# Copyright 2020 The SkyWater PDK Authors
#
# Licensed under the Apache License, Version 2.0 (the "License");
# you may not use this file except in compliance with the License.
# You may obtain a copy of the License at
#
#     https://www.apache.org/licenses/LICENSE-2.0
#
# Unless required by applicable law or agreed to in writing, software
# distributed under the License is distributed on an "AS IS" BASIS,
# WITHOUT WARRANTIES OR CONDITIONS OF ANY KIND, either express or implied.
# See the License for the specific language governing permissions and
# limitations under the License.
#
# SPDX-License-Identifier: Apache-2.0

VERSION 5.7 ;

BUSBITCHARS "[]" ;
DIVIDERCHAR "/" ;

UNITS
  TIME NANOSECONDS 1 ;
  CAPACITANCE PICOFARADS 1 ;
  RESISTANCE OHMS 1 ;
  DATABASE MICRONS 1000 ;
END UNITS

MANUFACTURINGGRID 0.005 ;

PROPERTYDEFINITIONS
  LAYER LEF58_TYPE STRING ;
END PROPERTYDEFINITIONS

# High density, single height
SITE unithd
  SYMMETRY Y ;
  CLASS CORE ;
  SIZE 0.46 BY 2.72 ;
END unithd

# High density, double height
SITE unithddbl
  SYMMETRY Y ;
  CLASS CORE ;
  SIZE 0.46 BY 5.44 ;
END unithddbl

LAYER nwell
  TYPE MASTERSLICE ;
  PROPERTY LEF58_TYPE "TYPE NWELL ;" ;
END nwell

LAYER pwell
  TYPE MASTERSLICE ;
  PROPERTY LEF58_TYPE "TYPE PWELL ;" ;
END pwell

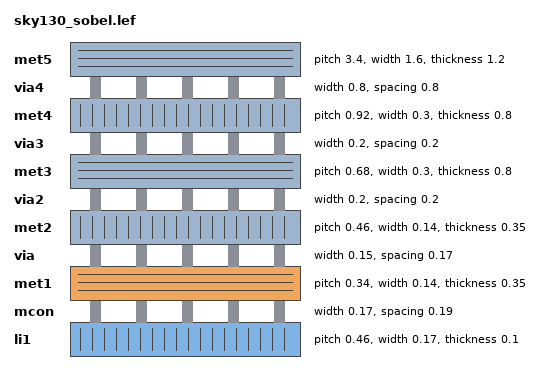
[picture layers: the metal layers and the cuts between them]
LAYER li1
  TYPE ROUTING ;
  DIRECTION VERTICAL ;

  PITCH 0.46 0.34 ;
  OFFSET 0.23 0.17 ;

  WIDTH 0.17 ;          # LI 1
  # SPACING  0.17 ;     # LI 2
  SPACINGTABLE
     PARALLELRUNLENGTH 0
     WIDTH 0 0.17 ;
  AREA 0.0561 ;         # LI 6
  THICKNESS 0.1 ;
  EDGECAPACITANCE 40.697E-6 ;
  CAPACITANCE CPERSQDIST 36.9866E-6 ;
  RESISTANCE RPERSQ 12.2 ;

  ANTENNAMODEL OXIDE1 ;
  ANTENNADIFFSIDEAREARATIO PWL ( ( 0 75 ) ( 0.0125 75 ) ( 0.0225 85.125 ) ( 22.5 10200 ) ) ;
END li1

LAYER mcon
  TYPE CUT ;

  WIDTH 0.17 ;                # Mcon 1
  SPACING 0.19 ;              # Mcon 2
  ENCLOSURE BELOW 0 0 ;       # Mcon 4
  ENCLOSURE ABOVE 0.03 0.06 ; # Met1 4 / Met1 5

  ANTENNADIFFAREARATIO PWL ( ( 0 3 ) ( 0.0125 3 ) ( 0.0225 3.405 ) ( 22.5 408 ) ) ;
  DCCURRENTDENSITY AVERAGE 0.36 ; # mA per via Iavg_max at Tj = 90oC

END mcon

LAYER met1
  TYPE ROUTING ;
  DIRECTION HORIZONTAL ;

  PITCH 0.34 ;
  OFFSET 0.17 ;

  WIDTH 0.14 ;                     # Met1 1
  # SPACING 0.14 ;                 # Met1 2
  # SPACING 0.28 RANGE 3.001 100 ; # Met1 3b
  SPACINGTABLE
     PARALLELRUNLENGTH 0
     WIDTH 0 0.14
     WIDTH 3 0.28 ;
  AREA 0.083 ;                     # Met1 6
  THICKNESS 0.35 ;

  ANTENNAMODEL OXIDE1 ;
  ANTENNADIFFSIDEAREARATIO PWL ( ( 0 400 ) ( 0.0125 400 ) ( 0.0225 2609 ) ( 22.5 11600 ) ) ;

  EDGECAPACITANCE 40.567E-6 ;
  CAPACITANCE CPERSQDIST 25.7784E-6 ;
  DCCURRENTDENSITY AVERAGE 2.8 ; # mA/um Iavg_max at Tj = 90oC
  ACCURRENTDENSITY RMS 6.1 ; # mA/um Irms_max at Tj = 90oC
  MAXIMUMDENSITY 70 ;
  DENSITYCHECKWINDOW 700 700 ;
  DENSITYCHECKSTEP 70 ;

  RESISTANCE RPERSQ 0.125 ;
END met1

LAYER via
  TYPE CUT ;
  WIDTH 0.15 ;                  # Via 1a
  SPACING 0.17 ;                # Via 2
  ENCLOSURE BELOW 0.055 0.085 ; # Via 4a / Via 5a
  ENCLOSURE ABOVE 0.055 0.085 ; # Met2 4 / Met2 5

  ANTENNADIFFAREARATIO PWL ( ( 0 6 ) ( 0.0125 6 ) ( 0.0225 6.81 ) ( 22.5 816 ) ) ;
  DCCURRENTDENSITY AVERAGE 0.29 ; # mA per via Iavg_max at Tj = 90oC
END via

LAYER met2
  TYPE ROUTING ;
  DIRECTION VERTICAL ;

  PITCH 0.46 ;
  OFFSET 0.23 ;

  WIDTH 0.14 ;                        # Met2 1
  # SPACING  0.14 ;                   # Met2 2
  # SPACING  0.28 RANGE 3.001 100 ;   # Met2 3b
  SPACINGTABLE
     PARALLELRUNLENGTH 0
     WIDTH 0 0.14
     WIDTH 3 0.28 ;
  AREA 0.0676 ;                       # Met2 6
  THICKNESS 0.35 ;

  EDGECAPACITANCE 37.759E-6 ;
  CAPACITANCE CPERSQDIST 16.9423E-6 ;
  RESISTANCE RPERSQ 0.125 ;
  DCCURRENTDENSITY AVERAGE 2.8 ; # mA/um Iavg_max at Tj = 90oC
  ACCURRENTDENSITY RMS 6.1 ; # mA/um Irms_max at Tj = 90oC

  ANTENNAMODEL OXIDE1 ;
  ANTENNADIFFSIDEAREARATIO PWL ( ( 0 400 ) ( 0.0125 400 ) ( 0.0225 2609 ) ( 22.5 11600 ) ) ;

  MAXIMUMDENSITY 70 ;
  DENSITYCHECKWINDOW 700 700 ;
  DENSITYCHECKSTEP 70 ;
END met2

# ******** Layer via2, type routing, number 44 **************
LAYER via2
  TYPE CUT ;
  WIDTH 0.2 ;                   # Via2 1
  SPACING 0.2 ;                 # Via2 2
  ENCLOSURE BELOW 0.04 0.085 ;  # Via2 4
  ENCLOSURE ABOVE 0.065 0.065 ; # Met3 4
  ANTENNADIFFAREARATIO PWL ( ( 0 6 ) ( 0.0125 6 ) ( 0.0225 6.81 ) ( 22.5 816 ) ) ;
  DCCURRENTDENSITY AVERAGE 0.48 ; # mA per via Iavg_max at Tj = 90oC
END via2

LAYER met3
  TYPE ROUTING ;
  DIRECTION HORIZONTAL ;

  PITCH 0.68 ;
  OFFSET 0.34 ;

  WIDTH 0.3 ;              # Met3 1
  # SPACING 0.3 ;          # Met3 2
  SPACINGTABLE
     PARALLELRUNLENGTH 0
     WIDTH 0 0.3
     WIDTH 3 0.4 ;
  AREA 0.24 ;              # Met3 6
  THICKNESS 0.8 ;

  EDGECAPACITANCE 40.989E-6 ;
  CAPACITANCE CPERSQDIST 12.3729E-6 ;
  RESISTANCE RPERSQ 0.047 ;
  DCCURRENTDENSITY AVERAGE 6.8 ; # mA/um Iavg_max at Tj = 90oC
  ACCURRENTDENSITY RMS 14.9 ; # mA/um Irms_max at Tj = 90oC

  ANTENNAMODEL OXIDE1 ;
  ANTENNADIFFSIDEAREARATIO PWL ( ( 0 400 ) ( 0.0125 400 ) ( 0.0225 2609 ) ( 22.5 11600 ) ) ;

  MAXIMUMDENSITY 70 ;
  DENSITYCHECKWINDOW 700 700 ;
  DENSITYCHECKSTEP 70 ;
END met3

LAYER via3
  TYPE CUT ;
  WIDTH 0.2 ;                   # Via3 1
  SPACING 0.2 ;                 # Via3 2
  ENCLOSURE BELOW 0.06 0.09 ;   # Via3 4 / Via3 5
  ENCLOSURE ABOVE 0.065 0.065 ; # Met4 3
  ANTENNADIFFAREARATIO PWL ( ( 0 6 ) ( 0.0125 6 ) ( 0.0225 6.81 ) ( 22.5 816 ) ) ;
  DCCURRENTDENSITY AVERAGE 0.48 ; # mA per via Iavg_max at Tj = 90oC
END via3

LAYER met4
  TYPE ROUTING ;
  DIRECTION VERTICAL ;

  PITCH 0.92 ;
  OFFSET 0.46 ;

  WIDTH 0.3 ;             # Met4 1
  # SPACING  0.3 ;             # Met4 2
  SPACINGTABLE
     PARALLELRUNLENGTH 0
     WIDTH 0 0.3
     WIDTH 3 0.4 ;
  AREA 0.24 ;            # Met4 4a

  THICKNESS 0.8 ;

  EDGECAPACITANCE 36.676E-6 ;
  CAPACITANCE CPERSQDIST 8.41537E-6 ;
  RESISTANCE RPERSQ 0.047 ;
  DCCURRENTDENSITY AVERAGE 6.8 ; # mA/um Iavg_max at Tj = 90oC
  ACCURRENTDENSITY RMS 14.9 ; # mA/um Irms_max at Tj = 90oC

  ANTENNAMODEL OXIDE1 ;
  ANTENNADIFFSIDEAREARATIO PWL ( ( 0 400 ) ( 0.0125 400 ) ( 0.0225 2609 ) ( 22.5 11600 ) ) ;

  MAXIMUMDENSITY 70 ;
  DENSITYCHECKWINDOW 700 700 ;
  DENSITYCHECKSTEP 70 ;
END met4

LAYER via4
  TYPE CUT ;

  WIDTH 0.8 ;                 # Via4 1
  SPACING 0.8 ;               # Via4 2
  ENCLOSURE BELOW 0.19 0.19 ; # Via4 4
  ENCLOSURE ABOVE 0.31 0.31 ; # Met5 3
  ANTENNADIFFAREARATIO PWL ( ( 0 6 ) ( 0.0125 6 ) ( 0.0225 6.81 ) ( 22.5 816 ) ) ;
  DCCURRENTDENSITY AVERAGE 2.49 ; # mA per via Iavg_max at Tj = 90oC
END via4

LAYER met5
  TYPE ROUTING ;
  DIRECTION HORIZONTAL ;

  PITCH 3.4 ;
  OFFSET 1.7 ;

  WIDTH 1.6 ;            # Met5 1
  #SPACING  1.6 ;        # Met5 2
  SPACINGTABLE
     PARALLELRUNLENGTH 0
     WIDTH 0 1.6 ;
  AREA 4 ;               # Met5 4

  THICKNESS 1.2 ;

  EDGECAPACITANCE 38.851E-6 ;
  CAPACITANCE CPERSQDIST 6.32063E-6 ;
  RESISTANCE RPERSQ 0.0285 ;
  DCCURRENTDENSITY AVERAGE 10.17 ; # mA/um Iavg_max at Tj = 90oC
  ACCURRENTDENSITY RMS 22.34 ; # mA/um Irms_max at Tj = 90oC

  ANTENNAMODEL OXIDE1 ;
  ANTENNADIFFSIDEAREARATIO PWL ( ( 0 400 ) ( 0.0125 400 ) ( 0.0225 2609 ) ( 22.5 11600 ) ) ;
END met5


### Routing via cells section   ###
# Plus via rule, metals are along the prefered direction
VIA L1M1_PR DEFAULT
  LAYER mcon ;
  RECT -0.085 -0.085 0.085 0.085 ;
  LAYER li1 ;
  RECT -0.085 -0.085 0.085 0.085 ;
  LAYER met1 ;
  RECT -0.145 -0.115 0.145 0.115 ;
END L1M1_PR

VIARULE L1M1_PR GENERATE
  LAYER li1 ;
  ENCLOSURE 0 0 ;
  LAYER met1 ;
  ENCLOSURE 0.06 0.03 ;
  LAYER mcon ;
  RECT -0.085 -0.085 0.085 0.085 ;
  SPACING 0.36 BY 0.36 ;
END L1M1_PR

# Plus via rule, metals are along the non prefered direction
VIA L1M1_PR_R DEFAULT
  LAYER mcon ;
  RECT -0.085 -0.085 0.085 0.085 ;
  LAYER li1 ;
  RECT -0.085 -0.085 0.085 0.085 ;
  LAYER met1 ;
  RECT -0.115 -0.145 0.115 0.145 ;
END L1M1_PR_R

VIARULE L1M1_PR_R GENERATE
  LAYER li1 ;
  ENCLOSURE 0 0 ;
  LAYER met1 ;
  ENCLOSURE 0.03 0.06 ;
  LAYER mcon ;
  RECT -0.085 -0.085 0.085 0.085 ;
  SPACING 0.36 BY 0.36 ;
END L1M1_PR_R

# Minus via rule, lower layer metal is along prefered direction
VIA L1M1_PR_M DEFAULT
  LAYER mcon ;
  RECT -0.085 -0.085 0.085 0.085 ;
  LAYER li1 ;
  RECT -0.085 -0.085 0.085 0.085 ;
  LAYER met1 ;
  RECT -0.115 -0.145 0.115 0.145 ;
END L1M1_PR_M

VIARULE L1M1_PR_M GENERATE
  LAYER li1 ;
  ENCLOSURE 0 0 ;
  LAYER met1 ;
  ENCLOSURE 0.03 0.06 ;
  LAYER mcon ;
  RECT -0.085 -0.085 0.085 0.085 ;
  SPACING 0.36 BY 0.36 ;
END L1M1_PR_M

# Minus via rule, upper layer metal is along prefered direction
VIA L1M1_PR_MR DEFAULT
  LAYER mcon ;
  RECT -0.085 -0.085 0.085 0.085 ;
  LAYER li1 ;
  RECT -0.085 -0.085 0.085 0.085 ;
  LAYER met1 ;
  RECT -0.145 -0.115 0.145 0.115 ;
END L1M1_PR_MR

VIARULE L1M1_PR_MR GENERATE
  LAYER li1 ;
  ENCLOSURE 0 0 ;
  LAYER met1 ;
  ENCLOSURE 0.06 0.03 ;
  LAYER mcon ;
  RECT -0.085 -0.085 0.085 0.085 ;
  SPACING 0.36 BY 0.36 ;
END L1M1_PR_MR

# Centered via rule, we really do not want to use it
VIA L1M1_PR_C DEFAULT
  LAYER mcon ;
  RECT -0.085 -0.085 0.085 0.085 ;
  LAYER li1 ;
  RECT -0.085 -0.085 0.085 0.085 ;
  LAYER met1 ;
  RECT -0.145 -0.145 0.145 0.145 ;
END L1M1_PR_C

VIARULE L1M1_PR_C GENERATE
  LAYER li1 ;
  ENCLOSURE 0 0 ;
  LAYER met1 ;
  ENCLOSURE 0.06 0.06 ;
  LAYER mcon ;
  RECT -0.085 -0.085 0.085 0.085 ;
  SPACING 0.36 BY 0.36 ;
END L1M1_PR_C

# Plus via rule, metals are along the prefered direction
VIA M1M2_PR DEFAULT
  LAYER via ;
  RECT -0.075 -0.075 0.075 0.075 ;
  LAYER met1 ;
  RECT -0.16 -0.13 0.16 0.13 ;
  LAYER met2 ;
  RECT -0.13 -0.16 0.13 0.16 ;
END M1M2_PR

VIARULE M1M2_PR GENERATE
  LAYER met1 ;
  ENCLOSURE 0.085 0.055 ;
  LAYER met2 ;
  ENCLOSURE 0.055 0.085 ;
  LAYER via ;
  RECT -0.075 -0.075 0.075 0.075 ;
  SPACING 0.32 BY 0.32 ;
END M1M2_PR

# Plus via rule, metals are along the non prefered direction
VIA M1M2_PR_R DEFAULT
  LAYER via ;
  RECT -0.075 -0.075 0.075 0.075 ;
  LAYER met1 ;
  RECT -0.13 -0.16 0.13 0.16 ;
  LAYER met2 ;
  RECT -0.16 -0.13 0.16 0.13 ;
END M1M2_PR_R

VIARULE M1M2_PR_R GENERATE
  LAYER met1 ;
  ENCLOSURE 0.055 0.085 ;
  LAYER met2 ;
  ENCLOSURE 0.085 0.055 ;
  LAYER via ;
  RECT -0.075 -0.075 0.075 0.075 ;
  SPACING 0.32 BY 0.32 ;
END M1M2_PR_R

# Minus via rule, lower layer metal is along prefered direction
VIA M1M2_PR_M DEFAULT
  LAYER via ;
  RECT -0.075 -0.075 0.075 0.075 ;
  LAYER met1 ;
  RECT -0.16 -0.13 0.16 0.13 ;
  LAYER met2 ;
  RECT -0.16 -0.13 0.16 0.13 ;
END M1M2_PR_M

VIARULE M1M2_PR_M GENERATE
  LAYER met1 ;
  ENCLOSURE 0.085 0.055 ;
  LAYER met2 ;
  ENCLOSURE 0.085 0.055 ;
  LAYER via ;
  RECT -0.075 -0.075 0.075 0.075 ;
  SPACING 0.32 BY 0.32 ;
END M1M2_PR_M

# Minus via rule, upper layer metal is along prefered direction
VIA M1M2_PR_MR DEFAULT
  LAYER via ;
  RECT -0.075 -0.075 0.075 0.075 ;
  LAYER met1 ;
  RECT -0.13 -0.16 0.13 0.16 ;
  LAYER met2 ;
  RECT -0.13 -0.16 0.13 0.16 ;
END M1M2_PR_MR

VIARULE M1M2_PR_MR GENERATE
  LAYER met1 ;
  ENCLOSURE 0.055 0.085 ;
  LAYER met2 ;
  ENCLOSURE 0.055 0.085 ;
  LAYER via ;
  RECT -0.075 -0.075 0.075 0.075 ;
  SPACING 0.32 BY 0.32 ;
END M1M2_PR_MR

# Centered via rule, we really do not want to use it
VIA M1M2_PR_C DEFAULT
  LAYER via ;
  RECT -0.075 -0.075 0.075 0.075 ;
  LAYER met1 ;
  RECT -0.16 -0.16 0.16 0.16 ;
  LAYER met2 ;
  RECT -0.16 -0.16 0.16 0.16 ;
END M1M2_PR_C

VIARULE M1M2_PR_C GENERATE
  LAYER met1 ;
  ENCLOSURE 0.085 0.085 ;
  LAYER met2 ;
  ENCLOSURE 0.085 0.085 ;
  LAYER via ;
  RECT -0.075 -0.075 0.075 0.075 ;
  SPACING 0.32 BY 0.32 ;
END M1M2_PR_C

# Plus via rule, metals are along the prefered direction
VIA M2M3_PR DEFAULT
  LAYER via2 ;
  RECT -0.1 -0.1 0.1 0.1 ;
  LAYER met2 ;
  RECT -0.14 -0.185 0.14 0.185 ;
  LAYER met3 ;
  RECT -0.165 -0.165 0.165 0.165 ;
END M2M3_PR

VIARULE M2M3_PR GENERATE
  LAYER met2 ;
  ENCLOSURE 0.04 0.085 ;
  LAYER met3 ;
  ENCLOSURE 0.065 0.065 ;
  LAYER via2 ;
  RECT -0.1 -0.1 0.1 0.1 ;
  SPACING 0.4 BY 0.4 ;
END M2M3_PR

# Plus via rule, metals are along the non prefered direction
VIA M2M3_PR_R DEFAULT
  LAYER via2 ;
  RECT -0.1 -0.1 0.1 0.1 ;
  LAYER met2 ;
  RECT -0.185 -0.14 0.185 0.14 ;
  LAYER met3 ;
  RECT -0.165 -0.165 0.165 0.165 ;
END M2M3_PR_R

VIARULE M2M3_PR_R GENERATE
  LAYER met2 ;
  ENCLOSURE 0.085 0.04 ;
  LAYER met3 ;
  ENCLOSURE 0.065 0.065 ;
  LAYER via2 ;
  RECT -0.1 -0.1 0.1 0.1 ;
  SPACING 0.4 BY 0.4 ;
END M2M3_PR_R

# Minus via rule, lower layer metal is along prefered direction
VIA M2M3_PR_M DEFAULT
  LAYER via2 ;
  RECT -0.1 -0.1 0.1 0.1 ;
  LAYER met2 ;
  RECT -0.14 -0.185 0.14 0.185 ;
  LAYER met3 ;
  RECT -0.165 -0.165 0.165 0.165 ;
END M2M3_PR_M

VIARULE M2M3_PR_M GENERATE
  LAYER met2 ;
  ENCLOSURE 0.04 0.085 ;
  LAYER met3 ;
  ENCLOSURE 0.065 0.065 ;
  LAYER via2 ;
  RECT -0.1 -0.1 0.1 0.1 ;
  SPACING 0.4 BY 0.4 ;
END M2M3_PR_M

# Minus via rule, upper layer metal is along prefered direction
VIA M2M3_PR_MR DEFAULT
  LAYER via2 ;
  RECT -0.1 -0.1 0.1 0.1 ;
  LAYER met2 ;
  RECT -0.185 -0.14 0.185 0.14 ;
  LAYER met3 ;
  RECT -0.165 -0.165 0.165 0.165 ;
END M2M3_PR_MR

VIARULE M2M3_PR_MR GENERATE
  LAYER met2 ;
  ENCLOSURE 0.085 0.04 ;
  LAYER met3 ;
  ENCLOSURE 0.065 0.065 ;
  LAYER via2 ;
  RECT -0.1 -0.1 0.1 0.1 ;
  SPACING 0.4 BY 0.4 ;
END M2M3_PR_MR

# Centered via rule, we really do not want to use it
VIA M2M3_PR_C DEFAULT
  LAYER via2 ;
  RECT -0.1 -0.1 0.1 0.1 ;
  LAYER met2 ;
  RECT -0.185 -0.185 0.185 0.185 ;
  LAYER met3 ;
  RECT -0.165 -0.165 0.165 0.165 ;
END M2M3_PR_C

VIARULE M2M3_PR_C GENERATE
  LAYER met2 ;
  ENCLOSURE 0.085 0.085 ;
  LAYER met3 ;
  ENCLOSURE 0.065 0.065 ;
  LAYER via2 ;
  RECT -0.1 -0.1 0.1 0.1 ;
  SPACING 0.4 BY 0.4 ;
END M2M3_PR_C

# Plus via rule, metals are along the prefered direction
VIA M3M4_PR DEFAULT
  LAYER via3 ;
  RECT -0.1 -0.1 0.1 0.1 ;
  LAYER met3 ;
  RECT -0.19 -0.16 0.19 0.16 ;
  LAYER met4 ;
  RECT -0.165 -0.165 0.165 0.165 ;
END M3M4_PR

VIARULE M3M4_PR GENERATE
  LAYER met3 ;
  ENCLOSURE 0.09 0.06 ;
  LAYER met4 ;
  ENCLOSURE 0.065 0.065 ;
  LAYER via3 ;
  RECT -0.1 -0.1 0.1 0.1 ;
  SPACING 0.4 BY 0.4 ;
END M3M4_PR

# Plus via rule, metals are along the non prefered direction
VIA M3M4_PR_R DEFAULT
  LAYER via3 ;
  RECT -0.1 -0.1 0.1 0.1 ;
  LAYER met3 ;
  RECT -0.16 -0.19 0.16 0.19 ;
  LAYER met4 ;
  RECT -0.165 -0.165 0.165 0.165 ;
END M3M4_PR_R

VIARULE M3M4_PR_R GENERATE
  LAYER met3 ;
  ENCLOSURE 0.06 0.09 ;
  LAYER met4 ;
  ENCLOSURE 0.065 0.065 ;
  LAYER via3 ;
  RECT -0.1 -0.1 0.1 0.1 ;
  SPACING 0.4 BY 0.4 ;
END M3M4_PR_R

# Minus via rule, lower layer metal is along prefered direction
VIA M3M4_PR_M DEFAULT
  LAYER via3 ;
  RECT -0.1 -0.1 0.1 0.1 ;
  LAYER met3 ;
  RECT -0.19 -0.16 0.19 0.16 ;
  LAYER met4 ;
  RECT -0.165 -0.165 0.165 0.165 ;
END M3M4_PR_M

VIARULE M3M4_PR_M GENERATE
  LAYER met3 ;
  ENCLOSURE 0.09 0.06 ;
  LAYER met4 ;
  ENCLOSURE 0.065 0.065 ;
  LAYER via3 ;
  RECT -0.1 -0.1 0.1 0.1 ;
  SPACING 0.4 BY 0.4 ;
END M3M4_PR_M

# Minus via rule, upper layer metal is along prefered direction
VIA M3M4_PR_MR DEFAULT
  LAYER via3 ;
  RECT -0.1 -0.1 0.1 0.1 ;
  LAYER met3 ;
  RECT -0.16 -0.19 0.16 0.19 ;
  LAYER met4 ;
  RECT -0.165 -0.165 0.165 0.165 ;
END M3M4_PR_MR

VIARULE M3M4_PR_MR GENERATE
  LAYER met3 ;
  ENCLOSURE 0.06 0.09 ;
  LAYER met4 ;
  ENCLOSURE 0.065 0.065 ;
  LAYER via3 ;
  RECT -0.1 -0.1 0.1 0.1 ;
  SPACING 0.4 BY 0.4 ;
END M3M4_PR_MR

# Centered via rule, we really do not want to use it
VIA M3M4_PR_C DEFAULT
  LAYER via3 ;
  RECT -0.1 -0.1 0.1 0.1 ;
  LAYER met3 ;
  RECT -0.19 -0.19 0.19 0.19 ;
  LAYER met4 ;
  RECT -0.165 -0.165 0.165 0.165 ;
END M3M4_PR_C

VIARULE M3M4_PR_C GENERATE
  LAYER met3 ;
  ENCLOSURE 0.09 0.09 ;
  LAYER met4 ;
  ENCLOSURE 0.065 0.065 ;
  LAYER via3 ;
  RECT -0.1 -0.1 0.1 0.1 ;
  SPACING 0.4 BY 0.4 ;
END M3M4_PR_C

# Plus via rule, metals are along the prefered direction
VIA M4M5_PR DEFAULT
  LAYER via4 ;
  RECT -0.4 -0.4 0.4 0.4 ;
  LAYER met4 ;
  RECT -0.59 -0.59 0.59 0.59 ;
  LAYER met5 ;
  RECT -0.71 -0.71 0.71 0.71 ;
END M4M5_PR

VIARULE M4M5_PR GENERATE
  LAYER met4 ;
  ENCLOSURE 0.19 0.19 ;
  LAYER met5 ;
  ENCLOSURE 0.31 0.31 ;
  LAYER via4 ;
  RECT -0.4 -0.4 0.4 0.4 ;
  SPACING 1.6 BY 1.6 ;
END M4M5_PR

# Plus via rule, metals are along the non prefered direction
VIA M4M5_PR_R DEFAULT
  LAYER via4 ;
  RECT -0.4 -0.4 0.4 0.4 ;
  LAYER met4 ;
  RECT -0.59 -0.59 0.59 0.59 ;
  LAYER met5 ;
  RECT -0.71 -0.71 0.71 0.71 ;
END M4M5_PR_R

VIARULE M4M5_PR_R GENERATE
  LAYER met4 ;
  ENCLOSURE 0.19 0.19 ;
  LAYER met5 ;
  ENCLOSURE 0.31 0.31 ;
  LAYER via4 ;
  RECT -0.4 -0.4 0.4 0.4 ;
  SPACING 1.6 BY 1.6 ;
END M4M5_PR_R

# Minus via rule, lower layer metal is along prefered direction
VIA M4M5_PR_M DEFAULT
  LAYER via4 ;
  RECT -0.4 -0.4 0.4 0.4 ;
  LAYER met4 ;
  RECT -0.59 -0.59 0.59 0.59 ;
  LAYER met5 ;
  RECT -0.71 -0.71 0.71 0.71 ;
END M4M5_PR_M

VIARULE M4M5_PR_M GENERATE
  LAYER met4 ;
  ENCLOSURE 0.19 0.19 ;
  LAYER met5 ;
  ENCLOSURE 0.31 0.31 ;
  LAYER via4 ;
  RECT -0.4 -0.4 0.4 0.4 ;
  SPACING 1.6 BY 1.6 ;
END M4M5_PR_M

# Minus via rule, upper layer metal is along prefered direction
VIA M4M5_PR_MR DEFAULT
  LAYER via4 ;
  RECT -0.4 -0.4 0.4 0.4 ;
  LAYER met4 ;
  RECT -0.59 -0.59 0.59 0.59 ;
  LAYER met5 ;
  RECT -0.71 -0.71 0.71 0.71 ;
END M4M5_PR_MR

VIARULE M4M5_PR_MR GENERATE
  LAYER met4 ;
  ENCLOSURE 0.19 0.19 ;
  LAYER met5 ;
  ENCLOSURE 0.31 0.31 ;
  LAYER via4 ;
  RECT -0.4 -0.4 0.4 0.4 ;
  SPACING 1.6 BY 1.6 ;
END M4M5_PR_MR

# Centered via rule, we really do not want to use it
VIA M4M5_PR_C DEFAULT
  LAYER via4 ;
  RECT -0.4 -0.4 0.4 0.4 ;
  LAYER met4 ;
  RECT -0.59 -0.59 0.59 0.59 ;
  LAYER met5 ;
  RECT -0.71 -0.71 0.71 0.71 ;
END M4M5_PR_C

VIARULE M4M5_PR_C GENERATE
  LAYER met4 ;
  ENCLOSURE 0.19 0.19 ;
  LAYER met5 ;
  ENCLOSURE 0.31 0.31 ;
  LAYER via4 ;
  RECT -0.4 -0.4 0.4 0.4 ;
  SPACING 1.6 BY 1.6 ;
END M4M5_PR_C
###  end of single via cells   ###

END LIBRARY
# Copyright 2020 The SkyWater PDK Authors
#
# Licensed under the Apache License, Version 2.0 (the "License");
# you may not use this file except in compliance with the License.
# You may obtain a copy of the License at
#
#     https://www.apache.org/licenses/LICENSE-2.0
#
# Unless required by applicable law or agreed to in writing, software
# distributed under the License is distributed on an "AS IS" BASIS,
# WITHOUT WARRANTIES OR CONDITIONS OF ANY KIND, either express or implied.
# See the License for the specific language governing permissions and
# limitations under the License.
#
# SPDX-License-Identifier: Apache-2.0

VERSION 5.5 ;
NAMESCASESENSITIVE ON ;
BUSBITCHARS "[]" ;
DIVIDERCHAR "/" ;
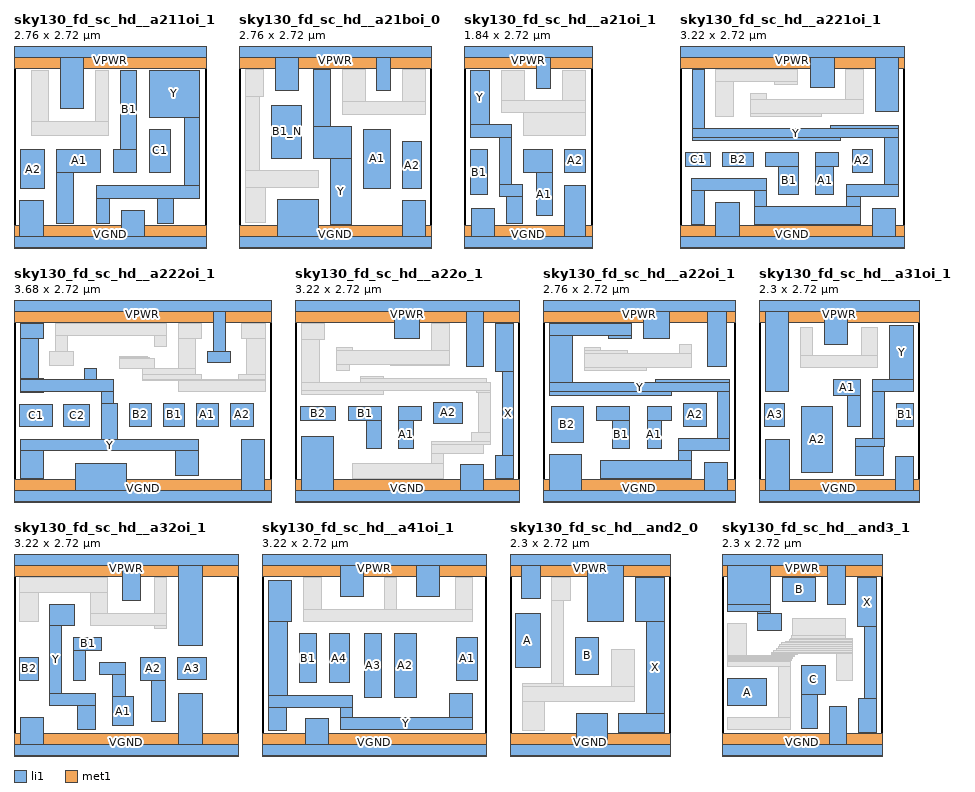
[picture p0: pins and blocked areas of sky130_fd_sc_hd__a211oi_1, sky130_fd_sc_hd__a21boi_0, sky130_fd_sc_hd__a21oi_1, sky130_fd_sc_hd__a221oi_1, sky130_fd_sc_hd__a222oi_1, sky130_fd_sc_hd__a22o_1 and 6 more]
MACRO sky130_fd_sc_hd__a211oi_1
  CLASS CORE ;
  SOURCE USER ;
  ORIGIN  0.000000  0.000000 ;
  SIZE  2.760000 BY  2.720000 ;
  SYMMETRY X Y R90 ;
  SITE unithd ;
  PIN A1
    ANTENNAGATEAREA  0.247500 ;
    DIRECTION INPUT ;
    USE SIGNAL ;
    PORT
      LAYER li1 ;
        RECT 0.605000 0.265000 0.855000 0.995000 ;
        RECT 0.605000 0.995000 1.245000 1.325000 ;
    END
  END A1
  PIN A2
    ANTENNAGATEAREA  0.247500 ;
    DIRECTION INPUT ;
    USE SIGNAL ;
    PORT
      LAYER li1 ;
        RECT 0.095000 0.765000 0.435000 1.325000 ;
    END
  END A2
  PIN B1
    ANTENNAGATEAREA  0.247500 ;
    DIRECTION INPUT ;
    USE SIGNAL ;
    PORT
      LAYER li1 ;
        RECT 1.425000 0.995000 1.755000 1.325000 ;
        RECT 1.525000 1.325000 1.755000 2.455000 ;
    END
  END B1
  PIN C1
    ANTENNAGATEAREA  0.247500 ;
    DIRECTION INPUT ;
    USE SIGNAL ;
    PORT
      LAYER li1 ;
        RECT 1.935000 0.995000 2.235000 1.615000 ;
    END
  END C1
  PIN Y
    ANTENNADIFFAREA  0.619250 ;
    DIRECTION OUTPUT ;
    USE SIGNAL ;
    PORT
      LAYER li1 ;
        RECT 1.180000 0.265000 1.365000 0.625000 ;
        RECT 1.180000 0.625000 2.660000 0.815000 ;
        RECT 1.935000 1.785000 2.660000 2.455000 ;
        RECT 2.055000 0.265000 2.280000 0.625000 ;
        RECT 2.445000 0.815000 2.660000 1.785000 ;
    END
  END Y
  PIN VGND
    DIRECTION INOUT ;
    SHAPE ABUTMENT ;
    USE GROUND ;
    PORT
      LAYER li1 ;
        RECT 0.000000 -0.085000 2.760000 0.085000 ;
        RECT 0.085000  0.085000 0.425000 0.595000 ;
        RECT 1.545000  0.085000 1.875000 0.455000 ;
    END
    PORT
      LAYER met1 ;
        RECT 0.000000 -0.240000 2.760000 0.240000 ;
    END
  END VGND
  PIN VPWR
    DIRECTION INOUT ;
    SHAPE ABUTMENT ;
    USE POWER ;
    PORT
      LAYER li1 ;
        RECT 0.000000 2.635000 2.760000 2.805000 ;
        RECT 0.670000 1.905000 1.000000 2.635000 ;
    END
    PORT
      LAYER met1 ;
        RECT 0.000000 2.480000 2.760000 2.960000 ;
    END
  END VPWR
  OBS
    LAYER li1 ;
      RECT 0.250000 1.525000 1.355000 1.725000 ;
      RECT 0.250000 1.725000 0.500000 2.455000 ;
      RECT 1.170000 1.725000 1.355000 2.455000 ;
  END
END sky130_fd_sc_hd__a211oi_1
END LIBRARY
# Copyright 2020 The SkyWater PDK Authors
#
# Licensed under the Apache License, Version 2.0 (the "License");
# you may not use this file except in compliance with the License.
# You may obtain a copy of the License at
#
#     https://www.apache.org/licenses/LICENSE-2.0
#
# Unless required by applicable law or agreed to in writing, software
# distributed under the License is distributed on an "AS IS" BASIS,
# WITHOUT WARRANTIES OR CONDITIONS OF ANY KIND, either express or implied.
# See the License for the specific language governing permissions and
# limitations under the License.
#
# SPDX-License-Identifier: Apache-2.0

VERSION 5.5 ;
NAMESCASESENSITIVE ON ;
BUSBITCHARS "[]" ;
DIVIDERCHAR "/" ;
MACRO sky130_fd_sc_hd__a21boi_0
  CLASS CORE ;
  SOURCE USER ;
  ORIGIN  0.000000  0.000000 ;
  SIZE  2.760000 BY  2.720000 ;
  SYMMETRY X Y R90 ;
  SITE unithd ;
  PIN A1
    ANTENNAGATEAREA  0.159000 ;
    DIRECTION INPUT ;
    USE SIGNAL ;
    PORT
      LAYER li1 ;
        RECT 1.780000 0.765000 2.170000 1.615000 ;
    END
  END A1
  PIN A2
    ANTENNAGATEAREA  0.159000 ;
    DIRECTION INPUT ;
    USE SIGNAL ;
    PORT
      LAYER li1 ;
        RECT 2.340000 0.765000 2.615000 1.435000 ;
    END
  END A2
  PIN B1_N
    ANTENNAGATEAREA  0.126000 ;
    DIRECTION INPUT ;
    USE SIGNAL ;
    PORT
      LAYER li1 ;
        RECT 0.470000 1.200000 0.895000 1.955000 ;
    END
  END B1_N
  PIN Y
    ANTENNADIFFAREA  0.392200 ;
    DIRECTION OUTPUT ;
    USE SIGNAL ;
    PORT
      LAYER li1 ;
        RECT 1.065000 1.200000 1.610000 1.655000 ;
        RECT 1.065000 1.655000 1.305000 2.465000 ;
        RECT 1.315000 0.255000 1.610000 1.200000 ;
    END
  END Y
  PIN VGND
    DIRECTION INOUT ;
    SHAPE ABUTMENT ;
    USE GROUND ;
    PORT
      LAYER li1 ;
        RECT 0.000000 -0.085000 2.760000 0.085000 ;
        RECT 0.550000  0.085000 1.145000 0.610000 ;
        RECT 2.335000  0.085000 2.665000 0.595000 ;
    END
    PORT
      LAYER met1 ;
        RECT 0.000000 -0.240000 2.760000 0.240000 ;
    END
  END VGND
  PIN VPWR
    DIRECTION INOUT ;
    SHAPE ABUTMENT ;
    USE POWER ;
    PORT
      LAYER li1 ;
        RECT 0.000000 2.635000 2.760000 2.805000 ;
        RECT 0.525000 2.175000 0.855000 2.635000 ;
        RECT 1.975000 2.175000 2.165000 2.635000 ;
    END
    PORT
      LAYER met1 ;
        RECT 0.000000 2.480000 2.760000 2.960000 ;
    END
  END VPWR
  OBS
    LAYER li1 ;
      RECT 0.095000 0.280000 0.380000 0.780000 ;
      RECT 0.095000 0.780000 1.145000 1.030000 ;
      RECT 0.095000 1.030000 0.300000 2.085000 ;
      RECT 0.095000 2.085000 0.355000 2.465000 ;
      RECT 1.475000 1.825000 2.665000 2.005000 ;
      RECT 1.475000 2.005000 1.805000 2.465000 ;
      RECT 2.335000 2.005000 2.665000 2.465000 ;
  END
END sky130_fd_sc_hd__a21boi_0
END LIBRARY
# Copyright 2020 The SkyWater PDK Authors
#
# Licensed under the Apache License, Version 2.0 (the "License");
# you may not use this file except in compliance with the License.
# You may obtain a copy of the License at
#
#     https://www.apache.org/licenses/LICENSE-2.0
#
# Unless required by applicable law or agreed to in writing, software
# distributed under the License is distributed on an "AS IS" BASIS,
# WITHOUT WARRANTIES OR CONDITIONS OF ANY KIND, either express or implied.
# See the License for the specific language governing permissions and
# limitations under the License.
#
# SPDX-License-Identifier: Apache-2.0

VERSION 5.5 ;
NAMESCASESENSITIVE ON ;
BUSBITCHARS "[]" ;
DIVIDERCHAR "/" ;
MACRO sky130_fd_sc_hd__a21oi_1
  CLASS CORE ;
  SOURCE USER ;
  ORIGIN  0.000000  0.000000 ;
  SIZE  1.840000 BY  2.720000 ;
  SYMMETRY X Y R90 ;
  SITE unithd ;
  PIN A1
    ANTENNAGATEAREA  0.247500 ;
    DIRECTION INPUT ;
    USE SIGNAL ;
    PORT
      LAYER li1 ;
        RECT 0.850000 0.995000 1.265000 1.325000 ;
        RECT 1.035000 0.375000 1.265000 0.995000 ;
    END
  END A1
  PIN A2
    ANTENNAGATEAREA  0.247500 ;
    DIRECTION INPUT ;
    USE SIGNAL ;
    PORT
      LAYER li1 ;
        RECT 1.445000 0.995000 1.740000 1.325000 ;
    END
  END A2
  PIN B1
    ANTENNAGATEAREA  0.247500 ;
    DIRECTION INPUT ;
    USE SIGNAL ;
    PORT
      LAYER li1 ;
        RECT 0.095000 0.675000 0.335000 1.325000 ;
    END
  END B1
  PIN Y
    ANTENNADIFFAREA  0.447000 ;
    DIRECTION OUTPUT ;
    USE SIGNAL ;
    PORT
      LAYER li1 ;
        RECT 0.095000 1.495000 0.680000 1.685000 ;
        RECT 0.095000 1.685000 0.370000 2.455000 ;
        RECT 0.505000 0.645000 0.835000 0.825000 ;
        RECT 0.505000 0.825000 0.680000 1.495000 ;
        RECT 0.610000 0.265000 0.835000 0.645000 ;
    END
  END Y
  PIN VGND
    DIRECTION INOUT ;
    SHAPE ABUTMENT ;
    USE GROUND ;
    PORT
      LAYER li1 ;
        RECT 0.000000 -0.085000 1.840000 0.085000 ;
        RECT 0.110000  0.085000 0.440000 0.475000 ;
        RECT 1.445000  0.085000 1.745000 0.815000 ;
    END
    PORT
      LAYER met1 ;
        RECT 0.000000 -0.240000 1.840000 0.240000 ;
    END
  END VGND
  PIN VPWR
    DIRECTION INOUT ;
    SHAPE ABUTMENT ;
    USE POWER ;
    PORT
      LAYER li1 ;
        RECT 0.000000 2.635000 1.840000 2.805000 ;
        RECT 1.040000 2.195000 1.235000 2.635000 ;
    END
    PORT
      LAYER met1 ;
        RECT 0.000000 2.480000 1.840000 2.960000 ;
    END
  END VPWR
  OBS
    LAYER li1 ;
      RECT 0.540000 1.855000 1.745000 2.025000 ;
      RECT 0.540000 2.025000 0.870000 2.455000 ;
      RECT 0.850000 1.525000 1.745000 1.855000 ;
      RECT 1.415000 2.025000 1.745000 2.455000 ;
  END
END sky130_fd_sc_hd__a21oi_1
END LIBRARY
# Copyright 2020 The SkyWater PDK Authors
#
# Licensed under the Apache License, Version 2.0 (the "License");
# you may not use this file except in compliance with the License.
# You may obtain a copy of the License at
#
#     https://www.apache.org/licenses/LICENSE-2.0
#
# Unless required by applicable law or agreed to in writing, software
# distributed under the License is distributed on an "AS IS" BASIS,
# WITHOUT WARRANTIES OR CONDITIONS OF ANY KIND, either express or implied.
# See the License for the specific language governing permissions and
# limitations under the License.
#
# SPDX-License-Identifier: Apache-2.0

VERSION 5.5 ;
NAMESCASESENSITIVE ON ;
BUSBITCHARS "[]" ;
DIVIDERCHAR "/" ;
MACRO sky130_fd_sc_hd__a221oi_1
  CLASS CORE ;
  SOURCE USER ;
  ORIGIN  0.000000  0.000000 ;
  SIZE  3.220000 BY  2.720000 ;
  SYMMETRY X Y R90 ;
  SITE unithd ;
  PIN A1
    ANTENNAGATEAREA  0.247500 ;
    DIRECTION INPUT ;
    USE SIGNAL ;
    PORT
      LAYER li1 ;
        RECT 1.945000 0.675000 2.200000 1.075000 ;
        RECT 1.945000 1.075000 2.275000 1.285000 ;
    END
  END A1
  PIN A2
    ANTENNAGATEAREA  0.247500 ;
    DIRECTION INPUT ;
    USE SIGNAL ;
    PORT
      LAYER li1 ;
        RECT 2.470000 0.995000 2.755000 1.325000 ;
    END
  END A2
  PIN B1
    ANTENNAGATEAREA  0.247500 ;
    DIRECTION INPUT ;
    USE SIGNAL ;
    PORT
      LAYER li1 ;
        RECT 1.225000 1.075000 1.695000 1.285000 ;
        RECT 1.415000 0.675000 1.695000 1.075000 ;
    END
  END B1
  PIN B2
    ANTENNAGATEAREA  0.247500 ;
    DIRECTION INPUT ;
    USE SIGNAL ;
    PORT
      LAYER li1 ;
        RECT 0.615000 1.075000 1.055000 1.285000 ;
    END
  END B2
  PIN C1
    ANTENNAGATEAREA  0.247500 ;
    DIRECTION INPUT ;
    USE SIGNAL ;
    PORT
      LAYER li1 ;
        RECT 0.085000 1.075000 0.435000 1.285000 ;
    END
  END C1
  PIN Y
    ANTENNADIFFAREA  0.767000 ;
    DIRECTION OUTPUT ;
    USE SIGNAL ;
    PORT
      LAYER li1 ;
        RECT 0.170000 0.255000 0.345000 0.735000 ;
        RECT 0.170000 0.735000 1.235000 0.905000 ;
        RECT 0.175000 1.455000 2.300000 1.495000 ;
        RECT 0.175000 1.495000 3.135000 1.625000 ;
        RECT 0.175000 1.625000 0.345000 2.465000 ;
        RECT 1.065000 0.255000 2.580000 0.505000 ;
        RECT 1.065000 0.505000 1.235000 0.735000 ;
        RECT 2.150000 1.625000 3.135000 1.665000 ;
        RECT 2.380000 0.505000 2.580000 0.655000 ;
        RECT 2.380000 0.655000 3.135000 0.825000 ;
        RECT 2.925000 0.825000 3.135000 1.495000 ;
    END
  END Y
  PIN VGND
    DIRECTION INOUT ;
    SHAPE ABUTMENT ;
    USE GROUND ;
    PORT
      LAYER li1 ;
        RECT 0.000000 -0.085000 3.220000 0.085000 ;
        RECT 0.515000  0.085000 0.845000 0.565000 ;
        RECT 2.750000  0.085000 3.080000 0.485000 ;
    END
    PORT
      LAYER met1 ;
        RECT 0.000000 -0.240000 3.220000 0.240000 ;
    END
  END VGND
  PIN VPWR
    DIRECTION INOUT ;
    SHAPE ABUTMENT ;
    USE POWER ;
    PORT
      LAYER li1 ;
        RECT 0.000000 2.635000 3.220000 2.805000 ;
        RECT 1.875000 2.215000 2.205000 2.635000 ;
        RECT 2.795000 1.875000 3.125000 2.635000 ;
    END
    PORT
      LAYER met1 ;
        RECT 0.000000 2.480000 3.220000 2.960000 ;
    END
  END VPWR
  OBS
    LAYER li1 ;
      RECT 0.515000 1.795000 0.765000 2.295000 ;
      RECT 0.515000 2.295000 1.685000 2.465000 ;
      RECT 1.015000 1.795000 2.025000 1.835000 ;
      RECT 1.015000 1.835000 2.625000 2.045000 ;
      RECT 1.015000 2.045000 1.240000 2.125000 ;
      RECT 1.355000 2.255000 1.685000 2.295000 ;
      RECT 2.375000 2.045000 2.625000 2.465000 ;
  END
END sky130_fd_sc_hd__a221oi_1
END LIBRARY
# Copyright 2020 The SkyWater PDK Authors
#
# Licensed under the Apache License, Version 2.0 (the "License");
# you may not use this file except in compliance with the License.
# You may obtain a copy of the License at
#
#     https://www.apache.org/licenses/LICENSE-2.0
#
# Unless required by applicable law or agreed to in writing, software
# distributed under the License is distributed on an "AS IS" BASIS,
# WITHOUT WARRANTIES OR CONDITIONS OF ANY KIND, either express or implied.
# See the License for the specific language governing permissions and
# limitations under the License.
#
# SPDX-License-Identifier: Apache-2.0

VERSION 5.5 ;
NAMESCASESENSITIVE ON ;
BUSBITCHARS "[]" ;
DIVIDERCHAR "/" ;
MACRO sky130_fd_sc_hd__a222oi_1
  CLASS CORE ;
  SOURCE USER ;
  ORIGIN  0.000000  0.000000 ;
  SIZE  3.680000 BY  2.720000 ;
  SYMMETRY X Y R90 ;
  SITE unithd ;
  PIN A1
    ANTENNAGATEAREA  0.246000 ;
    DIRECTION INPUT ;
    USE SIGNAL ;
    PORT
      LAYER li1 ;
        RECT 2.615000 1.000000 2.925000 1.330000 ;
    END
  END A1
  PIN A2
    ANTENNAGATEAREA  0.246000 ;
    DIRECTION INPUT ;
    USE SIGNAL ;
    PORT
      LAYER li1 ;
        RECT 3.095000 1.000000 3.435000 1.330000 ;
    END
  END A2
  PIN B1
    ANTENNAGATEAREA  0.246000 ;
    DIRECTION INPUT ;
    USE SIGNAL ;
    PORT
      LAYER li1 ;
        RECT 2.135000 1.000000 2.445000 1.330000 ;
    END
  END B1
  PIN B2
    ANTENNAGATEAREA  0.246000 ;
    DIRECTION INPUT ;
    USE SIGNAL ;
    PORT
      LAYER li1 ;
        RECT 1.655000 1.000000 1.965000 1.330000 ;
    END
  END B2
  PIN C1
    ANTENNAGATEAREA  0.246000 ;
    DIRECTION INPUT ;
    USE SIGNAL ;
    PORT
      LAYER li1 ;
        RECT 0.085000 1.000000 0.545000 1.315000 ;
    END
  END C1
  PIN C2
    ANTENNAGATEAREA  0.246000 ;
    DIRECTION INPUT ;
    USE SIGNAL ;
    PORT
      LAYER li1 ;
        RECT 0.715000 1.000000 1.085000 1.315000 ;
    END
  END C2
  PIN Y
    ANTENNADIFFAREA  0.897600 ;
    DIRECTION OUTPUT ;
    USE SIGNAL ;
    PORT
      LAYER li1 ;
        RECT 0.095000 0.255000 0.425000 0.645000 ;
        RECT 0.095000 0.645000 2.645000 0.815000 ;
        RECT 0.095000 1.485000 0.425000 1.500000 ;
        RECT 0.095000 1.500000 1.425000 1.670000 ;
        RECT 0.095000 1.670000 0.425000 1.680000 ;
        RECT 0.095000 1.680000 0.345000 2.255000 ;
        RECT 0.095000 2.255000 0.425000 2.465000 ;
        RECT 1.015000 1.670000 1.185000 1.830000 ;
        RECT 1.255000 0.815000 1.480000 1.330000 ;
        RECT 1.255000 1.330000 1.425000 1.500000 ;
        RECT 2.315000 0.295000 2.645000 0.645000 ;
    END
  END Y
  PIN VGND
    DIRECTION INOUT ;
    SHAPE ABUTMENT ;
    USE GROUND ;
    PORT
      LAYER li1 ;
        RECT 0.000000 -0.085000 3.680000 0.085000 ;
        RECT 0.875000  0.085000 1.605000 0.465000 ;
        RECT 3.255000  0.085000 3.585000 0.815000 ;
    END
    PORT
      LAYER met1 ;
        RECT 0.000000 -0.240000 3.680000 0.240000 ;
    END
  END VGND
  PIN VPWR
    DIRECTION INOUT ;
    SHAPE ABUTMENT ;
    USE POWER ;
    PORT
      LAYER li1 ;
        RECT 0.000000 2.635000 3.680000 2.805000 ;
        RECT 2.775000 1.905000 3.105000 2.075000 ;
        RECT 2.855000 2.075000 3.025000 2.635000 ;
    END
    PORT
      LAYER met1 ;
        RECT 0.000000 2.480000 3.680000 2.960000 ;
    END
  END VPWR
  OBS
    LAYER li1 ;
      RECT 0.515000 1.875000 0.845000 2.075000 ;
      RECT 0.595000 2.075000 0.765000 2.295000 ;
      RECT 0.595000 2.295000 2.185000 2.465000 ;
      RECT 1.515000 1.825000 2.015000 1.965000 ;
      RECT 1.515000 1.965000 1.970000 1.970000 ;
      RECT 1.515000 1.970000 1.935000 1.980000 ;
      RECT 1.515000 1.980000 1.915000 1.995000 ;
      RECT 1.845000 1.655000 3.595000 1.670000 ;
      RECT 1.845000 1.670000 2.685000 1.735000 ;
      RECT 1.845000 1.735000 2.605000 1.825000 ;
      RECT 2.015000 2.135000 2.185000 2.295000 ;
      RECT 2.355000 1.500000 3.595000 1.655000 ;
      RECT 2.355000 1.825000 2.605000 2.255000 ;
      RECT 2.355000 2.255000 2.685000 2.465000 ;
      RECT 3.220000 1.670000 3.595000 1.735000 ;
      RECT 3.255000 2.255000 3.595000 2.465000 ;
      RECT 3.335000 1.735000 3.595000 2.255000 ;
  END
END sky130_fd_sc_hd__a222oi_1
END LIBRARY
# Copyright 2020 The SkyWater PDK Authors
#
# Licensed under the Apache License, Version 2.0 (the "License");
# you may not use this file except in compliance with the License.
# You may obtain a copy of the License at
#
#     https://www.apache.org/licenses/LICENSE-2.0
#
# Unless required by applicable law or agreed to in writing, software
# distributed under the License is distributed on an "AS IS" BASIS,
# WITHOUT WARRANTIES OR CONDITIONS OF ANY KIND, either express or implied.
# See the License for the specific language governing permissions and
# limitations under the License.
#
# SPDX-License-Identifier: Apache-2.0

VERSION 5.5 ;
NAMESCASESENSITIVE ON ;
BUSBITCHARS "[]" ;
DIVIDERCHAR "/" ;
MACRO sky130_fd_sc_hd__a22o_1
  CLASS CORE ;
  SOURCE USER ;
  ORIGIN  0.000000  0.000000 ;
  SIZE  3.220000 BY  2.720000 ;
  SYMMETRY X Y R90 ;
  SITE unithd ;
  PIN A1
    ANTENNAGATEAREA  0.247500 ;
    DIRECTION INPUT ;
    USE SIGNAL ;
    PORT
      LAYER li1 ;
        RECT 1.485000 0.675000 1.695000 1.075000 ;
        RECT 1.485000 1.075000 1.815000 1.285000 ;
    END
  END A1
  PIN A2
    ANTENNAGATEAREA  0.247500 ;
    DIRECTION INPUT ;
    USE SIGNAL ;
    PORT
      LAYER li1 ;
        RECT 1.985000 1.040000 2.395000 1.345000 ;
    END
  END A2
  PIN B1
    ANTENNAGATEAREA  0.247500 ;
    DIRECTION INPUT ;
    USE SIGNAL ;
    PORT
      LAYER li1 ;
        RECT 0.765000 1.075000 1.240000 1.285000 ;
        RECT 1.020000 0.675000 1.240000 1.075000 ;
    END
  END B1
  PIN B2
    ANTENNAGATEAREA  0.247500 ;
    DIRECTION INPUT ;
    USE SIGNAL ;
    PORT
      LAYER li1 ;
        RECT 0.085000 1.075000 0.575000 1.275000 ;
    END
  END B2
  PIN X
    ANTENNADIFFAREA  0.429000 ;
    DIRECTION OUTPUT ;
    USE SIGNAL ;
    PORT
      LAYER li1 ;
        RECT 2.875000 0.255000 3.135000 0.585000 ;
        RECT 2.875000 1.785000 3.135000 2.465000 ;
        RECT 2.965000 0.585000 3.135000 1.785000 ;
    END
  END X
  PIN VGND
    DIRECTION INOUT ;
    SHAPE ABUTMENT ;
    USE GROUND ;
    PORT
      LAYER li1 ;
        RECT 0.000000 -0.085000 3.220000 0.085000 ;
        RECT 0.090000  0.085000 0.545000 0.850000 ;
        RECT 2.375000  0.085000 2.705000 0.445000 ;
    END
    PORT
      LAYER met1 ;
        RECT 0.000000 -0.240000 3.220000 0.240000 ;
    END
  END VGND
  PIN VPWR
    DIRECTION INOUT ;
    SHAPE ABUTMENT ;
    USE POWER ;
    PORT
      LAYER li1 ;
        RECT 0.000000 2.635000 3.220000 2.805000 ;
        RECT 1.430000 2.255000 1.785000 2.635000 ;
        RECT 2.455000 1.855000 2.705000 2.635000 ;
    END
    PORT
      LAYER met1 ;
        RECT 0.000000 2.480000 3.220000 2.960000 ;
    END
  END VPWR
  OBS
    LAYER li1 ;
      RECT 0.090000 1.455000 1.265000 1.515000 ;
      RECT 0.090000 1.515000 2.795000 1.625000 ;
      RECT 0.090000 1.625000 0.345000 2.245000 ;
      RECT 0.090000 2.245000 0.425000 2.465000 ;
      RECT 0.595000 1.795000 0.780000 1.885000 ;
      RECT 0.595000 1.885000 2.205000 2.085000 ;
      RECT 0.595000 2.085000 0.825000 2.125000 ;
      RECT 0.820000 0.255000 2.120000 0.465000 ;
      RECT 0.935000 1.625000 2.735000 1.685000 ;
      RECT 0.935000 1.685000 1.265000 1.715000 ;
      RECT 1.370000 1.875000 2.205000 1.885000 ;
      RECT 1.950000 0.465000 2.120000 0.615000 ;
      RECT 1.950000 0.615000 2.705000 0.740000 ;
      RECT 1.950000 0.740000 2.795000 0.785000 ;
      RECT 1.955000 2.085000 2.205000 2.465000 ;
      RECT 2.525000 0.785000 2.795000 0.905000 ;
      RECT 2.595000 1.480000 2.795000 1.515000 ;
      RECT 2.625000 0.905000 2.795000 1.480000 ;
  END
END sky130_fd_sc_hd__a22o_1
END LIBRARY
# Copyright 2020 The SkyWater PDK Authors
#
# Licensed under the Apache License, Version 2.0 (the "License");
# you may not use this file except in compliance with the License.
# You may obtain a copy of the License at
#
#     https://www.apache.org/licenses/LICENSE-2.0
#
# Unless required by applicable law or agreed to in writing, software
# distributed under the License is distributed on an "AS IS" BASIS,
# WITHOUT WARRANTIES OR CONDITIONS OF ANY KIND, either express or implied.
# See the License for the specific language governing permissions and
# limitations under the License.
#
# SPDX-License-Identifier: Apache-2.0

VERSION 5.5 ;
NAMESCASESENSITIVE ON ;
BUSBITCHARS "[]" ;
DIVIDERCHAR "/" ;
MACRO sky130_fd_sc_hd__a22oi_1
  CLASS CORE ;
  SOURCE USER ;
  ORIGIN  0.000000  0.000000 ;
  SIZE  2.760000 BY  2.720000 ;
  SYMMETRY X Y R90 ;
  SITE unithd ;
  PIN A1
    ANTENNAGATEAREA  0.247500 ;
    DIRECTION INPUT ;
    USE SIGNAL ;
    PORT
      LAYER li1 ;
        RECT 1.490000 0.675000 1.700000 1.075000 ;
        RECT 1.490000 1.075000 1.840000 1.275000 ;
    END
  END A1
  PIN A2
    ANTENNAGATEAREA  0.247500 ;
    DIRECTION INPUT ;
    USE SIGNAL ;
    PORT
      LAYER li1 ;
        RECT 2.010000 0.995000 2.335000 1.325000 ;
    END
  END A2
  PIN B1
    ANTENNAGATEAREA  0.247500 ;
    DIRECTION INPUT ;
    USE SIGNAL ;
    PORT
      LAYER li1 ;
        RECT 0.765000 1.075000 1.240000 1.275000 ;
        RECT 0.990000 0.675000 1.240000 1.075000 ;
    END
  END B1
  PIN B2
    ANTENNAGATEAREA  0.247500 ;
    DIRECTION INPUT ;
    USE SIGNAL ;
    PORT
      LAYER li1 ;
        RECT 0.125000 0.765000 0.575000 1.275000 ;
    END
  END B2
  PIN Y
    ANTENNADIFFAREA  0.858000 ;
    DIRECTION OUTPUT ;
    USE SIGNAL ;
    PORT
      LAYER li1 ;
        RECT 0.095000 1.445000 1.840000 1.495000 ;
        RECT 0.095000 1.495000 2.675000 1.625000 ;
        RECT 0.095000 1.625000 0.425000 2.295000 ;
        RECT 0.095000 2.295000 1.265000 2.465000 ;
        RECT 0.820000 0.255000 2.125000 0.505000 ;
        RECT 0.935000 2.255000 1.265000 2.295000 ;
        RECT 1.615000 1.625000 2.675000 1.665000 ;
        RECT 1.945000 0.505000 2.125000 0.655000 ;
        RECT 1.945000 0.655000 2.675000 0.825000 ;
        RECT 2.505000 0.825000 2.675000 1.495000 ;
    END
  END Y
  PIN VGND
    DIRECTION INOUT ;
    SHAPE ABUTMENT ;
    USE GROUND ;
    PORT
      LAYER li1 ;
        RECT 0.000000 -0.085000 2.760000 0.085000 ;
        RECT 0.095000  0.085000 0.545000 0.595000 ;
        RECT 2.305000  0.085000 2.635000 0.485000 ;
    END
    PORT
      LAYER met1 ;
        RECT 0.000000 -0.240000 2.760000 0.240000 ;
    END
  END VGND
  PIN VPWR
    DIRECTION INOUT ;
    SHAPE ABUTMENT ;
    USE POWER ;
    PORT
      LAYER li1 ;
        RECT 0.000000 2.635000 2.760000 2.805000 ;
        RECT 1.435000 2.255000 1.810000 2.635000 ;
        RECT 2.360000 1.855000 2.625000 2.635000 ;
    END
    PORT
      LAYER met1 ;
        RECT 0.000000 2.480000 2.760000 2.960000 ;
    END
  END VPWR
  OBS
    LAYER li1 ;
      RECT 0.595000 1.795000 1.475000 1.835000 ;
      RECT 0.595000 1.835000 2.125000 2.035000 ;
      RECT 0.595000 2.035000 1.210000 2.085000 ;
      RECT 0.595000 2.085000 0.825000 2.125000 ;
      RECT 1.955000 2.035000 2.125000 2.165000 ;
  END
END sky130_fd_sc_hd__a22oi_1
END LIBRARY
# Copyright 2020 The SkyWater PDK Authors
#
# Licensed under the Apache License, Version 2.0 (the "License");
# you may not use this file except in compliance with the License.
# You may obtain a copy of the License at
#
#     https://www.apache.org/licenses/LICENSE-2.0
#
# Unless required by applicable law or agreed to in writing, software
# distributed under the License is distributed on an "AS IS" BASIS,
# WITHOUT WARRANTIES OR CONDITIONS OF ANY KIND, either express or implied.
# See the License for the specific language governing permissions and
# limitations under the License.
#
# SPDX-License-Identifier: Apache-2.0

VERSION 5.5 ;
NAMESCASESENSITIVE ON ;
BUSBITCHARS "[]" ;
DIVIDERCHAR "/" ;
MACRO sky130_fd_sc_hd__a31oi_1
  CLASS CORE ;
  SOURCE USER ;
  ORIGIN  0.000000  0.000000 ;
  SIZE  2.300000 BY  2.720000 ;
  SYMMETRY X Y R90 ;
  SITE unithd ;
  PIN A1
    ANTENNAGATEAREA  0.247500 ;
    DIRECTION INPUT ;
    USE SIGNAL ;
    PORT
      LAYER li1 ;
        RECT 1.070000 1.445000 1.455000 1.665000 ;
        RECT 1.270000 0.995000 1.455000 1.445000 ;
    END
  END A1
  PIN A2
    ANTENNAGATEAREA  0.247500 ;
    DIRECTION INPUT ;
    USE SIGNAL ;
    PORT
      LAYER li1 ;
        RECT 0.610000 0.335000 1.055000 1.275000 ;
    END
  END A2
  PIN A3
    ANTENNAGATEAREA  0.247500 ;
    DIRECTION INPUT ;
    USE SIGNAL ;
    PORT
      LAYER li1 ;
        RECT 0.085000 0.995000 0.365000 1.325000 ;
    END
  END A3
  PIN B1
    ANTENNAGATEAREA  0.247500 ;
    DIRECTION INPUT ;
    USE SIGNAL ;
    PORT
      LAYER li1 ;
        RECT 1.965000 0.995000 2.215000 1.325000 ;
    END
  END B1
  PIN Y
    ANTENNADIFFAREA  0.481250 ;
    DIRECTION OUTPUT ;
    USE SIGNAL ;
    PORT
      LAYER li1 ;
        RECT 1.380000 0.295000 1.785000 0.715000 ;
        RECT 1.380000 0.715000 1.795000 0.825000 ;
        RECT 1.625000 0.825000 1.795000 1.495000 ;
        RECT 1.625000 1.495000 2.210000 1.665000 ;
        RECT 1.875000 1.665000 2.210000 2.445000 ;
    END
  END Y
  PIN VGND
    DIRECTION INOUT ;
    SHAPE ABUTMENT ;
    USE GROUND ;
    PORT
      LAYER li1 ;
        RECT 0.000000 -0.085000 2.300000 0.085000 ;
        RECT 0.090000  0.085000 0.430000 0.815000 ;
        RECT 1.955000  0.085000 2.215000 0.565000 ;
    END
    PORT
      LAYER met1 ;
        RECT 0.000000 -0.240000 2.300000 0.240000 ;
    END
  END VGND
  PIN VPWR
    DIRECTION INOUT ;
    SHAPE ABUTMENT ;
    USE POWER ;
    PORT
      LAYER li1 ;
        RECT 0.000000 2.635000 2.300000 2.805000 ;
        RECT 0.090000 1.495000 0.420000 2.635000 ;
        RECT 0.935000 2.175000 1.265000 2.635000 ;
    END
    PORT
      LAYER met1 ;
        RECT 0.000000 2.480000 2.300000 2.960000 ;
    END
  END VPWR
  OBS
    LAYER li1 ;
      RECT 0.590000 1.835000 1.695000 2.005000 ;
      RECT 0.590000 2.005000 0.765000 2.415000 ;
      RECT 1.470000 2.005000 1.695000 2.415000 ;
  END
END sky130_fd_sc_hd__a31oi_1
END LIBRARY
# Copyright 2020 The SkyWater PDK Authors
#
# Licensed under the Apache License, Version 2.0 (the "License");
# you may not use this file except in compliance with the License.
# You may obtain a copy of the License at
#
#     https://www.apache.org/licenses/LICENSE-2.0
#
# Unless required by applicable law or agreed to in writing, software
# distributed under the License is distributed on an "AS IS" BASIS,
# WITHOUT WARRANTIES OR CONDITIONS OF ANY KIND, either express or implied.
# See the License for the specific language governing permissions and
# limitations under the License.
#
# SPDX-License-Identifier: Apache-2.0

VERSION 5.5 ;
NAMESCASESENSITIVE ON ;
BUSBITCHARS "[]" ;
DIVIDERCHAR "/" ;
MACRO sky130_fd_sc_hd__a32oi_1
  CLASS CORE ;
  SOURCE USER ;
  ORIGIN  0.000000  0.000000 ;
  SIZE  3.220000 BY  2.720000 ;
  SYMMETRY X Y R90 ;
  SITE unithd ;
  PIN A1
    ANTENNAGATEAREA  0.247500 ;
    DIRECTION INPUT ;
    USE SIGNAL ;
    PORT
      LAYER li1 ;
        RECT 1.230000 1.075000 1.595000 1.255000 ;
        RECT 1.405000 0.345000 1.705000 0.765000 ;
        RECT 1.405000 0.765000 1.595000 1.075000 ;
    END
  END A1
  PIN A2
    ANTENNAGATEAREA  0.247500 ;
    DIRECTION INPUT ;
    USE SIGNAL ;
    PORT
      LAYER li1 ;
        RECT 1.805000 0.995000 2.165000 1.325000 ;
        RECT 1.965000 0.415000 2.165000 0.995000 ;
    END
  END A2
  PIN A3
    ANTENNAGATEAREA  0.247500 ;
    DIRECTION INPUT ;
    USE SIGNAL ;
    PORT
      LAYER li1 ;
        RECT 2.335000 1.015000 2.750000 1.325000 ;
    END
  END A3
  PIN B1
    ANTENNAGATEAREA  0.247500 ;
    DIRECTION INPUT ;
    USE SIGNAL ;
    PORT
      LAYER li1 ;
        RECT 0.855000 0.995000 1.025000 1.425000 ;
        RECT 0.855000 1.425000 1.255000 1.615000 ;
    END
  END B1
  PIN B2
    ANTENNAGATEAREA  0.247500 ;
    DIRECTION INPUT ;
    USE SIGNAL ;
    PORT
      LAYER li1 ;
        RECT 0.085000 0.995000 0.345000 1.325000 ;
    END
  END B2
  PIN Y
    ANTENNADIFFAREA  0.575500 ;
    DIRECTION OUTPUT ;
    USE SIGNAL ;
    PORT
      LAYER li1 ;
        RECT 0.515000 0.635000 1.165000 0.805000 ;
        RECT 0.515000 0.805000 0.685000 1.785000 ;
        RECT 0.515000 1.785000 0.865000 2.085000 ;
        RECT 0.915000 0.295000 1.165000 0.635000 ;
    END
  END Y
  PIN VGND
    DIRECTION INOUT ;
    SHAPE ABUTMENT ;
    USE GROUND ;
    PORT
      LAYER li1 ;
        RECT 0.000000 -0.085000 3.220000 0.085000 ;
        RECT 0.095000  0.085000 0.425000 0.465000 ;
        RECT 2.355000  0.085000 2.695000 0.805000 ;
    END
    PORT
      LAYER met1 ;
        RECT 0.000000 -0.240000 3.220000 0.240000 ;
    END
  END VGND
  PIN VPWR
    DIRECTION INOUT ;
    SHAPE ABUTMENT ;
    USE POWER ;
    PORT
      LAYER li1 ;
        RECT 0.000000 2.635000 3.220000 2.805000 ;
        RECT 1.555000 2.135000 1.805000 2.635000 ;
        RECT 2.355000 1.495000 2.695000 2.635000 ;
    END
    PORT
      LAYER met1 ;
        RECT 0.000000 2.480000 3.220000 2.960000 ;
    END
  END VPWR
  OBS
    LAYER li1 ;
      RECT 0.085000 1.835000 0.345000 2.255000 ;
      RECT 0.085000 2.255000 1.345000 2.465000 ;
      RECT 1.095000 1.785000 2.185000 1.955000 ;
      RECT 1.095000 1.955000 1.345000 2.255000 ;
      RECT 2.015000 1.745000 2.185000 1.785000 ;
      RECT 2.015000 1.955000 2.185000 2.465000 ;
  END
END sky130_fd_sc_hd__a32oi_1
END LIBRARY
# Copyright 2020 The SkyWater PDK Authors
#
# Licensed under the Apache License, Version 2.0 (the "License");
# you may not use this file except in compliance with the License.
# You may obtain a copy of the License at
#
#     https://www.apache.org/licenses/LICENSE-2.0
#
# Unless required by applicable law or agreed to in writing, software
# distributed under the License is distributed on an "AS IS" BASIS,
# WITHOUT WARRANTIES OR CONDITIONS OF ANY KIND, either express or implied.
# See the License for the specific language governing permissions and
# limitations under the License.
#
# SPDX-License-Identifier: Apache-2.0

VERSION 5.5 ;
NAMESCASESENSITIVE ON ;
BUSBITCHARS "[]" ;
DIVIDERCHAR "/" ;
MACRO sky130_fd_sc_hd__a41oi_1
  CLASS CORE ;
  SOURCE USER ;
  ORIGIN  0.000000  0.000000 ;
  SIZE  3.220000 BY  2.720000 ;
  SYMMETRY X Y R90 ;
  SITE unithd ;
  PIN A1
    ANTENNAGATEAREA  0.247500 ;
    DIRECTION INPUT ;
    USE SIGNAL ;
    PORT
      LAYER li1 ;
        RECT 2.780000 0.995000 3.085000 1.615000 ;
    END
  END A1
  PIN A2
    ANTENNAGATEAREA  0.247500 ;
    DIRECTION INPUT ;
    USE SIGNAL ;
    PORT
      LAYER li1 ;
        RECT 1.890000 0.755000 2.210000 1.665000 ;
    END
  END A2
  PIN A3
    ANTENNAGATEAREA  0.247500 ;
    DIRECTION INPUT ;
    USE SIGNAL ;
    PORT
      LAYER li1 ;
        RECT 1.470000 0.755000 1.710000 1.665000 ;
    END
  END A3
  PIN A4
    ANTENNAGATEAREA  0.247500 ;
    DIRECTION INPUT ;
    USE SIGNAL ;
    PORT
      LAYER li1 ;
        RECT 0.960000 0.965000 1.250000 1.665000 ;
    END
  END A4
  PIN B1
    ANTENNAGATEAREA  0.247500 ;
    DIRECTION INPUT ;
    USE SIGNAL ;
    PORT
      LAYER li1 ;
        RECT 0.540000 0.965000 0.780000 1.665000 ;
    END
  END B1
  PIN Y
    ANTENNADIFFAREA  0.669500 ;
    DIRECTION OUTPUT ;
    USE SIGNAL ;
    PORT
      LAYER li1 ;
        RECT 0.090000 0.285000 0.345000 0.615000 ;
        RECT 0.090000 0.615000 1.290000 0.785000 ;
        RECT 0.090000 0.785000 0.360000 1.845000 ;
        RECT 0.090000 1.845000 0.425000 2.425000 ;
        RECT 1.120000 0.295000 3.015000 0.465000 ;
        RECT 1.120000 0.465000 1.290000 0.615000 ;
        RECT 2.685000 0.465000 3.015000 0.805000 ;
    END
  END Y
  PIN VGND
    DIRECTION INOUT ;
    SHAPE ABUTMENT ;
    USE GROUND ;
    PORT
      LAYER li1 ;
        RECT 0.000000 -0.085000 3.220000 0.085000 ;
        RECT 0.620000  0.085000 0.950000 0.445000 ;
    END
    PORT
      LAYER met1 ;
        RECT 0.000000 -0.240000 3.220000 0.240000 ;
    END
  END VGND
  PIN VPWR
    DIRECTION INOUT ;
    SHAPE ABUTMENT ;
    USE POWER ;
    PORT
      LAYER li1 ;
        RECT 0.000000 2.635000 3.220000 2.805000 ;
        RECT 1.120000 2.195000 1.450000 2.635000 ;
        RECT 2.215000 2.195000 2.545000 2.635000 ;
    END
    PORT
      LAYER met1 ;
        RECT 0.000000 2.480000 3.220000 2.960000 ;
    END
  END VPWR
  OBS
    LAYER li1 ;
      RECT 0.595000 1.845000 3.015000 2.015000 ;
      RECT 0.595000 2.015000 0.845000 2.465000 ;
      RECT 1.760000 2.015000 1.930000 2.465000 ;
      RECT 2.765000 2.015000 3.015000 2.465000 ;
  END
END sky130_fd_sc_hd__a41oi_1
END LIBRARY
# Copyright 2020 The SkyWater PDK Authors
#
# Licensed under the Apache License, Version 2.0 (the "License");
# you may not use this file except in compliance with the License.
# You may obtain a copy of the License at
#
#     https://www.apache.org/licenses/LICENSE-2.0
#
# Unless required by applicable law or agreed to in writing, software
# distributed under the License is distributed on an "AS IS" BASIS,
# WITHOUT WARRANTIES OR CONDITIONS OF ANY KIND, either express or implied.
# See the License for the specific language governing permissions and
# limitations under the License.
#
# SPDX-License-Identifier: Apache-2.0

VERSION 5.5 ;
NAMESCASESENSITIVE ON ;
BUSBITCHARS "[]" ;
DIVIDERCHAR "/" ;
MACRO sky130_fd_sc_hd__and2_0
  CLASS CORE ;
  SOURCE USER ;
  ORIGIN  0.000000  0.000000 ;
  SIZE  2.300000 BY  2.720000 ;
  SYMMETRY X Y R90 ;
  SITE unithd ;
  PIN A
    ANTENNAGATEAREA  0.126000 ;
    DIRECTION INPUT ;
    USE SIGNAL ;
    PORT
      LAYER li1 ;
        RECT 0.085000 1.185000 0.430000 1.955000 ;
    END
  END A
  PIN B
    ANTENNAGATEAREA  0.126000 ;
    DIRECTION INPUT ;
    USE SIGNAL ;
    PORT
      LAYER li1 ;
        RECT 0.940000 1.080000 1.270000 1.615000 ;
    END
  END B
  PIN X
    ANTENNADIFFAREA  0.280900 ;
    DIRECTION OUTPUT ;
    USE SIGNAL ;
    PORT
      LAYER li1 ;
        RECT 1.560000 0.255000 2.215000 0.525000 ;
        RECT 1.790000 1.835000 2.215000 2.465000 ;
        RECT 1.950000 0.525000 2.215000 1.835000 ;
    END
  END X
  PIN VGND
    DIRECTION INOUT ;
    SHAPE ABUTMENT ;
    USE GROUND ;
    PORT
      LAYER li1 ;
        RECT 0.000000 -0.085000 2.300000 0.085000 ;
        RECT 0.950000  0.085000 1.390000 0.525000 ;
    END
    PORT
      LAYER met1 ;
        RECT 0.000000 -0.240000 2.300000 0.240000 ;
    END
  END VGND
  PIN VPWR
    DIRECTION INOUT ;
    SHAPE ABUTMENT ;
    USE POWER ;
    PORT
      LAYER li1 ;
        RECT 0.000000 2.635000 2.300000 2.805000 ;
        RECT 0.160000 2.175000 0.430000 2.635000 ;
        RECT 1.110000 1.835000 1.620000 2.635000 ;
    END
    PORT
      LAYER met1 ;
        RECT 0.000000 2.480000 2.300000 2.960000 ;
    END
  END VPWR
  OBS
    LAYER li1 ;
      RECT 0.185000 0.280000 0.490000 0.695000 ;
      RECT 0.185000 0.695000 1.780000 0.910000 ;
      RECT 0.185000 0.910000 0.770000 0.950000 ;
      RECT 0.600000 0.950000 0.770000 2.135000 ;
      RECT 0.600000 2.135000 0.865000 2.465000 ;
      RECT 1.450000 0.910000 1.780000 1.435000 ;
  END
END sky130_fd_sc_hd__and2_0
END LIBRARY
# Copyright 2020 The SkyWater PDK Authors
#
# Licensed under the Apache License, Version 2.0 (the "License");
# you may not use this file except in compliance with the License.
# You may obtain a copy of the License at
#
#     https://www.apache.org/licenses/LICENSE-2.0
#
# Unless required by applicable law or agreed to in writing, software
# distributed under the License is distributed on an "AS IS" BASIS,
# WITHOUT WARRANTIES OR CONDITIONS OF ANY KIND, either express or implied.
# See the License for the specific language governing permissions and
# limitations under the License.
#
# SPDX-License-Identifier: Apache-2.0

VERSION 5.5 ;
NAMESCASESENSITIVE ON ;
BUSBITCHARS "[]" ;
DIVIDERCHAR "/" ;
MACRO sky130_fd_sc_hd__and3_1
  CLASS CORE ;
  SOURCE USER ;
  ORIGIN  0.000000  0.000000 ;
  SIZE  2.300000 BY  2.720000 ;
  SYMMETRY X Y R90 ;
  SITE unithd ;
  PIN A
    ANTENNAGATEAREA  0.126000 ;
    DIRECTION INPUT ;
    USE SIGNAL ;
    PORT
      LAYER li1 ;
        RECT 0.085000 0.635000 0.635000 1.020000 ;
    END
  END A
  PIN B
    ANTENNAGATEAREA  0.126000 ;
    DIRECTION INPUT ;
    USE SIGNAL ;
    PORT
      LAYER li1 ;
        RECT 0.865000 2.125000 1.345000 2.465000 ;
    END
  END B
  PIN C
    ANTENNAGATEAREA  0.126000 ;
    DIRECTION INPUT ;
    USE SIGNAL ;
    PORT
      LAYER li1 ;
        RECT 1.145000 0.305000 1.365000 0.790000 ;
        RECT 1.145000 0.790000 1.475000 1.215000 ;
    END
  END C
  PIN X
    ANTENNADIFFAREA  0.429000 ;
    DIRECTION OUTPUT ;
    USE SIGNAL ;
    PORT
      LAYER li1 ;
        RECT 1.940000 1.765000 2.215000 2.465000 ;
        RECT 1.955000 0.255000 2.215000 0.735000 ;
        RECT 2.045000 0.735000 2.215000 1.765000 ;
    END
  END X
  PIN VGND
    DIRECTION INOUT ;
    SHAPE ABUTMENT ;
    USE GROUND ;
    PORT
      LAYER li1 ;
        RECT 0.000000 -0.085000 2.300000 0.085000 ;
        RECT 1.535000  0.085000 1.785000 0.625000 ;
    END
    PORT
      LAYER met1 ;
        RECT 0.000000 -0.240000 2.300000 0.240000 ;
    END
  END VGND
  PIN VPWR
    DIRECTION INOUT ;
    SHAPE ABUTMENT ;
    USE POWER ;
    PORT
      LAYER li1 ;
        RECT 0.000000 2.635000 2.300000 2.805000 ;
        RECT 0.085000 1.980000 0.700000 2.080000 ;
        RECT 0.085000 2.080000 0.690000 2.635000 ;
        RECT 0.515000 1.710000 0.845000 1.955000 ;
        RECT 0.515000 1.955000 0.700000 1.980000 ;
        RECT 1.515000 2.090000 1.770000 2.635000 ;
    END
    PORT
      LAYER met1 ;
        RECT 0.000000 2.480000 2.300000 2.960000 ;
    END
  END VPWR
  OBS
    LAYER li1 ;
      RECT 0.085000 0.295000 0.975000 0.465000 ;
      RECT 0.085000 1.190000 0.975000 1.260000 ;
      RECT 0.085000 1.260000 0.980000 1.285000 ;
      RECT 0.085000 1.285000 0.990000 1.300000 ;
      RECT 0.085000 1.300000 0.995000 1.315000 ;
      RECT 0.085000 1.315000 1.005000 1.320000 ;
      RECT 0.085000 1.320000 1.010000 1.330000 ;
      RECT 0.085000 1.330000 1.015000 1.340000 ;
      RECT 0.085000 1.340000 1.025000 1.345000 ;
      RECT 0.085000 1.345000 1.035000 1.355000 ;
      RECT 0.085000 1.355000 1.045000 1.360000 ;
      RECT 0.085000 1.360000 0.345000 1.810000 ;
      RECT 0.710000 1.360000 1.045000 1.365000 ;
      RECT 0.710000 1.365000 1.060000 1.370000 ;
      RECT 0.710000 1.370000 1.075000 1.380000 ;
      RECT 0.710000 1.380000 1.100000 1.385000 ;
      RECT 0.710000 1.385000 1.875000 1.390000 ;
      RECT 0.740000 1.390000 1.875000 1.425000 ;
      RECT 0.775000 1.425000 1.875000 1.450000 ;
      RECT 0.805000 0.465000 0.975000 1.190000 ;
      RECT 0.805000 1.450000 1.875000 1.480000 ;
      RECT 0.825000 1.480000 1.875000 1.510000 ;
      RECT 0.845000 1.510000 1.875000 1.540000 ;
      RECT 0.915000 1.540000 1.875000 1.550000 ;
      RECT 0.940000 1.550000 1.875000 1.560000 ;
      RECT 0.960000 1.560000 1.875000 1.575000 ;
      RECT 0.980000 1.575000 1.875000 1.590000 ;
      RECT 0.985000 1.590000 1.770000 1.600000 ;
      RECT 1.000000 1.600000 1.770000 1.635000 ;
      RECT 1.015000 1.635000 1.770000 1.885000 ;
      RECT 1.645000 0.990000 1.875000 1.385000 ;
  END
END sky130_fd_sc_hd__and3_1
END LIBRARY
# Copyright 2020 The SkyWater PDK Authors
#
# Licensed under the Apache License, Version 2.0 (the "License");
# you may not use this file except in compliance with the License.
# You may obtain a copy of the License at
#
#     https://www.apache.org/licenses/LICENSE-2.0
#
# Unless required by applicable law or agreed to in writing, software
# distributed under the License is distributed on an "AS IS" BASIS,
# WITHOUT WARRANTIES OR CONDITIONS OF ANY KIND, either express or implied.
# See the License for the specific language governing permissions and
# limitations under the License.
#
# SPDX-License-Identifier: Apache-2.0

VERSION 5.5 ;
NAMESCASESENSITIVE ON ;
BUSBITCHARS "[]" ;
DIVIDERCHAR "/" ;
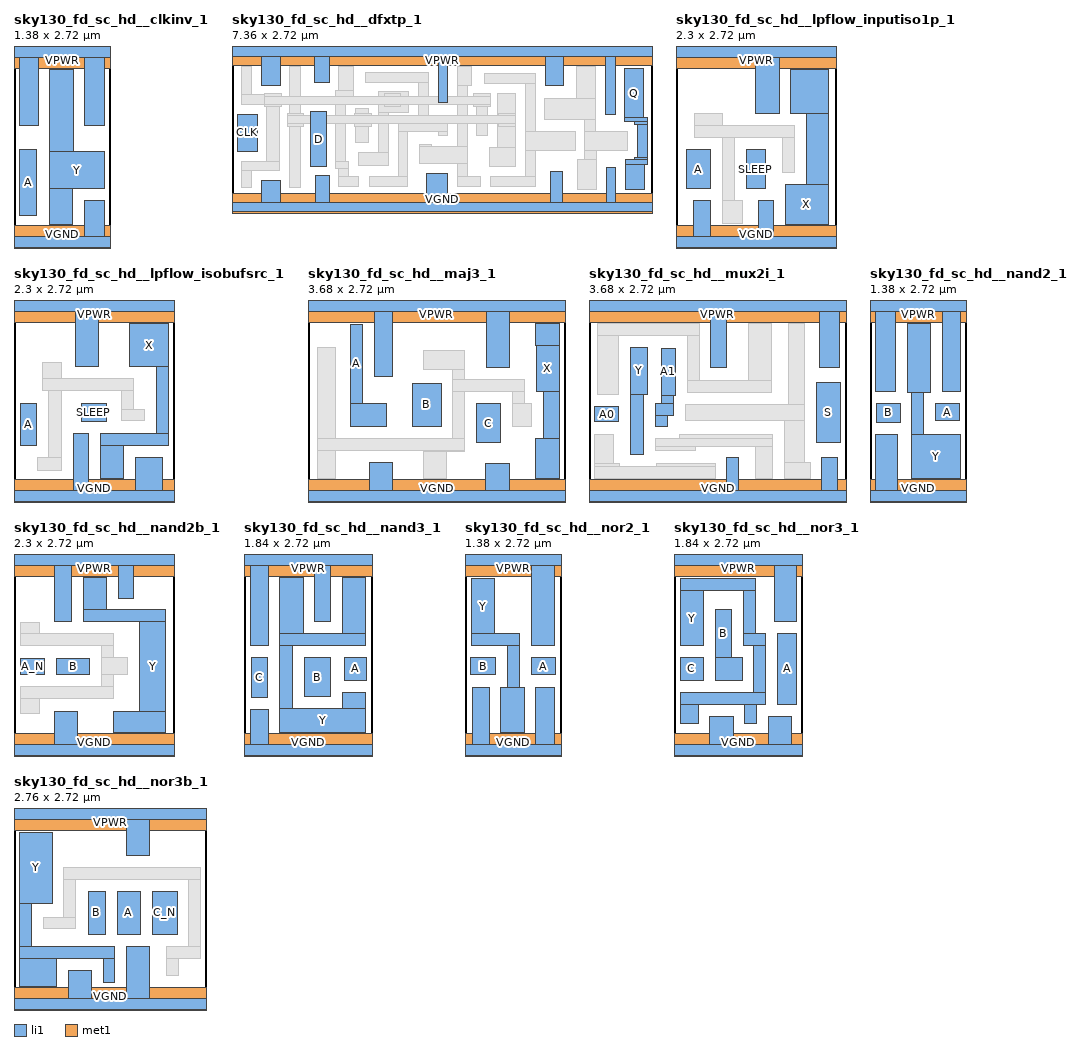
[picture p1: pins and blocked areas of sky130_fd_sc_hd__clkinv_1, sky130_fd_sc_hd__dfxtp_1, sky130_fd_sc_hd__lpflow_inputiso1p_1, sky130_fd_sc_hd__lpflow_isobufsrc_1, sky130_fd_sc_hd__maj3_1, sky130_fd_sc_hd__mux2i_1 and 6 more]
MACRO sky130_fd_sc_hd__clkinv_1
  CLASS CORE ;
  SOURCE USER ;
  ORIGIN  0.000000  0.000000 ;
  SIZE  1.380000 BY  2.720000 ;
  SYMMETRY X Y R90 ;
  SITE unithd ;
  PIN A
    ANTENNAGATEAREA  0.315000 ;
    DIRECTION INPUT ;
    USE SIGNAL ;
    PORT
      LAYER li1 ;
        RECT 0.085000 0.375000 0.325000 1.325000 ;
    END
  END A
  PIN Y
    ANTENNADIFFAREA  0.336000 ;
    DIRECTION OUTPUT ;
    USE SIGNAL ;
    PORT
      LAYER li1 ;
        RECT 0.515000 0.255000 0.840000 0.760000 ;
        RECT 0.515000 0.760000 1.295000 1.290000 ;
        RECT 0.515000 1.290000 0.845000 2.465000 ;
    END
  END Y
  PIN VGND
    DIRECTION INOUT ;
    SHAPE ABUTMENT ;
    USE GROUND ;
    PORT
      LAYER li1 ;
        RECT 0.000000 -0.085000 1.380000 0.085000 ;
        RECT 1.010000  0.085000 1.295000 0.590000 ;
    END
    PORT
      LAYER met1 ;
        RECT 0.000000 -0.240000 1.380000 0.240000 ;
    END
  END VGND
  PIN VPWR
    DIRECTION INOUT ;
    SHAPE ABUTMENT ;
    USE POWER ;
    PORT
      LAYER li1 ;
        RECT 0.000000 2.635000 1.380000 2.805000 ;
        RECT 0.085000 1.665000 0.345000 2.635000 ;
        RECT 1.015000 1.665000 1.295000 2.635000 ;
    END
    PORT
      LAYER met1 ;
        RECT 0.000000 2.480000 1.380000 2.960000 ;
    END
  END VPWR
  OBS
  END
END sky130_fd_sc_hd__clkinv_1
END LIBRARY
# Copyright 2020 The SkyWater PDK Authors
#
# Licensed under the Apache License, Version 2.0 (the "License");
# you may not use this file except in compliance with the License.
# You may obtain a copy of the License at
#
#     https://www.apache.org/licenses/LICENSE-2.0
#
# Unless required by applicable law or agreed to in writing, software
# distributed under the License is distributed on an "AS IS" BASIS,
# WITHOUT WARRANTIES OR CONDITIONS OF ANY KIND, either express or implied.
# See the License for the specific language governing permissions and
# limitations under the License.
#
# SPDX-License-Identifier: Apache-2.0

VERSION 5.5 ;
NAMESCASESENSITIVE ON ;
BUSBITCHARS "[]" ;
DIVIDERCHAR "/" ;
MACRO sky130_fd_sc_hd__dfxtp_1
  CLASS CORE ;
  SOURCE USER ;
  ORIGIN  0.000000  0.000000 ;
  SIZE  7.360000 BY  2.720000 ;
  SYMMETRY X Y R90 ;
  SITE unithd ;
  PIN D
    ANTENNAGATEAREA  0.126000 ;
    DIRECTION INPUT ;
    USE SIGNAL ;
    PORT
      LAYER li1 ;
        RECT 1.370000 0.715000 1.650000 1.665000 ;
    END
  END D
  PIN Q
    ANTENNADIFFAREA  0.429000 ;
    DIRECTION OUTPUT ;
    USE SIGNAL ;
    PORT
      LAYER li1 ;
        RECT 6.885000 1.495000 7.275000 1.575000 ;
        RECT 6.885000 1.575000 7.215000 2.420000 ;
        RECT 6.895000 0.305000 7.225000 0.740000 ;
        RECT 6.895000 0.740000 7.275000 0.825000 ;
        RECT 7.050000 0.825000 7.275000 0.865000 ;
        RECT 7.060000 1.445000 7.275000 1.495000 ;
        RECT 7.105000 0.865000 7.275000 1.445000 ;
    END
  END Q
  PIN CLK
    ANTENNAGATEAREA  0.159000 ;
    DIRECTION INPUT ;
    USE CLOCK ;
    PORT
      LAYER li1 ;
        RECT 0.090000 0.975000 0.440000 1.625000 ;
    END
  END CLK
  PIN VGND
    DIRECTION INOUT ;
    SHAPE ABUTMENT ;
    USE GROUND ;
    PORT
      LAYER li1 ;
        RECT 0.000000 -0.085000 7.360000 0.085000 ;
        RECT 0.515000  0.085000 0.845000 0.465000 ;
        RECT 1.455000  0.085000 1.705000 0.545000 ;
        RECT 3.400000  0.085000 3.770000 0.585000 ;
        RECT 5.585000  0.085000 5.795000 0.615000 ;
        RECT 6.555000  0.085000 6.725000 0.695000 ;
    END
    PORT
      LAYER met1 ;
        RECT 0.000000 -0.240000 7.360000 0.240000 ;
    END
  END VGND
  PIN VPWR
    DIRECTION INOUT ;
    SHAPE ABUTMENT ;
    USE POWER ;
    PORT
      LAYER li1 ;
        RECT 0.000000 2.635000 7.360000 2.805000 ;
        RECT 0.515000 2.135000 0.845000 2.635000 ;
        RECT 1.440000 2.175000 1.705000 2.635000 ;
        RECT 3.610000 1.835000 3.780000 2.635000 ;
        RECT 5.490000 2.135000 5.805000 2.635000 ;
        RECT 6.545000 1.625000 6.715000 2.635000 ;
    END
    PORT
      LAYER met1 ;
        RECT 0.000000 2.480000 7.360000 2.960000 ;
    END
  END VPWR
  OBS
    LAYER li1 ;
      RECT 0.175000 0.345000 0.345000 0.635000 ;
      RECT 0.175000 0.635000 0.840000 0.805000 ;
      RECT 0.175000 1.795000 0.840000 1.965000 ;
      RECT 0.175000 1.965000 0.345000 2.465000 ;
      RECT 0.610000 0.805000 0.840000 1.795000 ;
      RECT 1.015000 0.345000 1.200000 2.465000 ;
      RECT 1.820000 0.675000 2.045000 0.805000 ;
      RECT 1.820000 0.805000 1.990000 1.910000 ;
      RECT 1.820000 1.910000 2.125000 2.040000 ;
      RECT 1.875000 0.365000 2.210000 0.535000 ;
      RECT 1.875000 0.535000 2.045000 0.675000 ;
      RECT 1.875000 2.040000 2.125000 2.465000 ;
      RECT 2.160000 1.125000 2.400000 1.720000 ;
      RECT 2.215000 0.735000 2.740000 0.955000 ;
      RECT 2.335000 2.190000 3.440000 2.360000 ;
      RECT 2.405000 0.365000 3.080000 0.535000 ;
      RECT 2.570000 0.955000 2.740000 1.655000 ;
      RECT 2.570000 1.655000 3.100000 2.020000 ;
      RECT 2.910000 0.535000 3.080000 1.315000 ;
      RECT 2.910000 1.315000 3.780000 1.485000 ;
      RECT 3.270000 1.485000 3.780000 1.575000 ;
      RECT 3.270000 1.575000 3.440000 2.190000 ;
      RECT 3.290000 0.765000 4.120000 1.065000 ;
      RECT 3.290000 1.065000 3.490000 1.095000 ;
      RECT 3.610000 1.245000 3.780000 1.315000 ;
      RECT 3.950000 0.365000 4.355000 0.535000 ;
      RECT 3.950000 0.535000 4.120000 0.765000 ;
      RECT 3.950000 1.065000 4.120000 2.135000 ;
      RECT 3.950000 2.135000 4.200000 2.465000 ;
      RECT 4.290000 1.245000 4.480000 1.965000 ;
      RECT 4.425000 2.165000 5.310000 2.335000 ;
      RECT 4.505000 0.705000 4.970000 1.035000 ;
      RECT 4.525000 0.365000 5.310000 0.535000 ;
      RECT 4.650000 1.035000 4.970000 1.995000 ;
      RECT 5.140000 0.535000 5.310000 0.995000 ;
      RECT 5.140000 0.995000 6.015000 1.325000 ;
      RECT 5.140000 1.325000 5.310000 2.165000 ;
      RECT 5.480000 1.530000 6.375000 1.905000 ;
      RECT 6.035000 1.905000 6.375000 2.465000 ;
      RECT 6.055000 0.300000 6.385000 0.825000 ;
      RECT 6.185000 0.825000 6.385000 0.995000 ;
      RECT 6.185000 0.995000 6.935000 1.325000 ;
      RECT 6.185000 1.325000 6.375000 1.530000 ;
    LAYER mcon ;
      RECT 0.630000 1.785000 0.800000 1.955000 ;
      RECT 1.025000 1.445000 1.195000 1.615000 ;
      RECT 2.215000 1.445000 2.385000 1.615000 ;
      RECT 2.730000 1.785000 2.900000 1.955000 ;
      RECT 4.300000 1.785000 4.470000 1.955000 ;
      RECT 4.735000 1.445000 4.905000 1.615000 ;
    LAYER met1 ;
      RECT 0.570000 1.755000 0.860000 1.800000 ;
      RECT 0.570000 1.800000 4.530000 1.940000 ;
      RECT 0.570000 1.940000 0.860000 1.985000 ;
      RECT 0.965000 1.415000 1.255000 1.460000 ;
      RECT 0.965000 1.460000 4.965000 1.600000 ;
      RECT 0.965000 1.600000 1.255000 1.645000 ;
      RECT 2.155000 1.415000 2.445000 1.460000 ;
      RECT 2.155000 1.600000 2.445000 1.645000 ;
      RECT 2.670000 1.755000 2.960000 1.800000 ;
      RECT 2.670000 1.940000 2.960000 1.985000 ;
      RECT 4.240000 1.755000 4.530000 1.800000 ;
      RECT 4.240000 1.940000 4.530000 1.985000 ;
      RECT 4.675000 1.415000 4.965000 1.460000 ;
      RECT 4.675000 1.600000 4.965000 1.645000 ;
  END
END sky130_fd_sc_hd__dfxtp_1
END LIBRARY
# Copyright 2020 The SkyWater PDK Authors
#
# Licensed under the Apache License, Version 2.0 (the "License");
# you may not use this file except in compliance with the License.
# You may obtain a copy of the License at
#
#     https://www.apache.org/licenses/LICENSE-2.0
#
# Unless required by applicable law or agreed to in writing, software
# distributed under the License is distributed on an "AS IS" BASIS,
# WITHOUT WARRANTIES OR CONDITIONS OF ANY KIND, either express or implied.
# See the License for the specific language governing permissions and
# limitations under the License.
#
# SPDX-License-Identifier: Apache-2.0

VERSION 5.5 ;
NAMESCASESENSITIVE ON ;
BUSBITCHARS "[]" ;
DIVIDERCHAR "/" ;
MACRO sky130_fd_sc_hd__lpflow_inputiso1p_1
  CLASS CORE ;
  SOURCE USER ;
  ORIGIN  0.000000  0.000000 ;
  SIZE  2.300000 BY  2.720000 ;
  SYMMETRY X Y R90 ;
  SITE unithd ;
  PIN A
    ANTENNAGATEAREA  0.126000 ;
    DIRECTION INPUT ;
    USE SIGNAL ;
    PORT
      LAYER li1 ;
        RECT 0.145000 0.765000 0.500000 1.325000 ;
    END
  END A
  PIN SLEEP
    ANTENNAGATEAREA  0.126000 ;
    DIRECTION INPUT ;
    USE SIGNAL ;
    PORT
      LAYER li1 ;
        RECT 1.010000 0.765000 1.275000 1.325000 ;
    END
  END SLEEP
  PIN X
    ANTENNADIFFAREA  0.509000 ;
    DIRECTION OUTPUT ;
    USE SIGNAL ;
    PORT
      LAYER li1 ;
        RECT 1.565000 0.255000 2.180000 0.825000 ;
        RECT 1.645000 1.845000 2.180000 2.465000 ;
        RECT 1.865000 0.825000 2.180000 1.845000 ;
    END
  END X
  PIN VGND
    DIRECTION INOUT ;
    SHAPE ABUTMENT ;
    USE GROUND ;
    PORT
      LAYER li1 ;
        RECT 0.000000 -0.085000 2.300000 0.085000 ;
        RECT 0.250000  0.085000 0.490000 0.595000 ;
        RECT 1.180000  0.085000 1.395000 0.595000 ;
    END
    PORT
      LAYER met1 ;
        RECT 0.000000 -0.240000 2.300000 0.240000 ;
    END
  END VGND
  PIN VPWR
    DIRECTION INOUT ;
    SHAPE ABUTMENT ;
    USE POWER ;
    PORT
      LAYER li1 ;
        RECT 0.000000 2.635000 2.300000 2.805000 ;
        RECT 1.145000 1.835000 1.475000 2.635000 ;
    END
    PORT
      LAYER met1 ;
        RECT 0.000000 2.480000 2.300000 2.960000 ;
    END
  END VPWR
  OBS
    LAYER li1 ;
      RECT 0.270000 1.495000 1.695000 1.665000 ;
      RECT 0.270000 1.665000 0.660000 1.840000 ;
      RECT 0.670000 0.265000 0.950000 0.595000 ;
      RECT 0.670000 0.595000 0.840000 1.495000 ;
      RECT 1.525000 0.995000 1.695000 1.495000 ;
  END
END sky130_fd_sc_hd__lpflow_inputiso1p_1
END LIBRARY
# Copyright 2020 The SkyWater PDK Authors
#
# Licensed under the Apache License, Version 2.0 (the "License");
# you may not use this file except in compliance with the License.
# You may obtain a copy of the License at
#
#     https://www.apache.org/licenses/LICENSE-2.0
#
# Unless required by applicable law or agreed to in writing, software
# distributed under the License is distributed on an "AS IS" BASIS,
# WITHOUT WARRANTIES OR CONDITIONS OF ANY KIND, either express or implied.
# See the License for the specific language governing permissions and
# limitations under the License.
#
# SPDX-License-Identifier: Apache-2.0

VERSION 5.5 ;
NAMESCASESENSITIVE ON ;
BUSBITCHARS "[]" ;
DIVIDERCHAR "/" ;
MACRO sky130_fd_sc_hd__lpflow_isobufsrc_1
  CLASS CORE ;
  SOURCE USER ;
  ORIGIN  0.000000  0.000000 ;
  SIZE  2.300000 BY  2.720000 ;
  SYMMETRY X Y R90 ;
  SITE unithd ;
  PIN A
    ANTENNAGATEAREA  0.126000 ;
    DIRECTION INPUT ;
    USE SIGNAL ;
    PORT
      LAYER li1 ;
        RECT 0.100000 0.725000 0.325000 1.325000 ;
    END
  END A
  PIN SLEEP
    ANTENNAGATEAREA  0.247500 ;
    DIRECTION INPUT ;
    USE SIGNAL ;
    PORT
      LAYER li1 ;
        RECT 0.960000 1.065000 1.325000 1.325000 ;
    END
  END SLEEP
  PIN X
    ANTENNADIFFAREA  0.435500 ;
    DIRECTION OUTPUT ;
    USE SIGNAL ;
    PORT
      LAYER li1 ;
        RECT 1.235000 0.255000 1.565000 0.725000 ;
        RECT 1.235000 0.725000 2.215000 0.895000 ;
        RECT 1.655000 1.850000 2.215000 2.465000 ;
        RECT 2.035000 0.895000 2.215000 1.850000 ;
    END
  END X
  PIN VGND
    DIRECTION INOUT ;
    SHAPE ABUTMENT ;
    USE GROUND ;
    PORT
      LAYER li1 ;
        RECT 0.000000 -0.085000 2.300000 0.085000 ;
        RECT 0.855000  0.085000 1.065000 0.895000 ;
        RECT 1.735000  0.085000 2.120000 0.555000 ;
    END
    PORT
      LAYER met1 ;
        RECT 0.000000 -0.240000 2.300000 0.240000 ;
    END
  END VGND
  PIN VPWR
    DIRECTION INOUT ;
    SHAPE ABUTMENT ;
    USE POWER ;
    PORT
      LAYER li1 ;
        RECT 0.000000 2.635000 2.300000 2.805000 ;
        RECT 0.875000 1.855000 1.205000 2.635000 ;
    END
    PORT
      LAYER met1 ;
        RECT 0.000000 2.480000 2.300000 2.960000 ;
    END
  END VPWR
  OBS
    LAYER li1 ;
      RECT 0.330000 0.370000 0.675000 0.545000 ;
      RECT 0.415000 1.510000 1.705000 1.680000 ;
      RECT 0.415000 1.680000 0.675000 1.905000 ;
      RECT 0.495000 0.545000 0.675000 1.510000 ;
      RECT 1.535000 1.075000 1.865000 1.245000 ;
      RECT 1.535000 1.245000 1.705000 1.510000 ;
  END
END sky130_fd_sc_hd__lpflow_isobufsrc_1
END LIBRARY
# Copyright 2020 The SkyWater PDK Authors
#
# Licensed under the Apache License, Version 2.0 (the "License");
# you may not use this file except in compliance with the License.
# You may obtain a copy of the License at
#
#     https://www.apache.org/licenses/LICENSE-2.0
#
# Unless required by applicable law or agreed to in writing, software
# distributed under the License is distributed on an "AS IS" BASIS,
# WITHOUT WARRANTIES OR CONDITIONS OF ANY KIND, either express or implied.
# See the License for the specific language governing permissions and
# limitations under the License.
#
# SPDX-License-Identifier: Apache-2.0

VERSION 5.5 ;
NAMESCASESENSITIVE ON ;
BUSBITCHARS "[]" ;
DIVIDERCHAR "/" ;
MACRO sky130_fd_sc_hd__maj3_1
  CLASS CORE ;
  SOURCE USER ;
  ORIGIN  0.000000  0.000000 ;
  SIZE  3.680000 BY  2.720000 ;
  SYMMETRY X Y R90 ;
  SITE unithd ;
  PIN A
    ANTENNAGATEAREA  0.252000 ;
    DIRECTION INPUT ;
    USE SIGNAL ;
    PORT
      LAYER li1 ;
        RECT 0.610000 0.995000 1.125000 1.325000 ;
        RECT 0.610000 1.325000 0.780000 2.460000 ;
    END
  END A
  PIN B
    ANTENNAGATEAREA  0.252000 ;
    DIRECTION INPUT ;
    USE SIGNAL ;
    PORT
      LAYER li1 ;
        RECT 1.500000 0.995000 1.905000 1.615000 ;
    END
  END B
  PIN C
    ANTENNAGATEAREA  0.252000 ;
    DIRECTION INPUT ;
    USE SIGNAL ;
    PORT
      LAYER li1 ;
        RECT 2.415000 0.765000 2.755000 1.325000 ;
    END
  END C
  PIN X
    ANTENNADIFFAREA  0.602250 ;
    DIRECTION OUTPUT ;
    USE SIGNAL ;
    PORT
      LAYER li1 ;
        RECT 3.255000 0.255000 3.595000 0.825000 ;
        RECT 3.255000 2.160000 3.595000 2.465000 ;
        RECT 3.265000 1.495000 3.595000 2.160000 ;
        RECT 3.370000 0.825000 3.595000 1.495000 ;
    END
  END X
  PIN VGND
    DIRECTION INOUT ;
    SHAPE ABUTMENT ;
    USE GROUND ;
    PORT
      LAYER li1 ;
        RECT 0.000000 -0.085000 3.680000 0.085000 ;
        RECT 0.875000  0.085000 1.205000 0.485000 ;
        RECT 2.545000  0.085000 2.880000 0.470000 ;
    END
    PORT
      LAYER met1 ;
        RECT 0.000000 -0.240000 3.680000 0.240000 ;
    END
  END VGND
  PIN VPWR
    DIRECTION INOUT ;
    SHAPE ABUTMENT ;
    USE POWER ;
    PORT
      LAYER li1 ;
        RECT 0.000000 2.635000 3.680000 2.805000 ;
        RECT 0.955000 1.715000 1.205000 2.635000 ;
        RECT 2.555000 1.845000 2.885000 2.635000 ;
    END
    PORT
      LAYER met1 ;
        RECT 0.000000 2.480000 3.680000 2.960000 ;
    END
  END VPWR
  OBS
    LAYER li1 ;
      RECT 0.135000 0.255000 0.395000 0.655000 ;
      RECT 0.135000 0.655000 2.245000 0.825000 ;
      RECT 0.135000 0.825000 0.395000 2.125000 ;
      RECT 1.655000 0.255000 1.985000 0.640000 ;
      RECT 1.655000 0.640000 2.245000 0.655000 ;
      RECT 1.655000 1.815000 2.245000 2.080000 ;
      RECT 2.075000 0.825000 2.245000 1.495000 ;
      RECT 2.075000 1.495000 3.095000 1.665000 ;
      RECT 2.075000 1.665000 2.245000 1.815000 ;
      RECT 2.925000 0.995000 3.200000 1.325000 ;
      RECT 2.925000 1.325000 3.095000 1.495000 ;
  END
END sky130_fd_sc_hd__maj3_1
END LIBRARY
# Copyright 2020 The SkyWater PDK Authors
#
# Licensed under the Apache License, Version 2.0 (the "License");
# you may not use this file except in compliance with the License.
# You may obtain a copy of the License at
#
#     https://www.apache.org/licenses/LICENSE-2.0
#
# Unless required by applicable law or agreed to in writing, software
# distributed under the License is distributed on an "AS IS" BASIS,
# WITHOUT WARRANTIES OR CONDITIONS OF ANY KIND, either express or implied.
# See the License for the specific language governing permissions and
# limitations under the License.
#
# SPDX-License-Identifier: Apache-2.0

VERSION 5.5 ;
NAMESCASESENSITIVE ON ;
BUSBITCHARS "[]" ;
DIVIDERCHAR "/" ;
MACRO sky130_fd_sc_hd__mux2i_1
  CLASS CORE ;
  SOURCE USER ;
  ORIGIN  0.000000  0.000000 ;
  SIZE  3.680000 BY  2.720000 ;
  SYMMETRY X Y R90 ;
  SITE unithd ;
  PIN A0
    ANTENNAGATEAREA  0.247500 ;
    DIRECTION INPUT ;
    USE SIGNAL ;
    PORT
      LAYER li1 ;
        RECT 0.085000 1.060000 0.420000 1.285000 ;
    END
  END A0
  PIN A1
    ANTENNAGATEAREA  0.247500 ;
    DIRECTION INPUT ;
    USE SIGNAL ;
    PORT
      LAYER li1 ;
        RECT 0.955000 0.995000 1.125000 1.155000 ;
        RECT 0.955000 1.155000 1.205000 1.325000 ;
        RECT 1.035000 1.325000 1.205000 1.445000 ;
        RECT 1.035000 1.445000 1.235000 2.110000 ;
    END
  END A1
  PIN S
    ANTENNAGATEAREA  0.495000 ;
    DIRECTION INPUT ;
    USE SIGNAL ;
    PORT
      LAYER li1 ;
        RECT 3.260000 0.760000 3.595000 1.620000 ;
    END
  END S
  PIN Y
    ANTENNADIFFAREA  0.480500 ;
    DIRECTION OUTPUT ;
    USE SIGNAL ;
    PORT
      LAYER li1 ;
        RECT 0.590000 0.595000 0.780000 1.455000 ;
        RECT 0.590000 1.455000 0.840000 2.125000 ;
    END
  END Y
  PIN VGND
    DIRECTION INOUT ;
    SHAPE ABUTMENT ;
    USE GROUND ;
    PORT
      LAYER li1 ;
        RECT 0.000000 -0.085000 3.680000 0.085000 ;
        RECT 1.975000  0.085000 2.145000 0.545000 ;
        RECT 3.335000  0.085000 3.555000 0.545000 ;
    END
    PORT
      LAYER met1 ;
        RECT 0.000000 -0.240000 3.680000 0.240000 ;
    END
  END VGND
  PIN VPWR
    DIRECTION INOUT ;
    SHAPE ABUTMENT ;
    USE POWER ;
    PORT
      LAYER li1 ;
        RECT 0.000000 2.635000 3.680000 2.805000 ;
        RECT 1.745000 1.835000 1.975000 2.635000 ;
        RECT 3.295000 1.835000 3.590000 2.635000 ;
    END
    PORT
      LAYER met1 ;
        RECT 0.000000 2.480000 3.680000 2.960000 ;
    END
  END VPWR
  OBS
    LAYER li1 ;
      RECT 0.085000 0.255000 1.805000 0.425000 ;
      RECT 0.085000 0.425000 0.440000 0.465000 ;
      RECT 0.085000 0.465000 0.345000 0.885000 ;
      RECT 0.120000 1.455000 0.420000 2.295000 ;
      RECT 0.120000 2.295000 1.575000 2.465000 ;
      RECT 0.955000 0.655000 1.520000 0.715000 ;
      RECT 0.955000 0.715000 2.620000 0.825000 ;
      RECT 0.965000 0.425000 1.805000 0.465000 ;
      RECT 1.295000 0.825000 2.620000 0.885000 ;
      RECT 1.385000 1.075000 3.085000 1.310000 ;
      RECT 1.405000 1.480000 2.615000 1.650000 ;
      RECT 1.405000 1.650000 1.575000 2.295000 ;
      RECT 2.285000 1.650000 2.615000 2.465000 ;
      RECT 2.385000 0.255000 2.620000 0.715000 ;
      RECT 2.800000 0.255000 3.165000 0.485000 ;
      RECT 2.800000 0.485000 3.085000 1.075000 ;
      RECT 2.860000 1.310000 3.085000 2.465000 ;
  END
END sky130_fd_sc_hd__mux2i_1
END LIBRARY
# Copyright 2020 The SkyWater PDK Authors
#
# Licensed under the Apache License, Version 2.0 (the "License");
# you may not use this file except in compliance with the License.
# You may obtain a copy of the License at
#
#     https://www.apache.org/licenses/LICENSE-2.0
#
# Unless required by applicable law or agreed to in writing, software
# distributed under the License is distributed on an "AS IS" BASIS,
# WITHOUT WARRANTIES OR CONDITIONS OF ANY KIND, either express or implied.
# See the License for the specific language governing permissions and
# limitations under the License.
#
# SPDX-License-Identifier: Apache-2.0

VERSION 5.5 ;
NAMESCASESENSITIVE ON ;
BUSBITCHARS "[]" ;
DIVIDERCHAR "/" ;
MACRO sky130_fd_sc_hd__nand2_1
  CLASS CORE ;
  SOURCE USER ;
  ORIGIN  0.000000  0.000000 ;
  SIZE  1.380000 BY  2.720000 ;
  SYMMETRY X Y R90 ;
  SITE unithd ;
  PIN A
    ANTENNAGATEAREA  0.247500 ;
    DIRECTION INPUT ;
    USE SIGNAL ;
    PORT
      LAYER li1 ;
        RECT 0.940000 1.075000 1.275000 1.325000 ;
    END
  END A
  PIN B
    ANTENNAGATEAREA  0.247500 ;
    DIRECTION INPUT ;
    USE SIGNAL ;
    PORT
      LAYER li1 ;
        RECT 0.095000 1.055000 0.430000 1.325000 ;
    END
  END B
  PIN Y
    ANTENNADIFFAREA  0.439000 ;
    DIRECTION OUTPUT ;
    USE SIGNAL ;
    PORT
      LAYER li1 ;
        RECT 0.535000 1.485000 0.865000 2.465000 ;
        RECT 0.600000 0.255000 1.295000 0.885000 ;
        RECT 0.600000 0.885000 0.770000 1.485000 ;
    END
  END Y
  PIN VGND
    DIRECTION INOUT ;
    SHAPE ABUTMENT ;
    USE GROUND ;
    PORT
      LAYER li1 ;
        RECT 0.000000 -0.085000 1.380000 0.085000 ;
        RECT 0.085000  0.085000 0.395000 0.885000 ;
    END
    PORT
      LAYER met1 ;
        RECT 0.000000 -0.240000 1.380000 0.240000 ;
    END
  END VGND
  PIN VPWR
    DIRECTION INOUT ;
    SHAPE ABUTMENT ;
    USE POWER ;
    PORT
      LAYER li1 ;
        RECT 0.000000 2.635000 1.380000 2.805000 ;
        RECT 0.085000 1.495000 0.365000 2.635000 ;
        RECT 1.035000 1.495000 1.295000 2.635000 ;
    END
    PORT
      LAYER met1 ;
        RECT 0.000000 2.480000 1.380000 2.960000 ;
    END
  END VPWR
  OBS
  END
END sky130_fd_sc_hd__nand2_1
END LIBRARY
# Copyright 2020 The SkyWater PDK Authors
#
# Licensed under the Apache License, Version 2.0 (the "License");
# you may not use this file except in compliance with the License.
# You may obtain a copy of the License at
#
#     https://www.apache.org/licenses/LICENSE-2.0
#
# Unless required by applicable law or agreed to in writing, software
# distributed under the License is distributed on an "AS IS" BASIS,
# WITHOUT WARRANTIES OR CONDITIONS OF ANY KIND, either express or implied.
# See the License for the specific language governing permissions and
# limitations under the License.
#
# SPDX-License-Identifier: Apache-2.0

VERSION 5.5 ;
NAMESCASESENSITIVE ON ;
BUSBITCHARS "[]" ;
DIVIDERCHAR "/" ;
MACRO sky130_fd_sc_hd__nand2b_1
  CLASS CORE ;
  SOURCE USER ;
  ORIGIN  0.000000  0.000000 ;
  SIZE  2.300000 BY  2.720000 ;
  SYMMETRY X Y R90 ;
  SITE unithd ;
  PIN A_N
    ANTENNAGATEAREA  0.126000 ;
    DIRECTION INPUT ;
    USE SIGNAL ;
    PORT
      LAYER li1 ;
        RECT 0.090000 1.075000 0.440000 1.315000 ;
    END
  END A_N
  PIN B
    ANTENNAGATEAREA  0.247500 ;
    DIRECTION INPUT ;
    USE SIGNAL ;
    PORT
      LAYER li1 ;
        RECT 0.610000 1.075000 1.085000 1.315000 ;
    END
  END B
  PIN Y
    ANTENNADIFFAREA  0.439000 ;
    DIRECTION OUTPUT ;
    USE SIGNAL ;
    PORT
      LAYER li1 ;
        RECT 1.000000 1.835000 2.170000 2.005000 ;
        RECT 1.000000 2.005000 1.330000 2.465000 ;
        RECT 1.420000 0.255000 2.170000 0.545000 ;
        RECT 1.800000 0.545000 2.170000 1.835000 ;
    END
  END Y
  PIN VGND
    DIRECTION INOUT ;
    SHAPE ABUTMENT ;
    USE GROUND ;
    PORT
      LAYER li1 ;
        RECT 0.000000 -0.085000 2.300000 0.085000 ;
        RECT 0.580000  0.085000 0.910000 0.545000 ;
    END
    PORT
      LAYER met1 ;
        RECT 0.000000 -0.240000 2.300000 0.240000 ;
    END
  END VGND
  PIN VPWR
    DIRECTION INOUT ;
    SHAPE ABUTMENT ;
    USE POWER ;
    PORT
      LAYER li1 ;
        RECT 0.000000 2.635000 2.300000 2.805000 ;
        RECT 0.580000 1.835000 0.830000 2.635000 ;
        RECT 1.500000 2.175000 1.715000 2.635000 ;
    END
    PORT
      LAYER met1 ;
        RECT 0.000000 2.480000 2.300000 2.960000 ;
    END
  END VPWR
  OBS
    LAYER li1 ;
      RECT 0.090000 0.525000 0.360000 0.735000 ;
      RECT 0.090000 0.735000 1.425000 0.905000 ;
      RECT 0.090000 1.495000 1.425000 1.665000 ;
      RECT 0.090000 1.665000 0.370000 1.825000 ;
      RECT 1.255000 0.905000 1.425000 1.075000 ;
      RECT 1.255000 1.075000 1.630000 1.325000 ;
      RECT 1.255000 1.325000 1.425000 1.495000 ;
  END
END sky130_fd_sc_hd__nand2b_1
END LIBRARY
# Copyright 2020 The SkyWater PDK Authors
#
# Licensed under the Apache License, Version 2.0 (the "License");
# you may not use this file except in compliance with the License.
# You may obtain a copy of the License at
#
#     https://www.apache.org/licenses/LICENSE-2.0
#
# Unless required by applicable law or agreed to in writing, software
# distributed under the License is distributed on an "AS IS" BASIS,
# WITHOUT WARRANTIES OR CONDITIONS OF ANY KIND, either express or implied.
# See the License for the specific language governing permissions and
# limitations under the License.
#
# SPDX-License-Identifier: Apache-2.0

VERSION 5.5 ;
NAMESCASESENSITIVE ON ;
BUSBITCHARS "[]" ;
DIVIDERCHAR "/" ;
MACRO sky130_fd_sc_hd__nand3_1
  CLASS CORE ;
  SOURCE USER ;
  ORIGIN  0.000000  0.000000 ;
  SIZE  1.840000 BY  2.720000 ;
  SYMMETRY X Y R90 ;
  SITE unithd ;
  PIN A
    ANTENNAGATEAREA  0.247500 ;
    DIRECTION INPUT ;
    USE SIGNAL ;
    PORT
      LAYER li1 ;
        RECT 1.445000 0.995000 1.755000 1.325000 ;
    END
  END A
  PIN B
    ANTENNAGATEAREA  0.247500 ;
    DIRECTION INPUT ;
    USE SIGNAL ;
    PORT
      LAYER li1 ;
        RECT 0.865000 0.765000 1.240000 1.325000 ;
    END
  END B
  PIN C
    ANTENNAGATEAREA  0.247500 ;
    DIRECTION INPUT ;
    USE SIGNAL ;
    PORT
      LAYER li1 ;
        RECT 0.110000 0.745000 0.330000 1.325000 ;
    END
  END C
  PIN Y
    ANTENNADIFFAREA  0.699000 ;
    DIRECTION OUTPUT ;
    USE SIGNAL ;
    PORT
      LAYER li1 ;
        RECT 0.515000 0.255000 1.745000 0.595000 ;
        RECT 0.515000 0.595000 0.695000 1.495000 ;
        RECT 0.515000 1.495000 1.745000 1.665000 ;
        RECT 0.515000 1.665000 0.845000 2.465000 ;
        RECT 1.415000 0.595000 1.745000 0.825000 ;
        RECT 1.415000 1.665000 1.745000 2.465000 ;
    END
  END Y
  PIN VGND
    DIRECTION INOUT ;
    SHAPE ABUTMENT ;
    USE GROUND ;
    PORT
      LAYER li1 ;
        RECT 0.000000 -0.085000 1.840000 0.085000 ;
        RECT 0.090000  0.085000 0.345000 0.575000 ;
    END
    PORT
      LAYER met1 ;
        RECT 0.000000 -0.240000 1.840000 0.240000 ;
    END
  END VGND
  PIN VPWR
    DIRECTION INOUT ;
    SHAPE ABUTMENT ;
    USE POWER ;
    PORT
      LAYER li1 ;
        RECT 0.000000 2.635000 1.840000 2.805000 ;
        RECT 0.090000 1.495000 0.345000 2.635000 ;
        RECT 1.015000 1.835000 1.245000 2.635000 ;
    END
    PORT
      LAYER met1 ;
        RECT 0.000000 2.480000 1.840000 2.960000 ;
    END
  END VPWR
  OBS
  END
END sky130_fd_sc_hd__nand3_1
END LIBRARY
# Copyright 2020 The SkyWater PDK Authors
#
# Licensed under the Apache License, Version 2.0 (the "License");
# you may not use this file except in compliance with the License.
# You may obtain a copy of the License at
#
#     https://www.apache.org/licenses/LICENSE-2.0
#
# Unless required by applicable law or agreed to in writing, software
# distributed under the License is distributed on an "AS IS" BASIS,
# WITHOUT WARRANTIES OR CONDITIONS OF ANY KIND, either express or implied.
# See the License for the specific language governing permissions and
# limitations under the License.
#
# SPDX-License-Identifier: Apache-2.0

VERSION 5.5 ;
NAMESCASESENSITIVE ON ;
BUSBITCHARS "[]" ;
DIVIDERCHAR "/" ;
MACRO sky130_fd_sc_hd__nor2_1
  CLASS CORE ;
  SOURCE USER ;
  ORIGIN  0.000000  0.000000 ;
  SIZE  1.380000 BY  2.720000 ;
  SYMMETRY X Y R90 ;
  SITE unithd ;
  PIN A
    ANTENNAGATEAREA  0.247500 ;
    DIRECTION INPUT ;
    USE SIGNAL ;
    PORT
      LAYER li1 ;
        RECT 0.945000 1.075000 1.295000 1.325000 ;
    END
  END A
  PIN B
    ANTENNAGATEAREA  0.247500 ;
    DIRECTION INPUT ;
    USE SIGNAL ;
    PORT
      LAYER li1 ;
        RECT 0.085000 1.075000 0.435000 1.325000 ;
    END
  END B
  PIN Y
    ANTENNADIFFAREA  0.435500 ;
    DIRECTION OUTPUT ;
    USE SIGNAL ;
    PORT
      LAYER li1 ;
        RECT 0.095000 1.495000 0.775000 1.665000 ;
        RECT 0.095000 1.665000 0.425000 2.450000 ;
        RECT 0.515000 0.255000 0.845000 0.895000 ;
        RECT 0.605000 0.895000 0.775000 1.495000 ;
    END
  END Y
  PIN VGND
    DIRECTION INOUT ;
    SHAPE ABUTMENT ;
    USE GROUND ;
    PORT
      LAYER li1 ;
        RECT 0.000000 -0.085000 1.380000 0.085000 ;
        RECT 0.105000  0.085000 0.345000 0.895000 ;
        RECT 1.015000  0.085000 1.285000 0.895000 ;
    END
    PORT
      LAYER met1 ;
        RECT 0.000000 -0.240000 1.380000 0.240000 ;
    END
  END VGND
  PIN VPWR
    DIRECTION INOUT ;
    SHAPE ABUTMENT ;
    USE POWER ;
    PORT
      LAYER li1 ;
        RECT 0.000000 2.635000 1.380000 2.805000 ;
        RECT 0.955000 1.495000 1.285000 2.635000 ;
    END
    PORT
      LAYER met1 ;
        RECT 0.000000 2.480000 1.380000 2.960000 ;
    END
  END VPWR
  OBS
  END
END sky130_fd_sc_hd__nor2_1
END LIBRARY
# Copyright 2020 The SkyWater PDK Authors
#
# Licensed under the Apache License, Version 2.0 (the "License");
# you may not use this file except in compliance with the License.
# You may obtain a copy of the License at
#
#     https://www.apache.org/licenses/LICENSE-2.0
#
# Unless required by applicable law or agreed to in writing, software
# distributed under the License is distributed on an "AS IS" BASIS,
# WITHOUT WARRANTIES OR CONDITIONS OF ANY KIND, either express or implied.
# See the License for the specific language governing permissions and
# limitations under the License.
#
# SPDX-License-Identifier: Apache-2.0

VERSION 5.5 ;
NAMESCASESENSITIVE ON ;
BUSBITCHARS "[]" ;
DIVIDERCHAR "/" ;
MACRO sky130_fd_sc_hd__nor3_1
  CLASS CORE ;
  SOURCE USER ;
  ORIGIN  0.000000  0.000000 ;
  SIZE  1.840000 BY  2.720000 ;
  SYMMETRY X Y R90 ;
  SITE unithd ;
  PIN A
    ANTENNAGATEAREA  0.247500 ;
    DIRECTION INPUT ;
    USE SIGNAL ;
    PORT
      LAYER li1 ;
        RECT 1.485000 0.655000 1.755000 1.665000 ;
    END
  END A
  PIN B
    ANTENNAGATEAREA  0.247500 ;
    DIRECTION INPUT ;
    USE SIGNAL ;
    PORT
      LAYER li1 ;
        RECT 0.595000 0.995000 0.975000 1.325000 ;
        RECT 0.595000 1.325000 0.830000 2.005000 ;
    END
  END B
  PIN C
    ANTENNAGATEAREA  0.247500 ;
    DIRECTION INPUT ;
    USE SIGNAL ;
    PORT
      LAYER li1 ;
        RECT 0.090000 0.995000 0.425000 1.325000 ;
    END
  END C
  PIN Y
    ANTENNADIFFAREA  0.604500 ;
    DIRECTION OUTPUT ;
    USE SIGNAL ;
    PORT
      LAYER li1 ;
        RECT 0.090000 0.385000 0.345000 0.655000 ;
        RECT 0.090000 0.655000 1.315000 0.825000 ;
        RECT 0.090000 1.495000 0.425000 2.280000 ;
        RECT 0.090000 2.280000 1.170000 2.450000 ;
        RECT 1.000000 1.495000 1.315000 1.665000 ;
        RECT 1.000000 1.665000 1.170000 2.280000 ;
        RECT 1.015000 0.385000 1.185000 0.655000 ;
        RECT 1.145000 0.825000 1.315000 1.495000 ;
    END
  END Y
  PIN VGND
    DIRECTION INOUT ;
    SHAPE ABUTMENT ;
    USE GROUND ;
    PORT
      LAYER li1 ;
        RECT 0.000000 -0.085000 1.840000 0.085000 ;
        RECT 0.515000  0.085000 0.845000 0.485000 ;
        RECT 1.355000  0.085000 1.685000 0.485000 ;
    END
    PORT
      LAYER met1 ;
        RECT 0.000000 -0.240000 1.840000 0.240000 ;
    END
  END VGND
  PIN VPWR
    DIRECTION INOUT ;
    SHAPE ABUTMENT ;
    USE POWER ;
    PORT
      LAYER li1 ;
        RECT 0.000000 2.635000 1.840000 2.805000 ;
        RECT 1.435000 1.835000 1.750000 2.635000 ;
    END
    PORT
      LAYER met1 ;
        RECT 0.000000 2.480000 1.840000 2.960000 ;
    END
  END VPWR
  OBS
  END
END sky130_fd_sc_hd__nor3_1
END LIBRARY
# Copyright 2020 The SkyWater PDK Authors
#
# Licensed under the Apache License, Version 2.0 (the "License");
# you may not use this file except in compliance with the License.
# You may obtain a copy of the License at
#
#     https://www.apache.org/licenses/LICENSE-2.0
#
# Unless required by applicable law or agreed to in writing, software
# distributed under the License is distributed on an "AS IS" BASIS,
# WITHOUT WARRANTIES OR CONDITIONS OF ANY KIND, either express or implied.
# See the License for the specific language governing permissions and
# limitations under the License.
#
# SPDX-License-Identifier: Apache-2.0

VERSION 5.5 ;
NAMESCASESENSITIVE ON ;
BUSBITCHARS "[]" ;
DIVIDERCHAR "/" ;
MACRO sky130_fd_sc_hd__nor3b_1
  CLASS CORE ;
  SOURCE USER ;
  ORIGIN  0.000000  0.000000 ;
  SIZE  2.760000 BY  2.720000 ;
  SYMMETRY X Y R90 ;
  SITE unithd ;
  PIN A
    ANTENNAGATEAREA  0.247500 ;
    DIRECTION INPUT ;
    USE SIGNAL ;
    PORT
      LAYER li1 ;
        RECT 1.475000 0.995000 1.815000 1.615000 ;
    END
  END A
  PIN B
    ANTENNAGATEAREA  0.247500 ;
    DIRECTION INPUT ;
    USE SIGNAL ;
    PORT
      LAYER li1 ;
        RECT 1.065000 0.995000 1.305000 1.615000 ;
    END
  END B
  PIN C_N
    ANTENNAGATEAREA  0.126000 ;
    DIRECTION INPUT ;
    USE SIGNAL ;
    PORT
      LAYER li1 ;
        RECT 1.985000 0.995000 2.335000 1.615000 ;
    END
  END C_N
  PIN Y
    ANTENNADIFFAREA  0.716500 ;
    DIRECTION OUTPUT ;
    USE SIGNAL ;
    PORT
      LAYER li1 ;
        RECT 0.085000 0.255000 0.605000 0.655000 ;
        RECT 0.085000 0.655000 1.445000 0.825000 ;
        RECT 0.085000 0.825000 0.255000 1.445000 ;
        RECT 0.085000 1.445000 0.545000 2.455000 ;
        RECT 1.275000 0.310000 1.445000 0.655000 ;
    END
  END Y
  PIN VGND
    DIRECTION INOUT ;
    SHAPE ABUTMENT ;
    USE GROUND ;
    PORT
      LAYER li1 ;
        RECT 0.000000 -0.085000 2.760000 0.085000 ;
        RECT 0.775000  0.085000 1.105000 0.485000 ;
        RECT 1.615000  0.085000 1.945000 0.825000 ;
    END
    PORT
      LAYER met1 ;
        RECT 0.000000 -0.240000 2.760000 0.240000 ;
    END
  END VGND
  PIN VPWR
    DIRECTION INOUT ;
    SHAPE ABUTMENT ;
    USE POWER ;
    PORT
      LAYER li1 ;
        RECT 0.000000 2.635000 2.760000 2.805000 ;
        RECT 1.615000 2.125000 1.945000 2.635000 ;
    END
    PORT
      LAYER met1 ;
        RECT 0.000000 2.480000 2.760000 2.960000 ;
    END
  END VPWR
  OBS
    LAYER li1 ;
      RECT 0.425000 1.075000 0.885000 1.245000 ;
      RECT 0.715000 1.245000 0.885000 1.785000 ;
      RECT 0.715000 1.785000 2.675000 1.955000 ;
      RECT 2.180000 0.405000 2.350000 0.655000 ;
      RECT 2.180000 0.655000 2.675000 0.825000 ;
      RECT 2.505000 0.825000 2.675000 1.785000 ;
  END
END sky130_fd_sc_hd__nor3b_1
END LIBRARY
# Copyright 2020 The SkyWater PDK Authors
#
# Licensed under the Apache License, Version 2.0 (the "License");
# you may not use this file except in compliance with the License.
# You may obtain a copy of the License at
#
#     https://www.apache.org/licenses/LICENSE-2.0
#
# Unless required by applicable law or agreed to in writing, software
# distributed under the License is distributed on an "AS IS" BASIS,
# WITHOUT WARRANTIES OR CONDITIONS OF ANY KIND, either express or implied.
# See the License for the specific language governing permissions and
# limitations under the License.
#
# SPDX-License-Identifier: Apache-2.0

VERSION 5.5 ;
NAMESCASESENSITIVE ON ;
BUSBITCHARS "[]" ;
DIVIDERCHAR "/" ;
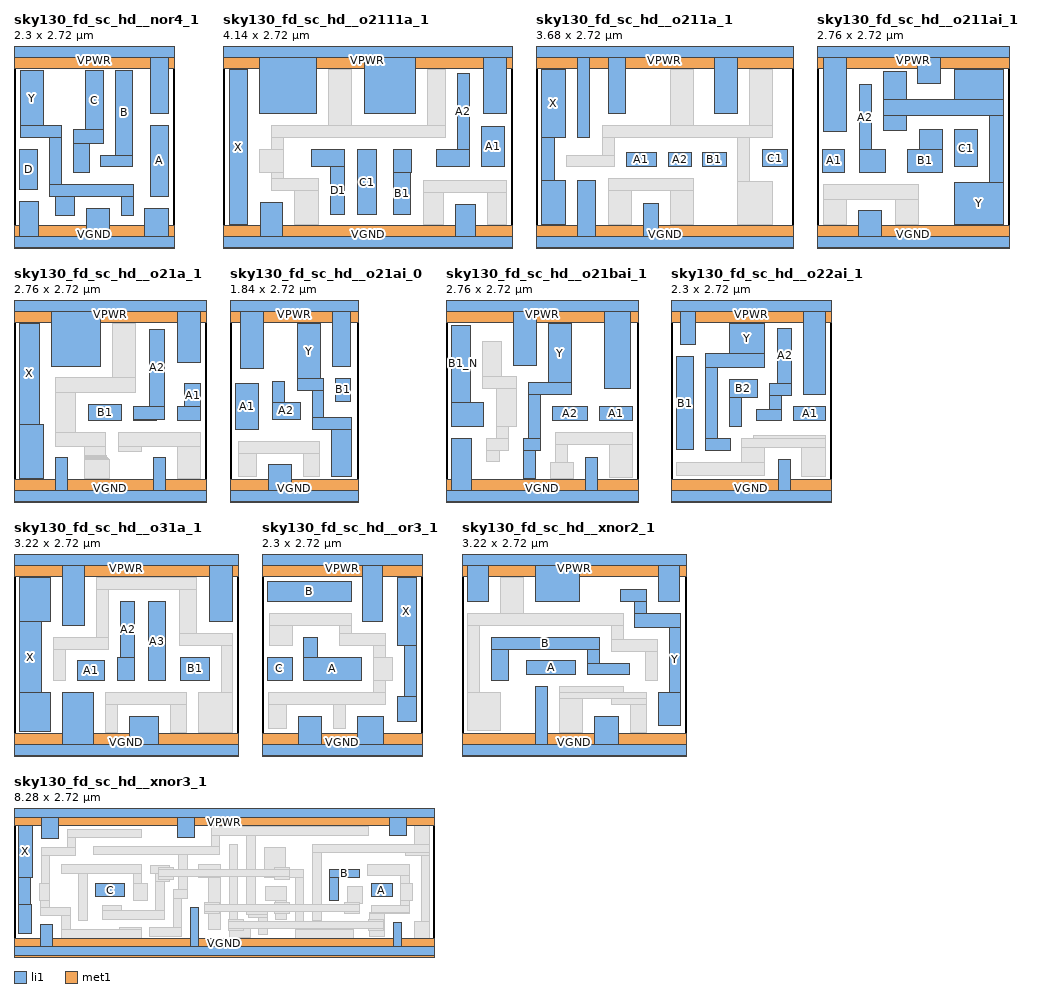
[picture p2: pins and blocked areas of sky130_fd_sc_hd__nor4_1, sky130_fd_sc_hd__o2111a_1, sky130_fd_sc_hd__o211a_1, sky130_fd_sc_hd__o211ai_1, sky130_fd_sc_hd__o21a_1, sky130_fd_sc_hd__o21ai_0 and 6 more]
MACRO sky130_fd_sc_hd__nor4_1
  CLASS CORE ;
  SOURCE USER ;
  ORIGIN  0.000000  0.000000 ;
  SIZE  2.300000 BY  2.720000 ;
  SYMMETRY X Y R90 ;
  SITE unithd ;
  PIN A
    ANTENNAGATEAREA  0.247500 ;
    DIRECTION INPUT ;
    USE SIGNAL ;
    PORT
      LAYER li1 ;
        RECT 1.955000 0.655000 2.215000 1.665000 ;
    END
  END A
  PIN B
    ANTENNAGATEAREA  0.247500 ;
    DIRECTION INPUT ;
    USE SIGNAL ;
    PORT
      LAYER li1 ;
        RECT 1.245000 1.075000 1.695000 1.245000 ;
        RECT 1.455000 1.245000 1.695000 2.450000 ;
    END
  END B
  PIN C
    ANTENNAGATEAREA  0.247500 ;
    DIRECTION INPUT ;
    USE SIGNAL ;
    PORT
      LAYER li1 ;
        RECT 0.845000 0.995000 1.075000 1.415000 ;
        RECT 0.845000 1.415000 1.285000 1.615000 ;
        RECT 1.030000 1.615000 1.285000 2.450000 ;
    END
  END C
  PIN D
    ANTENNAGATEAREA  0.247500 ;
    DIRECTION INPUT ;
    USE SIGNAL ;
    PORT
      LAYER li1 ;
        RECT 0.085000 0.745000 0.335000 1.325000 ;
    END
  END D
  PIN Y
    ANTENNADIFFAREA  0.672750 ;
    DIRECTION OUTPUT ;
    USE SIGNAL ;
    PORT
      LAYER li1 ;
        RECT 0.090000 1.495000 0.675000 1.665000 ;
        RECT 0.090000 1.665000 0.425000 2.450000 ;
        RECT 0.505000 0.645000 0.860000 0.655000 ;
        RECT 0.505000 0.655000 1.705000 0.825000 ;
        RECT 0.505000 0.825000 0.675000 1.495000 ;
        RECT 0.595000 0.385000 0.860000 0.645000 ;
        RECT 1.535000 0.385000 1.705000 0.655000 ;
    END
  END Y
  PIN VGND
    DIRECTION INOUT ;
    SHAPE ABUTMENT ;
    USE GROUND ;
    PORT
      LAYER li1 ;
        RECT 0.000000 -0.085000 2.300000 0.085000 ;
        RECT 0.085000  0.085000 0.345000 0.575000 ;
        RECT 1.035000  0.085000 1.365000 0.485000 ;
        RECT 1.875000  0.085000 2.205000 0.485000 ;
    END
    PORT
      LAYER met1 ;
        RECT 0.000000 -0.240000 2.300000 0.240000 ;
    END
  END VGND
  PIN VPWR
    DIRECTION INOUT ;
    SHAPE ABUTMENT ;
    USE POWER ;
    PORT
      LAYER li1 ;
        RECT 0.000000 2.635000 2.300000 2.805000 ;
        RECT 1.955000 1.835000 2.215000 2.635000 ;
    END
    PORT
      LAYER met1 ;
        RECT 0.000000 2.480000 2.300000 2.960000 ;
    END
  END VPWR
  OBS
  END
END sky130_fd_sc_hd__nor4_1
END LIBRARY
# Copyright 2020 The SkyWater PDK Authors
#
# Licensed under the Apache License, Version 2.0 (the "License");
# you may not use this file except in compliance with the License.
# You may obtain a copy of the License at
#
#     https://www.apache.org/licenses/LICENSE-2.0
#
# Unless required by applicable law or agreed to in writing, software
# distributed under the License is distributed on an "AS IS" BASIS,
# WITHOUT WARRANTIES OR CONDITIONS OF ANY KIND, either express or implied.
# See the License for the specific language governing permissions and
# limitations under the License.
#
# SPDX-License-Identifier: Apache-2.0

VERSION 5.5 ;
NAMESCASESENSITIVE ON ;
BUSBITCHARS "[]" ;
DIVIDERCHAR "/" ;
MACRO sky130_fd_sc_hd__o2111a_1
  CLASS CORE ;
  SOURCE USER ;
  ORIGIN  0.000000  0.000000 ;
  SIZE  4.140000 BY  2.720000 ;
  SYMMETRY X Y R90 ;
  SITE unithd ;
  PIN A1
    ANTENNAGATEAREA  0.247500 ;
    DIRECTION INPUT ;
    USE SIGNAL ;
    PORT
      LAYER li1 ;
        RECT 3.705000 1.075000 4.035000 1.660000 ;
    END
  END A1
  PIN A2
    ANTENNAGATEAREA  0.247500 ;
    DIRECTION INPUT ;
    USE SIGNAL ;
    PORT
      LAYER li1 ;
        RECT 3.050000 1.075000 3.535000 1.325000 ;
        RECT 3.350000 1.325000 3.535000 2.415000 ;
    END
  END A2
  PIN B1
    ANTENNAGATEAREA  0.247500 ;
    DIRECTION INPUT ;
    USE SIGNAL ;
    PORT
      LAYER li1 ;
        RECT 2.445000 0.390000 2.690000 0.995000 ;
        RECT 2.445000 0.995000 2.705000 1.325000 ;
    END
  END B1
  PIN C1
    ANTENNAGATEAREA  0.247500 ;
    DIRECTION INPUT ;
    USE SIGNAL ;
    PORT
      LAYER li1 ;
        RECT 1.925000 0.390000 2.195000 1.325000 ;
    END
  END C1
  PIN D1
    ANTENNAGATEAREA  0.247500 ;
    DIRECTION INPUT ;
    USE SIGNAL ;
    PORT
      LAYER li1 ;
        RECT 1.265000 1.075000 1.745000 1.325000 ;
        RECT 1.535000 0.390000 1.745000 1.075000 ;
    END
  END D1
  PIN X
    ANTENNADIFFAREA  0.429000 ;
    DIRECTION OUTPUT ;
    USE SIGNAL ;
    PORT
      LAYER li1 ;
        RECT 0.095000 0.255000 0.355000 2.465000 ;
    END
  END X
  PIN VGND
    DIRECTION INOUT ;
    SHAPE ABUTMENT ;
    USE GROUND ;
    PORT
      LAYER li1 ;
        RECT 0.000000 -0.085000 4.140000 0.085000 ;
        RECT 0.535000  0.085000 0.845000 0.565000 ;
        RECT 3.330000  0.085000 3.620000 0.535000 ;
    END
    PORT
      LAYER met1 ;
        RECT 0.000000 -0.240000 4.140000 0.240000 ;
    END
  END VGND
  PIN VPWR
    DIRECTION INOUT ;
    SHAPE ABUTMENT ;
    USE POWER ;
    PORT
      LAYER li1 ;
        RECT 0.000000 2.635000 4.140000 2.805000 ;
        RECT 0.525000 1.835000 1.335000 2.635000 ;
        RECT 2.020000 1.835000 2.760000 2.635000 ;
        RECT 3.730000 1.835000 4.055000 2.635000 ;
    END
    PORT
      LAYER met1 ;
        RECT 0.000000 2.480000 4.140000 2.960000 ;
    END
  END VPWR
  OBS
    LAYER li1 ;
      RECT 0.525000 0.995000 0.865000 1.325000 ;
      RECT 0.695000 0.735000 1.365000 0.905000 ;
      RECT 0.695000 0.905000 0.865000 0.995000 ;
      RECT 0.695000 1.325000 0.865000 1.495000 ;
      RECT 0.695000 1.495000 3.180000 1.665000 ;
      RECT 1.025000 0.255000 1.365000 0.735000 ;
      RECT 1.505000 1.665000 1.835000 2.465000 ;
      RECT 2.870000 0.255000 3.160000 0.705000 ;
      RECT 2.870000 0.705000 4.055000 0.875000 ;
      RECT 2.930000 1.665000 3.180000 2.465000 ;
      RECT 3.790000 0.255000 4.055000 0.705000 ;
  END
END sky130_fd_sc_hd__o2111a_1
END LIBRARY
# Copyright 2020 The SkyWater PDK Authors
#
# Licensed under the Apache License, Version 2.0 (the "License");
# you may not use this file except in compliance with the License.
# You may obtain a copy of the License at
#
#     https://www.apache.org/licenses/LICENSE-2.0
#
# Unless required by applicable law or agreed to in writing, software
# distributed under the License is distributed on an "AS IS" BASIS,
# WITHOUT WARRANTIES OR CONDITIONS OF ANY KIND, either express or implied.
# See the License for the specific language governing permissions and
# limitations under the License.
#
# SPDX-License-Identifier: Apache-2.0

VERSION 5.5 ;
NAMESCASESENSITIVE ON ;
BUSBITCHARS "[]" ;
DIVIDERCHAR "/" ;
MACRO sky130_fd_sc_hd__o211a_1
  CLASS CORE ;
  SOURCE USER ;
  ORIGIN  0.000000  0.000000 ;
  SIZE  3.680000 BY  2.720000 ;
  SYMMETRY X Y R90 ;
  SITE unithd ;
  PIN A1
    ANTENNAGATEAREA  0.247500 ;
    DIRECTION INPUT ;
    USE SIGNAL ;
    PORT
      LAYER li1 ;
        RECT 1.300000 1.075000 1.720000 1.275000 ;
    END
  END A1
  PIN A2
    ANTENNAGATEAREA  0.247500 ;
    DIRECTION INPUT ;
    USE SIGNAL ;
    PORT
      LAYER li1 ;
        RECT 1.890000 1.075000 2.220000 1.275000 ;
    END
  END A2
  PIN B1
    ANTENNAGATEAREA  0.247500 ;
    DIRECTION INPUT ;
    USE SIGNAL ;
    PORT
      LAYER li1 ;
        RECT 2.390000 1.075000 2.720000 1.275000 ;
    END
  END B1
  PIN C1
    ANTENNAGATEAREA  0.247500 ;
    DIRECTION INPUT ;
    USE SIGNAL ;
    PORT
      LAYER li1 ;
        RECT 3.245000 1.075000 3.595000 1.325000 ;
    END
  END C1
  PIN X
    ANTENNADIFFAREA  0.429000 ;
    DIRECTION OUTPUT ;
    USE SIGNAL ;
    PORT
      LAYER li1 ;
        RECT 0.085000 0.255000 0.425000 0.885000 ;
        RECT 0.085000 0.885000 0.260000 1.495000 ;
        RECT 0.085000 1.495000 0.425000 2.465000 ;
    END
  END X
  PIN VGND
    DIRECTION INOUT ;
    SHAPE ABUTMENT ;
    USE GROUND ;
    PORT
      LAYER li1 ;
        RECT 0.000000 -0.085000 3.680000 0.085000 ;
        RECT 0.595000  0.085000 0.845000 0.885000 ;
        RECT 1.535000  0.085000 1.760000 0.545000 ;
    END
    PORT
      LAYER met1 ;
        RECT 0.000000 -0.240000 3.680000 0.240000 ;
    END
  END VGND
  PIN VPWR
    DIRECTION INOUT ;
    SHAPE ABUTMENT ;
    USE POWER ;
    PORT
      LAYER li1 ;
        RECT 0.000000 2.635000 3.680000 2.805000 ;
        RECT 0.595000 1.495000 0.765000 2.635000 ;
        RECT 1.035000 1.835000 1.285000 2.635000 ;
        RECT 2.560000 1.835000 2.890000 2.635000 ;
    END
    PORT
      LAYER met1 ;
        RECT 0.000000 2.480000 3.680000 2.960000 ;
    END
  END VPWR
  OBS
    LAYER li1 ;
      RECT 0.430000 1.075000 1.125000 1.245000 ;
      RECT 0.955000 1.245000 1.125000 1.495000 ;
      RECT 0.955000 1.495000 3.390000 1.665000 ;
      RECT 1.035000 0.255000 1.365000 0.735000 ;
      RECT 1.035000 0.735000 2.260000 0.905000 ;
      RECT 1.930000 0.255000 2.260000 0.735000 ;
      RECT 1.930000 1.665000 2.260000 2.465000 ;
      RECT 2.890000 0.255000 3.390000 0.865000 ;
      RECT 2.890000 0.865000 3.060000 1.495000 ;
      RECT 3.060000 1.665000 3.390000 2.465000 ;
  END
END sky130_fd_sc_hd__o211a_1
END LIBRARY
# Copyright 2020 The SkyWater PDK Authors
#
# Licensed under the Apache License, Version 2.0 (the "License");
# you may not use this file except in compliance with the License.
# You may obtain a copy of the License at
#
#     https://www.apache.org/licenses/LICENSE-2.0
#
# Unless required by applicable law or agreed to in writing, software
# distributed under the License is distributed on an "AS IS" BASIS,
# WITHOUT WARRANTIES OR CONDITIONS OF ANY KIND, either express or implied.
# See the License for the specific language governing permissions and
# limitations under the License.
#
# SPDX-License-Identifier: Apache-2.0

VERSION 5.5 ;
NAMESCASESENSITIVE ON ;
BUSBITCHARS "[]" ;
DIVIDERCHAR "/" ;
MACRO sky130_fd_sc_hd__o211ai_1
  CLASS CORE ;
  SOURCE USER ;
  ORIGIN  0.000000  0.000000 ;
  SIZE  2.760000 BY  2.720000 ;
  SYMMETRY X Y R90 ;
  SITE unithd ;
  PIN A1
    ANTENNAGATEAREA  0.247500 ;
    DIRECTION INPUT ;
    USE SIGNAL ;
    PORT
      LAYER li1 ;
        RECT 0.085000 0.995000 0.395000 1.325000 ;
    END
  END A1
  PIN A2
    ANTENNAGATEAREA  0.247500 ;
    DIRECTION INPUT ;
    USE SIGNAL ;
    PORT
      LAYER li1 ;
        RECT 0.605000 0.995000 0.980000 1.325000 ;
        RECT 0.605000 1.325000 0.775000 2.250000 ;
    END
  END A2
  PIN B1
    ANTENNAGATEAREA  0.247500 ;
    DIRECTION INPUT ;
    USE SIGNAL ;
    PORT
      LAYER li1 ;
        RECT 1.300000 0.995000 1.795000 1.325000 ;
        RECT 1.470000 1.325000 1.795000 1.615000 ;
    END
  END B1
  PIN C1
    ANTENNAGATEAREA  0.247500 ;
    DIRECTION INPUT ;
    USE SIGNAL ;
    PORT
      LAYER li1 ;
        RECT 1.970000 1.075000 2.300000 1.615000 ;
    END
  END C1
  PIN Y
    ANTENNADIFFAREA  1.418250 ;
    DIRECTION OUTPUT ;
    USE SIGNAL ;
    PORT
      LAYER li1 ;
        RECT 0.945000 1.595000 1.275000 1.815000 ;
        RECT 0.945000 1.815000 2.675000 2.045000 ;
        RECT 0.945000 2.045000 1.275000 2.445000 ;
        RECT 1.965000 0.255000 2.675000 0.845000 ;
        RECT 1.975000 2.045000 2.675000 2.465000 ;
        RECT 2.470000 0.845000 2.675000 1.815000 ;
    END
  END Y
  PIN VGND
    DIRECTION INOUT ;
    SHAPE ABUTMENT ;
    USE GROUND ;
    PORT
      LAYER li1 ;
        RECT 0.000000 -0.085000 2.760000 0.085000 ;
        RECT 0.595000  0.085000 0.925000 0.445000 ;
    END
    PORT
      LAYER met1 ;
        RECT 0.000000 -0.240000 2.760000 0.240000 ;
    END
  END VGND
  PIN VPWR
    DIRECTION INOUT ;
    SHAPE ABUTMENT ;
    USE POWER ;
    PORT
      LAYER li1 ;
        RECT 0.000000 2.635000 2.760000 2.805000 ;
        RECT 0.095000 1.575000 0.425000 2.635000 ;
        RECT 1.445000 2.275000 1.775000 2.635000 ;
    END
    PORT
      LAYER met1 ;
        RECT 0.000000 2.480000 2.760000 2.960000 ;
    END
  END VPWR
  OBS
    LAYER li1 ;
      RECT 0.095000 0.255000 0.425000 0.615000 ;
      RECT 0.095000 0.615000 1.455000 0.825000 ;
      RECT 1.125000 0.255000 1.455000 0.615000 ;
  END
END sky130_fd_sc_hd__o211ai_1
END LIBRARY
# Copyright 2020 The SkyWater PDK Authors
#
# Licensed under the Apache License, Version 2.0 (the "License");
# you may not use this file except in compliance with the License.
# You may obtain a copy of the License at
#
#     https://www.apache.org/licenses/LICENSE-2.0
#
# Unless required by applicable law or agreed to in writing, software
# distributed under the License is distributed on an "AS IS" BASIS,
# WITHOUT WARRANTIES OR CONDITIONS OF ANY KIND, either express or implied.
# See the License for the specific language governing permissions and
# limitations under the License.
#
# SPDX-License-Identifier: Apache-2.0

VERSION 5.5 ;
NAMESCASESENSITIVE ON ;
BUSBITCHARS "[]" ;
DIVIDERCHAR "/" ;
MACRO sky130_fd_sc_hd__o21a_1
  CLASS CORE ;
  SOURCE USER ;
  ORIGIN  0.000000  0.000000 ;
  SIZE  2.760000 BY  2.720000 ;
  SYMMETRY X Y R90 ;
  SITE unithd ;
  PIN A1
    ANTENNAGATEAREA  0.247500 ;
    DIRECTION INPUT ;
    USE SIGNAL ;
    PORT
      LAYER li1 ;
        RECT 2.345000 1.075000 2.675000 1.275000 ;
        RECT 2.445000 1.275000 2.675000 1.615000 ;
    END
  END A1
  PIN A2
    ANTENNAGATEAREA  0.247500 ;
    DIRECTION INPUT ;
    USE SIGNAL ;
    PORT
      LAYER li1 ;
        RECT 1.705000 1.075000 2.035000 1.095000 ;
        RECT 1.705000 1.095000 2.155000 1.275000 ;
        RECT 1.940000 1.275000 2.155000 2.390000 ;
    END
  END A2
  PIN B1
    ANTENNAGATEAREA  0.247500 ;
    DIRECTION INPUT ;
    USE SIGNAL ;
    PORT
      LAYER li1 ;
        RECT 1.065000 1.075000 1.535000 1.305000 ;
    END
  END B1
  PIN X
    ANTENNADIFFAREA  0.449000 ;
    DIRECTION OUTPUT ;
    USE SIGNAL ;
    PORT
      LAYER li1 ;
        RECT 0.085000 0.255000 0.425000 1.030000 ;
        RECT 0.085000 1.030000 0.365000 2.465000 ;
    END
  END X
  PIN VGND
    DIRECTION INOUT ;
    SHAPE ABUTMENT ;
    USE GROUND ;
    PORT
      LAYER li1 ;
        RECT 0.000000 -0.085000 2.760000 0.085000 ;
        RECT 0.595000  0.085000 0.765000 0.545000 ;
        RECT 1.995000  0.085000 2.165000 0.545000 ;
    END
    PORT
      LAYER met1 ;
        RECT 0.000000 -0.240000 2.760000 0.240000 ;
    END
  END VGND
  PIN VPWR
    DIRECTION INOUT ;
    SHAPE ABUTMENT ;
    USE POWER ;
    PORT
      LAYER li1 ;
        RECT 0.000000 2.635000 2.760000 2.805000 ;
        RECT 0.535000 1.860000 1.245000 2.635000 ;
        RECT 2.335000 1.915000 2.665000 2.635000 ;
    END
    PORT
      LAYER met1 ;
        RECT 0.000000 2.480000 2.760000 2.960000 ;
    END
  END VPWR
  OBS
    LAYER li1 ;
      RECT 0.595000 0.715000 1.305000 0.905000 ;
      RECT 0.595000 0.905000 0.880000 1.475000 ;
      RECT 0.595000 1.475000 1.745000 1.690000 ;
      RECT 1.005000 0.255000 1.365000 0.520000 ;
      RECT 1.005000 0.520000 1.360000 0.525000 ;
      RECT 1.005000 0.525000 1.355000 0.535000 ;
      RECT 1.005000 0.535000 1.350000 0.540000 ;
      RECT 1.005000 0.540000 1.345000 0.550000 ;
      RECT 1.005000 0.550000 1.340000 0.555000 ;
      RECT 1.005000 0.555000 1.330000 0.565000 ;
      RECT 1.005000 0.565000 1.320000 0.575000 ;
      RECT 1.005000 0.575000 1.305000 0.715000 ;
      RECT 1.415000 1.690000 1.745000 2.465000 ;
      RECT 1.495000 0.635000 1.825000 0.715000 ;
      RECT 1.495000 0.715000 2.675000 0.905000 ;
      RECT 2.335000 0.255000 2.675000 0.715000 ;
  END
END sky130_fd_sc_hd__o21a_1
END LIBRARY
# Copyright 2020 The SkyWater PDK Authors
#
# Licensed under the Apache License, Version 2.0 (the "License");
# you may not use this file except in compliance with the License.
# You may obtain a copy of the License at
#
#     https://www.apache.org/licenses/LICENSE-2.0
#
# Unless required by applicable law or agreed to in writing, software
# distributed under the License is distributed on an "AS IS" BASIS,
# WITHOUT WARRANTIES OR CONDITIONS OF ANY KIND, either express or implied.
# See the License for the specific language governing permissions and
# limitations under the License.
#
# SPDX-License-Identifier: Apache-2.0

VERSION 5.5 ;
NAMESCASESENSITIVE ON ;
BUSBITCHARS "[]" ;
DIVIDERCHAR "/" ;
MACRO sky130_fd_sc_hd__o21ai_0
  CLASS CORE ;
  SOURCE USER ;
  ORIGIN  0.000000  0.000000 ;
  SIZE  1.840000 BY  2.720000 ;
  SYMMETRY X Y R90 ;
  SITE unithd ;
  PIN A1
    ANTENNAGATEAREA  0.159000 ;
    DIRECTION INPUT ;
    USE SIGNAL ;
    PORT
      LAYER li1 ;
        RECT 0.085000 0.955000 0.415000 1.615000 ;
    END
  END A1
  PIN A2
    ANTENNAGATEAREA  0.159000 ;
    DIRECTION INPUT ;
    USE SIGNAL ;
    PORT
      LAYER li1 ;
        RECT 0.605000 1.100000 1.005000 1.340000 ;
        RECT 0.605000 1.340000 0.775000 1.645000 ;
    END
  END A2
  PIN B1
    ANTENNAGATEAREA  0.159000 ;
    DIRECTION INPUT ;
    USE SIGNAL ;
    PORT
      LAYER li1 ;
        RECT 1.515000 1.355000 1.730000 1.685000 ;
    END
  END B1
  PIN Y
    ANTENNADIFFAREA  0.290500 ;
    DIRECTION OUTPUT ;
    USE SIGNAL ;
    PORT
      LAYER li1 ;
        RECT 0.965000 1.510000 1.345000 1.680000 ;
        RECT 0.965000 1.680000 1.300000 2.465000 ;
        RECT 1.175000 0.955000 1.740000 1.125000 ;
        RECT 1.175000 1.125000 1.345000 1.510000 ;
        RECT 1.455000 0.280000 1.740000 0.955000 ;
    END
  END Y
  PIN VGND
    DIRECTION INOUT ;
    SHAPE ABUTMENT ;
    USE GROUND ;
    PORT
      LAYER li1 ;
        RECT 0.000000 -0.085000 1.840000 0.085000 ;
        RECT 0.550000  0.085000 0.880000 0.445000 ;
    END
    PORT
      LAYER met1 ;
        RECT 0.000000 -0.240000 1.840000 0.240000 ;
    END
  END VGND
  PIN VPWR
    DIRECTION INOUT ;
    SHAPE ABUTMENT ;
    USE POWER ;
    PORT
      LAYER li1 ;
        RECT 0.000000 2.635000 1.840000 2.805000 ;
        RECT 0.145000 1.825000 0.475000 2.635000 ;
        RECT 1.470000 1.855000 1.725000 2.635000 ;
    END
    PORT
      LAYER met1 ;
        RECT 0.000000 2.480000 1.840000 2.960000 ;
    END
  END VPWR
  OBS
    LAYER li1 ;
      RECT 0.120000 0.280000 0.380000 0.615000 ;
      RECT 0.120000 0.615000 1.285000 0.785000 ;
      RECT 1.050000 0.280000 1.285000 0.615000 ;
  END
END sky130_fd_sc_hd__o21ai_0
END LIBRARY
# Copyright 2020 The SkyWater PDK Authors
#
# Licensed under the Apache License, Version 2.0 (the "License");
# you may not use this file except in compliance with the License.
# You may obtain a copy of the License at
#
#     https://www.apache.org/licenses/LICENSE-2.0
#
# Unless required by applicable law or agreed to in writing, software
# distributed under the License is distributed on an "AS IS" BASIS,
# WITHOUT WARRANTIES OR CONDITIONS OF ANY KIND, either express or implied.
# See the License for the specific language governing permissions and
# limitations under the License.
#
# SPDX-License-Identifier: Apache-2.0

VERSION 5.5 ;
NAMESCASESENSITIVE ON ;
BUSBITCHARS "[]" ;
DIVIDERCHAR "/" ;
MACRO sky130_fd_sc_hd__o21bai_1
  CLASS CORE ;
  SOURCE USER ;
  ORIGIN  0.000000  0.000000 ;
  SIZE  2.760000 BY  2.720000 ;
  SYMMETRY X Y R90 ;
  SITE unithd ;
  PIN A1
    ANTENNAGATEAREA  0.247500 ;
    DIRECTION INPUT ;
    USE SIGNAL ;
    PORT
      LAYER li1 ;
        RECT 2.195000 1.075000 2.675000 1.285000 ;
    END
  END A1
  PIN A2
    ANTENNAGATEAREA  0.247500 ;
    DIRECTION INPUT ;
    USE SIGNAL ;
    PORT
      LAYER li1 ;
        RECT 1.525000 1.075000 2.025000 1.285000 ;
    END
  END A2
  PIN B1_N
    ANTENNAGATEAREA  0.126000 ;
    DIRECTION INPUT ;
    USE SIGNAL ;
    PORT
      LAYER li1 ;
        RECT 0.085000 0.995000 0.535000 1.345000 ;
        RECT 0.085000 1.345000 0.355000 2.445000 ;
    END
  END B1_N
  PIN Y
    ANTENNADIFFAREA  0.474000 ;
    DIRECTION OUTPUT ;
    USE SIGNAL ;
    PORT
      LAYER li1 ;
        RECT 1.115000 0.255000 1.285000 0.645000 ;
        RECT 1.115000 0.645000 1.355000 0.825000 ;
        RECT 1.185000 0.825000 1.355000 1.455000 ;
        RECT 1.185000 1.455000 1.795000 1.625000 ;
        RECT 1.470000 1.625000 1.795000 2.465000 ;
    END
  END Y
  PIN VGND
    DIRECTION INOUT ;
    SHAPE ABUTMENT ;
    USE GROUND ;
    PORT
      LAYER li1 ;
        RECT 0.000000 -0.085000 2.760000 0.085000 ;
        RECT 0.085000  0.085000 0.360000 0.825000 ;
        RECT 1.995000  0.085000 2.165000 0.555000 ;
    END
    PORT
      LAYER met1 ;
        RECT 0.000000 -0.240000 2.760000 0.240000 ;
    END
  END VGND
  PIN VPWR
    DIRECTION INOUT ;
    SHAPE ABUTMENT ;
    USE POWER ;
    PORT
      LAYER li1 ;
        RECT 0.000000 2.635000 2.760000 2.805000 ;
        RECT 0.970000 1.875000 1.300000 2.635000 ;
        RECT 2.270000 1.535000 2.645000 2.635000 ;
    END
    PORT
      LAYER met1 ;
        RECT 0.000000 2.480000 2.760000 2.960000 ;
    END
  END VPWR
  OBS
    LAYER li1 ;
      RECT 0.525000 1.535000 1.015000 1.705000 ;
      RECT 0.525000 1.705000 0.800000 2.210000 ;
      RECT 0.580000 0.495000 0.770000 0.655000 ;
      RECT 0.580000 0.655000 0.890000 0.825000 ;
      RECT 0.720000 0.825000 0.890000 0.995000 ;
      RECT 0.720000 0.995000 1.015000 1.535000 ;
      RECT 1.490000 0.255000 1.820000 0.485000 ;
      RECT 1.570000 0.485000 1.740000 0.735000 ;
      RECT 1.570000 0.735000 2.665000 0.905000 ;
      RECT 2.335000 0.270000 2.665000 0.735000 ;
  END
END sky130_fd_sc_hd__o21bai_1
END LIBRARY
# Copyright 2020 The SkyWater PDK Authors
#
# Licensed under the Apache License, Version 2.0 (the "License");
# you may not use this file except in compliance with the License.
# You may obtain a copy of the License at
#
#     https://www.apache.org/licenses/LICENSE-2.0
#
# Unless required by applicable law or agreed to in writing, software
# distributed under the License is distributed on an "AS IS" BASIS,
# WITHOUT WARRANTIES OR CONDITIONS OF ANY KIND, either express or implied.
# See the License for the specific language governing permissions and
# limitations under the License.
#
# SPDX-License-Identifier: Apache-2.0

VERSION 5.5 ;
NAMESCASESENSITIVE ON ;
BUSBITCHARS "[]" ;
DIVIDERCHAR "/" ;
MACRO sky130_fd_sc_hd__o22ai_1
  CLASS CORE ;
  SOURCE USER ;
  ORIGIN  0.000000  0.000000 ;
  SIZE  2.300000 BY  2.720000 ;
  SYMMETRY X Y R90 ;
  SITE unithd ;
  PIN A1
    ANTENNAGATEAREA  0.247500 ;
    DIRECTION INPUT ;
    USE SIGNAL ;
    PORT
      LAYER li1 ;
        RECT 1.755000 1.075000 2.215000 1.275000 ;
    END
  END A1
  PIN A2
    ANTENNAGATEAREA  0.247500 ;
    DIRECTION INPUT ;
    USE SIGNAL ;
    PORT
      LAYER li1 ;
        RECT 1.220000 1.075000 1.585000 1.245000 ;
        RECT 1.405000 1.245000 1.585000 1.445000 ;
        RECT 1.405000 1.445000 1.725000 1.615000 ;
        RECT 1.525000 1.615000 1.725000 2.405000 ;
    END
  END A2
  PIN B1
    ANTENNAGATEAREA  0.247500 ;
    DIRECTION INPUT ;
    USE SIGNAL ;
    PORT
      LAYER li1 ;
        RECT 0.085000 0.665000 0.325000 1.990000 ;
    END
  END B1
  PIN B2
    ANTENNAGATEAREA  0.247500 ;
    DIRECTION INPUT ;
    USE SIGNAL ;
    PORT
      LAYER li1 ;
        RECT 0.835000 0.995000 1.005000 1.415000 ;
        RECT 0.835000 1.415000 1.235000 1.665000 ;
    END
  END B2
  PIN Y
    ANTENNADIFFAREA  0.650250 ;
    DIRECTION OUTPUT ;
    USE SIGNAL ;
    PORT
      LAYER li1 ;
        RECT 0.495000 0.645000 0.845000 0.825000 ;
        RECT 0.495000 0.825000 0.665000 1.835000 ;
        RECT 0.495000 1.835000 1.335000 2.045000 ;
        RECT 0.835000 2.045000 1.335000 2.465000 ;
    END
  END Y
  PIN VGND
    DIRECTION INOUT ;
    SHAPE ABUTMENT ;
    USE GROUND ;
    PORT
      LAYER li1 ;
        RECT 0.000000 -0.085000 2.300000 0.085000 ;
        RECT 1.535000  0.085000 1.705000 0.525000 ;
    END
    PORT
      LAYER met1 ;
        RECT 0.000000 -0.240000 2.300000 0.240000 ;
    END
  END VGND
  PIN VPWR
    DIRECTION INOUT ;
    SHAPE ABUTMENT ;
    USE POWER ;
    PORT
      LAYER li1 ;
        RECT 0.000000 2.635000 2.300000 2.805000 ;
        RECT 0.135000 2.175000 0.345000 2.635000 ;
        RECT 1.895000 1.455000 2.215000 2.635000 ;
    END
    PORT
      LAYER met1 ;
        RECT 0.000000 2.480000 2.300000 2.960000 ;
    END
  END VPWR
  OBS
    LAYER li1 ;
      RECT 0.085000 0.295000 1.345000 0.475000 ;
      RECT 1.015000 0.475000 1.345000 0.695000 ;
      RECT 1.015000 0.695000 2.215000 0.825000 ;
      RECT 1.185000 0.825000 2.215000 0.865000 ;
      RECT 1.875000 0.280000 2.215000 0.695000 ;
  END
END sky130_fd_sc_hd__o22ai_1
END LIBRARY
# Copyright 2020 The SkyWater PDK Authors
#
# Licensed under the Apache License, Version 2.0 (the "License");
# you may not use this file except in compliance with the License.
# You may obtain a copy of the License at
#
#     https://www.apache.org/licenses/LICENSE-2.0
#
# Unless required by applicable law or agreed to in writing, software
# distributed under the License is distributed on an "AS IS" BASIS,
# WITHOUT WARRANTIES OR CONDITIONS OF ANY KIND, either express or implied.
# See the License for the specific language governing permissions and
# limitations under the License.
#
# SPDX-License-Identifier: Apache-2.0

VERSION 5.5 ;
NAMESCASESENSITIVE ON ;
BUSBITCHARS "[]" ;
DIVIDERCHAR "/" ;
MACRO sky130_fd_sc_hd__o31a_1
  CLASS CORE ;
  SOURCE USER ;
  ORIGIN  0.000000  0.000000 ;
  SIZE  3.220000 BY  2.720000 ;
  SYMMETRY X Y R90 ;
  SITE unithd ;
  PIN A1
    ANTENNAGATEAREA  0.247500 ;
    DIRECTION INPUT ;
    USE SIGNAL ;
    PORT
      LAYER li1 ;
        RECT 0.905000 0.995000 1.295000 1.275000 ;
    END
  END A1
  PIN A2
    ANTENNAGATEAREA  0.247500 ;
    DIRECTION INPUT ;
    USE SIGNAL ;
    PORT
      LAYER li1 ;
        RECT 1.480000 0.995000 1.725000 1.325000 ;
        RECT 1.525000 1.325000 1.725000 2.125000 ;
    END
  END A2
  PIN A3
    ANTENNAGATEAREA  0.247500 ;
    DIRECTION INPUT ;
    USE SIGNAL ;
    PORT
      LAYER li1 ;
        RECT 1.925000 0.995000 2.175000 2.125000 ;
    END
  END A3
  PIN B1
    ANTENNAGATEAREA  0.247500 ;
    DIRECTION INPUT ;
    USE SIGNAL ;
    PORT
      LAYER li1 ;
        RECT 2.390000 0.995000 2.795000 1.325000 ;
    END
  END B1
  PIN X
    ANTENNADIFFAREA  0.594000 ;
    DIRECTION OUTPUT ;
    USE SIGNAL ;
    PORT
      LAYER li1 ;
        RECT 0.085000 0.265000 0.525000 0.825000 ;
        RECT 0.085000 0.825000 0.395000 1.835000 ;
        RECT 0.085000 1.835000 0.525000 2.465000 ;
    END
  END X
  PIN VGND
    DIRECTION INOUT ;
    SHAPE ABUTMENT ;
    USE GROUND ;
    PORT
      LAYER li1 ;
        RECT 0.000000 -0.085000 3.220000 0.085000 ;
        RECT 0.695000  0.085000 1.145000 0.825000 ;
        RECT 1.655000  0.085000 2.075000 0.485000 ;
    END
    PORT
      LAYER met1 ;
        RECT 0.000000 -0.240000 3.220000 0.240000 ;
    END
  END VGND
  PIN VPWR
    DIRECTION INOUT ;
    SHAPE ABUTMENT ;
    USE POWER ;
    PORT
      LAYER li1 ;
        RECT 0.000000 2.635000 3.220000 2.805000 ;
        RECT 0.700000 1.785000 1.015000 2.635000 ;
        RECT 2.795000 1.835000 3.125000 2.635000 ;
    END
    PORT
      LAYER met1 ;
        RECT 0.000000 2.480000 3.220000 2.960000 ;
    END
  END VPWR
  OBS
    LAYER li1 ;
      RECT 0.565000 0.995000 0.735000 1.445000 ;
      RECT 0.565000 1.445000 1.355000 1.615000 ;
      RECT 1.185000 1.615000 1.355000 2.295000 ;
      RECT 1.185000 2.295000 2.615000 2.465000 ;
      RECT 1.315000 0.255000 1.485000 0.655000 ;
      RECT 1.315000 0.655000 2.475000 0.825000 ;
      RECT 2.245000 0.255000 2.475000 0.655000 ;
      RECT 2.365000 1.495000 3.135000 1.665000 ;
      RECT 2.365000 1.665000 2.615000 2.295000 ;
      RECT 2.645000 0.255000 3.135000 0.825000 ;
      RECT 2.965000 0.825000 3.135000 1.495000 ;
  END
END sky130_fd_sc_hd__o31a_1
END LIBRARY
# Copyright 2020 The SkyWater PDK Authors
#
# Licensed under the Apache License, Version 2.0 (the "License");
# you may not use this file except in compliance with the License.
# You may obtain a copy of the License at
#
#     https://www.apache.org/licenses/LICENSE-2.0
#
# Unless required by applicable law or agreed to in writing, software
# distributed under the License is distributed on an "AS IS" BASIS,
# WITHOUT WARRANTIES OR CONDITIONS OF ANY KIND, either express or implied.
# See the License for the specific language governing permissions and
# limitations under the License.
#
# SPDX-License-Identifier: Apache-2.0

VERSION 5.5 ;
NAMESCASESENSITIVE ON ;
BUSBITCHARS "[]" ;
DIVIDERCHAR "/" ;
MACRO sky130_fd_sc_hd__or3_1
  CLASS CORE ;
  SOURCE USER ;
  ORIGIN  0.000000  0.000000 ;
  SIZE  2.300000 BY  2.720000 ;
  SYMMETRY X Y R90 ;
  SITE unithd ;
  PIN A
    ANTENNAGATEAREA  0.126000 ;
    DIRECTION INPUT ;
    USE SIGNAL ;
    PORT
      LAYER li1 ;
        RECT 0.600000 0.995000 1.425000 1.325000 ;
        RECT 0.600000 1.325000 0.795000 1.615000 ;
    END
  END A
  PIN B
    ANTENNAGATEAREA  0.126000 ;
    DIRECTION INPUT ;
    USE SIGNAL ;
    PORT
      LAYER li1 ;
        RECT 0.085000 2.125000 1.275000 2.415000 ;
    END
  END B
  PIN C
    ANTENNAGATEAREA  0.126000 ;
    DIRECTION INPUT ;
    USE SIGNAL ;
    PORT
      LAYER li1 ;
        RECT 0.085000 0.995000 0.430000 1.325000 ;
    END
  END C
  PIN X
    ANTENNADIFFAREA  0.462000 ;
    DIRECTION OUTPUT ;
    USE SIGNAL ;
    PORT
      LAYER li1 ;
        RECT 1.935000 0.415000 2.210000 0.760000 ;
        RECT 1.935000 1.495000 2.210000 2.465000 ;
        RECT 2.040000 0.760000 2.210000 1.495000 ;
    END
  END X
  PIN VGND
    DIRECTION INOUT ;
    SHAPE ABUTMENT ;
    USE GROUND ;
    PORT
      LAYER li1 ;
        RECT 0.000000 -0.085000 2.300000 0.085000 ;
        RECT 0.525000  0.085000 0.855000 0.485000 ;
        RECT 1.365000  0.085000 1.745000 0.485000 ;
    END
    PORT
      LAYER met1 ;
        RECT 0.000000 -0.240000 2.300000 0.240000 ;
    END
  END VGND
  PIN VPWR
    DIRECTION INOUT ;
    SHAPE ABUTMENT ;
    USE POWER ;
    PORT
      LAYER li1 ;
        RECT 0.000000 2.635000 2.300000 2.805000 ;
        RECT 1.445000 1.835000 1.725000 2.635000 ;
    END
    PORT
      LAYER met1 ;
        RECT 0.000000 2.480000 2.300000 2.960000 ;
    END
  END VPWR
  OBS
    LAYER li1 ;
      RECT 0.100000 0.305000 0.355000 0.655000 ;
      RECT 0.100000 0.655000 1.765000 0.825000 ;
      RECT 0.105000 1.495000 0.430000 1.785000 ;
      RECT 0.105000 1.785000 1.275000 1.955000 ;
      RECT 1.025000 0.305000 1.195000 0.655000 ;
      RECT 1.105000 1.495000 1.765000 1.665000 ;
      RECT 1.105000 1.665000 1.275000 1.785000 ;
      RECT 1.595000 0.825000 1.765000 0.995000 ;
      RECT 1.595000 0.995000 1.870000 1.325000 ;
      RECT 1.595000 1.325000 1.765000 1.495000 ;
  END
END sky130_fd_sc_hd__or3_1
END LIBRARY
# Copyright 2020 The SkyWater PDK Authors
#
# Licensed under the Apache License, Version 2.0 (the "License");
# you may not use this file except in compliance with the License.
# You may obtain a copy of the License at
#
#     https://www.apache.org/licenses/LICENSE-2.0
#
# Unless required by applicable law or agreed to in writing, software
# distributed under the License is distributed on an "AS IS" BASIS,
# WITHOUT WARRANTIES OR CONDITIONS OF ANY KIND, either express or implied.
# See the License for the specific language governing permissions and
# limitations under the License.
#
# SPDX-License-Identifier: Apache-2.0

VERSION 5.5 ;
NAMESCASESENSITIVE ON ;
BUSBITCHARS "[]" ;
DIVIDERCHAR "/" ;
MACRO sky130_fd_sc_hd__xnor2_1
  CLASS CORE ;
  SOURCE USER ;
  ORIGIN  0.000000  0.000000 ;
  SIZE  3.220000 BY  2.720000 ;
  SYMMETRY X Y R90 ;
  SITE unithd ;
  PIN A
    ANTENNAGATEAREA  0.495000 ;
    DIRECTION INPUT ;
    USE SIGNAL ;
    PORT
      LAYER li1 ;
        RECT 0.930000 1.075000 1.625000 1.275000 ;
    END
  END A
  PIN B
    ANTENNAGATEAREA  0.495000 ;
    DIRECTION INPUT ;
    USE SIGNAL ;
    PORT
      LAYER li1 ;
        RECT 0.425000 0.995000 0.670000 1.445000 ;
        RECT 0.425000 1.445000 1.965000 1.615000 ;
        RECT 1.795000 1.075000 2.395000 1.245000 ;
        RECT 1.795000 1.245000 1.965000 1.445000 ;
    END
  END B
  PIN Y
    ANTENNADIFFAREA  0.525000 ;
    DIRECTION OUTPUT ;
    USE SIGNAL ;
    PORT
      LAYER li1 ;
        RECT 2.265000 2.125000 2.645000 2.295000 ;
        RECT 2.475000 1.755000 3.135000 1.955000 ;
        RECT 2.475000 1.955000 2.645000 2.125000 ;
        RECT 2.815000 0.345000 3.135000 0.825000 ;
        RECT 2.965000 0.825000 3.135000 1.755000 ;
    END
  END Y
  PIN VGND
    DIRECTION INOUT ;
    SHAPE ABUTMENT ;
    USE GROUND ;
    PORT
      LAYER li1 ;
        RECT 0.000000 -0.085000 3.220000 0.085000 ;
        RECT 1.055000  0.085000 1.225000 0.905000 ;
        RECT 1.895000  0.085000 2.245000 0.475000 ;
    END
    PORT
      LAYER met1 ;
        RECT 0.000000 -0.240000 3.220000 0.240000 ;
    END
  END VGND
  PIN VPWR
    DIRECTION INOUT ;
    SHAPE ABUTMENT ;
    USE POWER ;
    PORT
      LAYER li1 ;
        RECT 0.000000 2.635000 3.220000 2.805000 ;
        RECT 0.085000 2.125000 0.385000 2.635000 ;
        RECT 1.055000 2.125000 1.685000 2.635000 ;
        RECT 2.815000 2.125000 3.115000 2.635000 ;
    END
    PORT
      LAYER met1 ;
        RECT 0.000000 2.480000 3.220000 2.960000 ;
    END
  END VPWR
  OBS
    LAYER li1 ;
      RECT 0.085000 0.280000 0.550000 0.825000 ;
      RECT 0.085000 0.825000 0.255000 1.785000 ;
      RECT 0.085000 1.785000 2.305000 1.955000 ;
      RECT 0.555000 1.955000 0.885000 2.465000 ;
      RECT 1.395000 0.255000 1.725000 0.735000 ;
      RECT 1.395000 0.735000 2.645000 0.825000 ;
      RECT 1.395000 0.825000 2.305000 0.905000 ;
      RECT 2.135000 0.655000 2.645000 0.735000 ;
      RECT 2.135000 1.415000 2.795000 1.585000 ;
      RECT 2.135000 1.585000 2.305000 1.785000 ;
      RECT 2.415000 0.255000 2.645000 0.655000 ;
      RECT 2.625000 0.995000 2.795000 1.415000 ;
  END
END sky130_fd_sc_hd__xnor2_1
END LIBRARY
# Copyright 2020 The SkyWater PDK Authors
#
# Licensed under the Apache License, Version 2.0 (the "License");
# you may not use this file except in compliance with the License.
# You may obtain a copy of the License at
#
#     https://www.apache.org/licenses/LICENSE-2.0
#
# Unless required by applicable law or agreed to in writing, software
# distributed under the License is distributed on an "AS IS" BASIS,
# WITHOUT WARRANTIES OR CONDITIONS OF ANY KIND, either express or implied.
# See the License for the specific language governing permissions and
# limitations under the License.
#
# SPDX-License-Identifier: Apache-2.0

VERSION 5.5 ;
NAMESCASESENSITIVE ON ;
BUSBITCHARS "[]" ;
DIVIDERCHAR "/" ;
MACRO sky130_fd_sc_hd__xnor3_1
  CLASS CORE ;
  SOURCE USER ;
  ORIGIN  0.000000  0.000000 ;
  SIZE  8.280000 BY  2.720000 ;
  SYMMETRY X Y R90 ;
  SITE unithd ;
  PIN A
    ANTENNAGATEAREA  0.246000 ;
    DIRECTION INPUT ;
    USE SIGNAL ;
    PORT
      LAYER li1 ;
        RECT 7.045000 1.075000 7.455000 1.325000 ;
    END
  END A
  PIN B
    ANTENNAGATEAREA  0.661500 ;
    DIRECTION INPUT ;
    USE SIGNAL ;
    PORT
      LAYER li1 ;
        RECT 6.225000 0.995000 6.395000 1.445000 ;
        RECT 6.225000 1.445000 6.805000 1.615000 ;
    END
  END B
  PIN C
    ANTENNAGATEAREA  0.381000 ;
    DIRECTION INPUT ;
    USE SIGNAL ;
    PORT
      LAYER li1 ;
        RECT 1.615000 1.075000 2.180000 1.325000 ;
    END
  END C
  PIN X
    ANTENNADIFFAREA  0.449000 ;
    DIRECTION OUTPUT ;
    USE SIGNAL ;
    PORT
      LAYER li1 ;
        RECT 0.085000 0.350000 0.345000 0.925000 ;
        RECT 0.085000 0.925000 0.330000 1.440000 ;
        RECT 0.085000 1.440000 0.365000 2.465000 ;
    END
  END X
  PIN VGND
    DIRECTION INOUT ;
    SHAPE ABUTMENT ;
    USE GROUND ;
    PORT
      LAYER li1 ;
        RECT 0.000000 -0.085000 8.280000 0.085000 ;
        RECT 0.515000  0.085000 0.765000 0.525000 ;
        RECT 3.475000  0.085000 3.645000 0.865000 ;
        RECT 7.475000  0.085000 7.645000 0.565000 ;
    END
    PORT
      LAYER met1 ;
        RECT 0.000000 -0.240000 8.280000 0.240000 ;
    END
  END VGND
  PIN VPWR
    DIRECTION INOUT ;
    SHAPE ABUTMENT ;
    USE POWER ;
    PORT
      LAYER li1 ;
        RECT 0.000000 2.635000 8.280000 2.805000 ;
        RECT 0.535000 2.215000 0.870000 2.635000 ;
        RECT 3.225000 2.235000 3.555000 2.635000 ;
        RECT 7.395000 2.275000 7.730000 2.635000 ;
    END
    PORT
      LAYER met1 ;
        RECT 0.000000 2.480000 8.280000 2.960000 ;
    END
  END VPWR
  OBS
    LAYER li1 ;
      RECT 0.500000 0.995000 0.705000 1.325000 ;
      RECT 0.530000 0.695000 1.105000 0.865000 ;
      RECT 0.530000 0.865000 0.705000 0.995000 ;
      RECT 0.535000 1.325000 0.705000 1.875000 ;
      RECT 0.535000 1.875000 1.220000 2.045000 ;
      RECT 0.935000 0.255000 2.505000 0.425000 ;
      RECT 0.935000 0.425000 1.105000 0.695000 ;
      RECT 0.935000 1.535000 2.520000 1.705000 ;
      RECT 1.050000 2.045000 1.220000 2.235000 ;
      RECT 1.050000 2.235000 2.520000 2.405000 ;
      RECT 1.275000 0.595000 1.445000 1.535000 ;
      RECT 1.560000 1.895000 4.060000 2.065000 ;
      RECT 1.745000 0.625000 2.965000 0.795000 ;
      RECT 1.745000 0.795000 2.125000 0.905000 ;
      RECT 2.070000 0.425000 2.505000 0.455000 ;
      RECT 2.350000 0.995000 2.625000 1.325000 ;
      RECT 2.350000 1.325000 2.520000 1.535000 ;
      RECT 2.675000 0.285000 3.305000 0.455000 ;
      RECT 2.690000 1.525000 3.075000 1.695000 ;
      RECT 2.795000 0.795000 2.965000 1.375000 ;
      RECT 2.795000 1.375000 3.075000 1.525000 ;
      RECT 3.135000 0.455000 3.305000 1.035000 ;
      RECT 3.135000 1.035000 3.415000 1.205000 ;
      RECT 3.245000 1.205000 3.415000 1.895000 ;
      RECT 3.645000 1.445000 4.065000 1.715000 ;
      RECT 3.825000 0.415000 4.065000 1.445000 ;
      RECT 3.890000 2.065000 4.060000 2.275000 ;
      RECT 3.890000 2.275000 6.985000 2.445000 ;
      RECT 4.245000 0.265000 4.655000 0.485000 ;
      RECT 4.245000 0.485000 4.455000 0.595000 ;
      RECT 4.245000 0.595000 4.415000 2.105000 ;
      RECT 4.585000 0.720000 4.995000 0.825000 ;
      RECT 4.585000 0.825000 4.795000 0.890000 ;
      RECT 4.585000 0.890000 4.755000 2.275000 ;
      RECT 4.625000 0.655000 4.995000 0.720000 ;
      RECT 4.825000 0.320000 4.995000 0.655000 ;
      RECT 4.935000 1.445000 5.715000 1.615000 ;
      RECT 4.935000 1.615000 5.350000 2.045000 ;
      RECT 4.950000 0.995000 5.375000 1.270000 ;
      RECT 5.165000 0.630000 5.375000 0.995000 ;
      RECT 5.545000 0.255000 6.690000 0.425000 ;
      RECT 5.545000 0.425000 5.715000 1.445000 ;
      RECT 5.885000 0.595000 6.055000 1.935000 ;
      RECT 5.885000 1.935000 8.195000 2.105000 ;
      RECT 6.225000 0.425000 6.690000 0.465000 ;
      RECT 6.565000 0.730000 6.770000 0.945000 ;
      RECT 6.565000 0.945000 6.875000 1.275000 ;
      RECT 6.975000 1.495000 7.795000 1.705000 ;
      RECT 7.015000 0.295000 7.305000 0.735000 ;
      RECT 7.015000 0.735000 7.795000 0.750000 ;
      RECT 7.055000 0.750000 7.795000 0.905000 ;
      RECT 7.625000 0.905000 7.795000 0.995000 ;
      RECT 7.625000 0.995000 7.855000 1.325000 ;
      RECT 7.625000 1.325000 7.795000 1.495000 ;
      RECT 7.710000 1.875000 8.195000 1.935000 ;
      RECT 7.895000 0.255000 8.195000 0.585000 ;
      RECT 7.900000 2.105000 8.195000 2.465000 ;
      RECT 8.025000 0.585000 8.195000 1.875000 ;
    LAYER mcon ;
      RECT 2.905000 1.445000 3.075000 1.615000 ;
      RECT 3.825000 0.765000 3.995000 0.935000 ;
      RECT 4.285000 0.425000 4.455000 0.595000 ;
      RECT 5.205000 0.765000 5.375000 0.935000 ;
      RECT 5.205000 1.445000 5.375000 1.615000 ;
      RECT 6.585000 0.765000 6.755000 0.935000 ;
      RECT 7.045000 0.425000 7.215000 0.595000 ;
    LAYER met1 ;
      RECT 2.845000 1.415000 3.135000 1.460000 ;
      RECT 2.845000 1.460000 5.435000 1.600000 ;
      RECT 2.845000 1.600000 3.135000 1.645000 ;
      RECT 3.765000 0.735000 4.055000 0.780000 ;
      RECT 3.765000 0.780000 6.815000 0.920000 ;
      RECT 3.765000 0.920000 4.055000 0.965000 ;
      RECT 4.225000 0.395000 4.515000 0.440000 ;
      RECT 4.225000 0.440000 7.275000 0.580000 ;
      RECT 4.225000 0.580000 4.515000 0.625000 ;
      RECT 5.145000 0.735000 5.435000 0.780000 ;
      RECT 5.145000 0.920000 5.435000 0.965000 ;
      RECT 5.145000 1.415000 5.435000 1.460000 ;
      RECT 5.145000 1.600000 5.435000 1.645000 ;
      RECT 6.525000 0.735000 6.815000 0.780000 ;
      RECT 6.525000 0.920000 6.815000 0.965000 ;
      RECT 6.985000 0.395000 7.275000 0.440000 ;
      RECT 6.985000 0.580000 7.275000 0.625000 ;
  END
END sky130_fd_sc_hd__xnor3_1
END LIBRARY
# Copyright 2020 The SkyWater PDK Authors
#
# Licensed under the Apache License, Version 2.0 (the "License");
# you may not use this file except in compliance with the License.
# You may obtain a copy of the License at
#
#     https://www.apache.org/licenses/LICENSE-2.0
#
# Unless required by applicable law or agreed to in writing, software
# distributed under the License is distributed on an "AS IS" BASIS,
# WITHOUT WARRANTIES OR CONDITIONS OF ANY KIND, either express or implied.
# See the License for the specific language governing permissions and
# limitations under the License.
#
# SPDX-License-Identifier: Apache-2.0

VERSION 5.5 ;
NAMESCASESENSITIVE ON ;
BUSBITCHARS "[]" ;
DIVIDERCHAR "/" ;
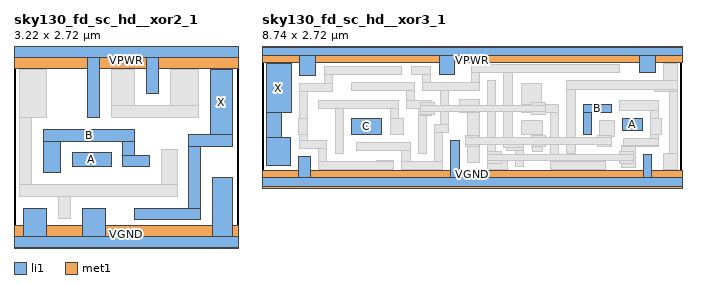
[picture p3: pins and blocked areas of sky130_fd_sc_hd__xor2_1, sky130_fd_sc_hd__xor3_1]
MACRO sky130_fd_sc_hd__xor2_1
  CLASS CORE ;
  SOURCE USER ;
  ORIGIN  0.000000  0.000000 ;
  SIZE  3.220000 BY  2.720000 ;
  SYMMETRY X Y R90 ;
  SITE unithd ;
  PIN A
    ANTENNAGATEAREA  0.495000 ;
    DIRECTION INPUT ;
    USE SIGNAL ;
    PORT
      LAYER li1 ;
        RECT 0.840000 1.075000 1.390000 1.275000 ;
    END
  END A
  PIN B
    ANTENNAGATEAREA  0.495000 ;
    DIRECTION INPUT ;
    USE SIGNAL ;
    PORT
      LAYER li1 ;
        RECT 0.425000 0.995000 0.670000 1.445000 ;
        RECT 0.425000 1.445000 1.730000 1.615000 ;
        RECT 1.560000 1.075000 1.935000 1.245000 ;
        RECT 1.560000 1.245000 1.730000 1.445000 ;
    END
  END B
  PIN X
    ANTENNADIFFAREA  0.800500 ;
    DIRECTION OUTPUT ;
    USE SIGNAL ;
    PORT
      LAYER li1 ;
        RECT 1.720000 0.315000 2.675000 0.485000 ;
        RECT 2.505000 0.485000 2.675000 1.365000 ;
        RECT 2.505000 1.365000 3.135000 1.535000 ;
        RECT 2.815000 1.535000 3.135000 2.465000 ;
    END
  END X
  PIN VGND
    DIRECTION INOUT ;
    SHAPE ABUTMENT ;
    USE GROUND ;
    PORT
      LAYER li1 ;
        RECT 0.000000 -0.085000 3.220000 0.085000 ;
        RECT 0.135000  0.085000 0.465000 0.475000 ;
        RECT 0.975000  0.085000 1.305000 0.475000 ;
        RECT 2.845000  0.085000 3.135000 0.920000 ;
    END
    PORT
      LAYER met1 ;
        RECT 0.000000 -0.240000 3.220000 0.240000 ;
    END
  END VGND
  PIN VPWR
    DIRECTION INOUT ;
    SHAPE ABUTMENT ;
    USE POWER ;
    PORT
      LAYER li1 ;
        RECT 0.000000 2.635000 3.220000 2.805000 ;
        RECT 1.055000 1.785000 1.225000 2.635000 ;
        RECT 1.895000 2.125000 2.065000 2.635000 ;
    END
    PORT
      LAYER met1 ;
        RECT 0.000000 2.480000 3.220000 2.960000 ;
    END
  END VPWR
  OBS
    LAYER li1 ;
      RECT 0.085000 0.655000 2.335000 0.825000 ;
      RECT 0.085000 0.825000 0.255000 1.785000 ;
      RECT 0.085000 1.785000 0.465000 2.465000 ;
      RECT 0.635000 0.335000 0.805000 0.655000 ;
      RECT 1.395000 1.785000 2.635000 1.955000 ;
      RECT 1.395000 1.955000 1.725000 2.465000 ;
      RECT 2.105000 0.825000 2.335000 1.325000 ;
      RECT 2.235000 1.955000 2.635000 2.465000 ;
  END
END sky130_fd_sc_hd__xor2_1
END LIBRARY
# Copyright 2020 The SkyWater PDK Authors
#
# Licensed under the Apache License, Version 2.0 (the "License");
# you may not use this file except in compliance with the License.
# You may obtain a copy of the License at
#
#     https://www.apache.org/licenses/LICENSE-2.0
#
# Unless required by applicable law or agreed to in writing, software
# distributed under the License is distributed on an "AS IS" BASIS,
# WITHOUT WARRANTIES OR CONDITIONS OF ANY KIND, either express or implied.
# See the License for the specific language governing permissions and
# limitations under the License.
#
# SPDX-License-Identifier: Apache-2.0

VERSION 5.5 ;
NAMESCASESENSITIVE ON ;
BUSBITCHARS "[]" ;
DIVIDERCHAR "/" ;
MACRO sky130_fd_sc_hd__xor3_1
  CLASS CORE ;
  SOURCE USER ;
  ORIGIN  0.000000  0.000000 ;
  SIZE  8.740000 BY  2.720000 ;
  SYMMETRY X Y R90 ;
  SITE unithd ;
  PIN A
    ANTENNAGATEAREA  0.246000 ;
    DIRECTION INPUT ;
    USE SIGNAL ;
    PORT
      LAYER li1 ;
        RECT 7.505000 1.075000 7.915000 1.325000 ;
    END
  END A
  PIN B
    ANTENNAGATEAREA  0.661500 ;
    DIRECTION INPUT ;
    USE SIGNAL ;
    PORT
      LAYER li1 ;
        RECT 6.685000 0.995000 6.855000 1.445000 ;
        RECT 6.685000 1.445000 7.265000 1.615000 ;
    END
  END B
  PIN C
    ANTENNAGATEAREA  0.381000 ;
    DIRECTION INPUT ;
    USE SIGNAL ;
    PORT
      LAYER li1 ;
        RECT 1.860000 0.995000 2.495000 1.325000 ;
    END
  END C
  PIN X
    ANTENNADIFFAREA  0.449000 ;
    DIRECTION OUTPUT ;
    USE SIGNAL ;
    PORT
      LAYER li1 ;
        RECT 0.085000 0.350000 0.590000 0.925000 ;
        RECT 0.085000 0.925000 0.400000 1.440000 ;
        RECT 0.085000 1.440000 0.610000 2.465000 ;
    END
  END X
  PIN VGND
    DIRECTION INOUT ;
    SHAPE ABUTMENT ;
    USE GROUND ;
    PORT
      LAYER li1 ;
        RECT 0.000000 -0.085000 8.740000 0.085000 ;
        RECT 0.760000  0.085000 1.010000 0.525000 ;
        RECT 3.930000  0.085000 4.100000 0.865000 ;
        RECT 7.935000  0.085000 8.105000 0.565000 ;
    END
    PORT
      LAYER met1 ;
        RECT 0.000000 -0.240000 8.740000 0.240000 ;
    END
  END VGND
  PIN VPWR
    DIRECTION INOUT ;
    SHAPE ABUTMENT ;
    USE POWER ;
    PORT
      LAYER li1 ;
        RECT 0.000000 2.635000 8.740000 2.805000 ;
        RECT 0.780000 2.215000 1.115000 2.635000 ;
        RECT 3.685000 2.235000 4.015000 2.635000 ;
        RECT 7.855000 2.275000 8.190000 2.635000 ;
    END
    PORT
      LAYER met1 ;
        RECT 0.000000 2.480000 8.740000 2.960000 ;
    END
  END VPWR
  OBS
    LAYER li1 ;
      RECT 0.750000 0.995000 0.950000 1.325000 ;
      RECT 0.780000 0.695000 1.350000 0.865000 ;
      RECT 0.780000 0.865000 0.950000 0.995000 ;
      RECT 0.780000 1.325000 0.950000 1.875000 ;
      RECT 0.780000 1.875000 1.470000 2.045000 ;
      RECT 1.180000 0.255000 2.740000 0.425000 ;
      RECT 1.180000 0.425000 1.350000 0.695000 ;
      RECT 1.185000 1.535000 2.835000 1.705000 ;
      RECT 1.300000 2.045000 1.470000 2.235000 ;
      RECT 1.300000 2.235000 2.895000 2.405000 ;
      RECT 1.520000 0.595000 1.690000 1.535000 ;
      RECT 1.870000 1.895000 3.175000 2.065000 ;
      RECT 1.970000 0.655000 3.080000 0.825000 ;
      RECT 2.390000 0.425000 2.740000 0.455000 ;
      RECT 2.665000 0.995000 2.940000 1.325000 ;
      RECT 2.665000 1.325000 2.835000 1.535000 ;
      RECT 2.910000 0.255000 3.760000 0.425000 ;
      RECT 2.910000 0.425000 3.080000 0.655000 ;
      RECT 3.005000 1.525000 3.535000 1.695000 ;
      RECT 3.005000 1.695000 3.175000 1.895000 ;
      RECT 3.110000 2.235000 3.515000 2.405000 ;
      RECT 3.250000 0.595000 3.420000 1.375000 ;
      RECT 3.250000 1.375000 3.535000 1.525000 ;
      RECT 3.345000 1.895000 4.520000 2.065000 ;
      RECT 3.345000 2.065000 3.515000 2.235000 ;
      RECT 3.590000 0.425000 3.760000 1.035000 ;
      RECT 3.590000 1.035000 3.875000 1.205000 ;
      RECT 3.705000 1.205000 3.875000 1.895000 ;
      RECT 4.105000 1.445000 4.520000 1.715000 ;
      RECT 4.280000 0.415000 4.520000 1.445000 ;
      RECT 4.350000 2.065000 4.520000 2.275000 ;
      RECT 4.350000 2.275000 7.445000 2.445000 ;
      RECT 4.695000 0.265000 5.110000 0.485000 ;
      RECT 4.695000 0.485000 4.915000 0.595000 ;
      RECT 4.695000 0.595000 4.865000 2.105000 ;
      RECT 5.035000 0.720000 5.450000 0.825000 ;
      RECT 5.035000 0.825000 5.255000 0.890000 ;
      RECT 5.035000 0.890000 5.205000 2.275000 ;
      RECT 5.085000 0.655000 5.450000 0.720000 ;
      RECT 5.280000 0.320000 5.450000 0.655000 ;
      RECT 5.395000 1.445000 6.175000 1.615000 ;
      RECT 5.395000 1.615000 5.810000 2.045000 ;
      RECT 5.410000 0.995000 5.835000 1.270000 ;
      RECT 5.620000 0.630000 5.835000 0.995000 ;
      RECT 6.005000 0.255000 7.150000 0.425000 ;
      RECT 6.005000 0.425000 6.175000 1.445000 ;
      RECT 6.345000 0.595000 6.515000 1.935000 ;
      RECT 6.345000 1.935000 8.655000 2.105000 ;
      RECT 6.685000 0.425000 7.150000 0.465000 ;
      RECT 7.025000 0.730000 7.230000 0.945000 ;
      RECT 7.025000 0.945000 7.335000 1.275000 ;
      RECT 7.435000 1.495000 8.255000 1.705000 ;
      RECT 7.475000 0.295000 7.765000 0.735000 ;
      RECT 7.475000 0.735000 8.255000 0.750000 ;
      RECT 7.515000 0.750000 8.255000 0.905000 ;
      RECT 8.085000 0.905000 8.255000 0.995000 ;
      RECT 8.085000 0.995000 8.315000 1.325000 ;
      RECT 8.085000 1.325000 8.255000 1.495000 ;
      RECT 8.170000 1.875000 8.655000 1.935000 ;
      RECT 8.355000 0.255000 8.655000 0.585000 ;
      RECT 8.360000 2.105000 8.655000 2.465000 ;
      RECT 8.485000 0.585000 8.655000 1.875000 ;
    LAYER mcon ;
      RECT 3.365000 1.445000 3.535000 1.615000 ;
      RECT 4.285000 0.765000 4.455000 0.935000 ;
      RECT 4.745000 0.425000 4.915000 0.595000 ;
      RECT 5.665000 0.765000 5.835000 0.935000 ;
      RECT 5.665000 1.445000 5.835000 1.615000 ;
      RECT 7.045000 0.765000 7.215000 0.935000 ;
      RECT 7.505000 0.425000 7.675000 0.595000 ;
    LAYER met1 ;
      RECT 3.305000 1.415000 3.595000 1.460000 ;
      RECT 3.305000 1.460000 5.895000 1.600000 ;
      RECT 3.305000 1.600000 3.595000 1.645000 ;
      RECT 4.225000 0.735000 4.515000 0.780000 ;
      RECT 4.225000 0.780000 7.275000 0.920000 ;
      RECT 4.225000 0.920000 4.515000 0.965000 ;
      RECT 4.685000 0.395000 4.975000 0.440000 ;
      RECT 4.685000 0.440000 7.735000 0.580000 ;
      RECT 4.685000 0.580000 4.975000 0.625000 ;
      RECT 5.605000 0.735000 5.895000 0.780000 ;
      RECT 5.605000 0.920000 5.895000 0.965000 ;
      RECT 5.605000 1.415000 5.895000 1.460000 ;
      RECT 5.605000 1.600000 5.895000 1.645000 ;
      RECT 6.985000 0.735000 7.275000 0.780000 ;
      RECT 6.985000 0.920000 7.275000 0.965000 ;
      RECT 7.445000 0.395000 7.735000 0.440000 ;
      RECT 7.445000 0.580000 7.735000 0.625000 ;
  END
END sky130_fd_sc_hd__xor3_1
END LIBRARY
